VERSION 5.8 ;
BUSBITCHARS "[]" ;
DIVIDERCHAR "/" ;
UNITS
    DATABASE MICRONS 1000 ;
END UNITS

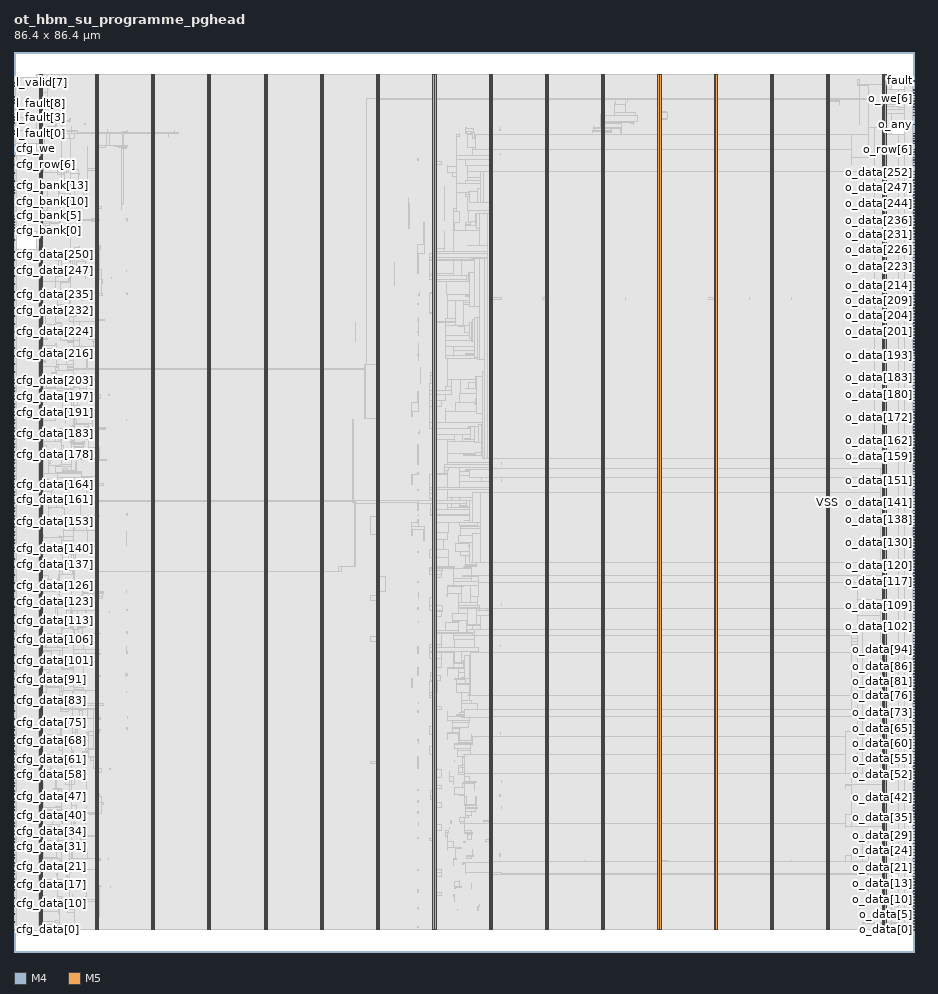
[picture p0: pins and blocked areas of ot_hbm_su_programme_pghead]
MACRO ot_hbm_su_programme_pghead
  FOREIGN ot_hbm_su_programme_pghead 0 0 ;
  CLASS BLOCK ;
  SIZE 86.4 BY 86.4 ;
  PIN cfg_bank[0]
    DIRECTION INPUT ;
    USE SIGNAL ;
    PORT
      LAYER M4 ;
        RECT  0 69.216 0.084 69.24 ;
    END
  END cfg_bank[0]
  PIN cfg_bank[10]
    DIRECTION INPUT ;
    USE SIGNAL ;
    PORT
      LAYER M4 ;
        RECT  0 72.048 0.084 72.072 ;
    END
  END cfg_bank[10]
  PIN cfg_bank[11]
    DIRECTION INPUT ;
    USE SIGNAL ;
    PORT
      LAYER M4 ;
        RECT  0 72.336 0.084 72.36 ;
    END
  END cfg_bank[11]
  PIN cfg_bank[12]
    DIRECTION INPUT ;
    USE SIGNAL ;
    PORT
      LAYER M4 ;
        RECT  0 72.624 0.084 72.648 ;
    END
  END cfg_bank[12]
  PIN cfg_bank[13]
    DIRECTION INPUT ;
    USE SIGNAL ;
    PORT
      LAYER M4 ;
        RECT  0 72.864 0.084 72.888 ;
    END
  END cfg_bank[13]
  PIN cfg_bank[14]
    DIRECTION INPUT ;
    USE SIGNAL ;
    PORT
      LAYER M4 ;
        RECT  0 73.152 0.084 73.176 ;
    END
  END cfg_bank[14]
  PIN cfg_bank[15]
    DIRECTION INPUT ;
    USE SIGNAL ;
    PORT
      LAYER M4 ;
        RECT  0 73.44 0.084 73.464 ;
    END
  END cfg_bank[15]
  PIN cfg_bank[1]
    DIRECTION INPUT ;
    USE SIGNAL ;
    PORT
      LAYER M4 ;
        RECT  0 69.504 0.084 69.528 ;
    END
  END cfg_bank[1]
  PIN cfg_bank[2]
    DIRECTION INPUT ;
    USE SIGNAL ;
    PORT
      LAYER M4 ;
        RECT  0 69.792 0.084 69.816 ;
    END
  END cfg_bank[2]
  PIN cfg_bank[3]
    DIRECTION INPUT ;
    USE SIGNAL ;
    PORT
      LAYER M4 ;
        RECT  0 70.08 0.084 70.104 ;
    END
  END cfg_bank[3]
  PIN cfg_bank[4]
    DIRECTION INPUT ;
    USE SIGNAL ;
    PORT
      LAYER M4 ;
        RECT  0 70.368 0.084 70.392 ;
    END
  END cfg_bank[4]
  PIN cfg_bank[5]
    DIRECTION INPUT ;
    USE SIGNAL ;
    PORT
      LAYER M4 ;
        RECT  0 70.656 0.084 70.68 ;
    END
  END cfg_bank[5]
  PIN cfg_bank[6]
    DIRECTION INPUT ;
    USE SIGNAL ;
    PORT
      LAYER M4 ;
        RECT  0 70.896 0.084 70.92 ;
    END
  END cfg_bank[6]
  PIN cfg_bank[7]
    DIRECTION INPUT ;
    USE SIGNAL ;
    PORT
      LAYER M4 ;
        RECT  0 71.184 0.084 71.208 ;
    END
  END cfg_bank[7]
  PIN cfg_bank[8]
    DIRECTION INPUT ;
    USE SIGNAL ;
    PORT
      LAYER M4 ;
        RECT  0 71.472 0.084 71.496 ;
    END
  END cfg_bank[8]
  PIN cfg_bank[9]
    DIRECTION INPUT ;
    USE SIGNAL ;
    PORT
      LAYER M4 ;
        RECT  0 71.76 0.084 71.784 ;
    END
  END cfg_bank[9]
  PIN cfg_data[0]
    DIRECTION INPUT ;
    USE SIGNAL ;
    PORT
      LAYER M4 ;
        RECT  0 2.112 0.084 2.136 ;
    END
  END cfg_data[0]
  PIN cfg_data[100]
    DIRECTION INPUT ;
    USE SIGNAL ;
    PORT
      LAYER M4 ;
        RECT  0 27.744 0.084 27.768 ;
    END
  END cfg_data[100]
  PIN cfg_data[101]
    DIRECTION INPUT ;
    USE SIGNAL ;
    PORT
      LAYER M4 ;
        RECT  0 27.984 0.084 28.008 ;
    END
  END cfg_data[101]
  PIN cfg_data[102]
    DIRECTION INPUT ;
    USE SIGNAL ;
    PORT
      LAYER M4 ;
        RECT  0 28.272 0.084 28.296 ;
    END
  END cfg_data[102]
  PIN cfg_data[103]
    DIRECTION INPUT ;
    USE SIGNAL ;
    PORT
      LAYER M4 ;
        RECT  0 28.512 0.084 28.536 ;
    END
  END cfg_data[103]
  PIN cfg_data[104]
    DIRECTION INPUT ;
    USE SIGNAL ;
    PORT
      LAYER M4 ;
        RECT  0 28.752 0.084 28.776 ;
    END
  END cfg_data[104]
  PIN cfg_data[105]
    DIRECTION INPUT ;
    USE SIGNAL ;
    PORT
      LAYER M4 ;
        RECT  0 29.04 0.084 29.064 ;
    END
  END cfg_data[105]
  PIN cfg_data[106]
    DIRECTION INPUT ;
    USE SIGNAL ;
    PORT
      LAYER M4 ;
        RECT  0 29.28 0.084 29.304 ;
    END
  END cfg_data[106]
  PIN cfg_data[107]
    DIRECTION INPUT ;
    USE SIGNAL ;
    PORT
      LAYER M4 ;
        RECT  0 29.52 0.084 29.544 ;
    END
  END cfg_data[107]
  PIN cfg_data[108]
    DIRECTION INPUT ;
    USE SIGNAL ;
    PORT
      LAYER M4 ;
        RECT  0 29.808 0.084 29.832 ;
    END
  END cfg_data[108]
  PIN cfg_data[109]
    DIRECTION INPUT ;
    USE SIGNAL ;
    PORT
      LAYER M4 ;
        RECT  0 30.048 0.084 30.072 ;
    END
  END cfg_data[109]
  PIN cfg_data[10]
    DIRECTION INPUT ;
    USE SIGNAL ;
    PORT
      LAYER M4 ;
        RECT  0 4.656 0.084 4.68 ;
    END
  END cfg_data[10]
  PIN cfg_data[110]
    DIRECTION INPUT ;
    USE SIGNAL ;
    PORT
      LAYER M4 ;
        RECT  0 30.288 0.084 30.312 ;
    END
  END cfg_data[110]
  PIN cfg_data[111]
    DIRECTION INPUT ;
    USE SIGNAL ;
    PORT
      LAYER M4 ;
        RECT  0 30.576 0.084 30.6 ;
    END
  END cfg_data[111]
  PIN cfg_data[112]
    DIRECTION INPUT ;
    USE SIGNAL ;
    PORT
      LAYER M4 ;
        RECT  0 30.816 0.084 30.84 ;
    END
  END cfg_data[112]
  PIN cfg_data[113]
    DIRECTION INPUT ;
    USE SIGNAL ;
    PORT
      LAYER M4 ;
        RECT  0 31.056 0.084 31.08 ;
    END
  END cfg_data[113]
  PIN cfg_data[114]
    DIRECTION INPUT ;
    USE SIGNAL ;
    PORT
      LAYER M4 ;
        RECT  0 31.344 0.084 31.368 ;
    END
  END cfg_data[114]
  PIN cfg_data[115]
    DIRECTION INPUT ;
    USE SIGNAL ;
    PORT
      LAYER M4 ;
        RECT  0 31.584 0.084 31.608 ;
    END
  END cfg_data[115]
  PIN cfg_data[116]
    DIRECTION INPUT ;
    USE SIGNAL ;
    PORT
      LAYER M4 ;
        RECT  0 31.824 0.084 31.848 ;
    END
  END cfg_data[116]
  PIN cfg_data[117]
    DIRECTION INPUT ;
    USE SIGNAL ;
    PORT
      LAYER M4 ;
        RECT  0 32.112 0.084 32.136 ;
    END
  END cfg_data[117]
  PIN cfg_data[118]
    DIRECTION INPUT ;
    USE SIGNAL ;
    PORT
      LAYER M4 ;
        RECT  0 32.352 0.084 32.376 ;
    END
  END cfg_data[118]
  PIN cfg_data[119]
    DIRECTION INPUT ;
    USE SIGNAL ;
    PORT
      LAYER M4 ;
        RECT  0 32.592 0.084 32.616 ;
    END
  END cfg_data[119]
  PIN cfg_data[11]
    DIRECTION INPUT ;
    USE SIGNAL ;
    PORT
      LAYER M4 ;
        RECT  0 4.944 0.084 4.968 ;
    END
  END cfg_data[11]
  PIN cfg_data[120]
    DIRECTION INPUT ;
    USE SIGNAL ;
    PORT
      LAYER M4 ;
        RECT  0 32.88 0.084 32.904 ;
    END
  END cfg_data[120]
  PIN cfg_data[121]
    DIRECTION INPUT ;
    USE SIGNAL ;
    PORT
      LAYER M4 ;
        RECT  0 33.12 0.084 33.144 ;
    END
  END cfg_data[121]
  PIN cfg_data[122]
    DIRECTION INPUT ;
    USE SIGNAL ;
    PORT
      LAYER M4 ;
        RECT  0 33.36 0.084 33.384 ;
    END
  END cfg_data[122]
  PIN cfg_data[123]
    DIRECTION INPUT ;
    USE SIGNAL ;
    PORT
      LAYER M4 ;
        RECT  0 33.648 0.084 33.672 ;
    END
  END cfg_data[123]
  PIN cfg_data[124]
    DIRECTION INPUT ;
    USE SIGNAL ;
    PORT
      LAYER M4 ;
        RECT  0 33.888 0.084 33.912 ;
    END
  END cfg_data[124]
  PIN cfg_data[125]
    DIRECTION INPUT ;
    USE SIGNAL ;
    PORT
      LAYER M4 ;
        RECT  0 34.128 0.084 34.152 ;
    END
  END cfg_data[125]
  PIN cfg_data[126]
    DIRECTION INPUT ;
    USE SIGNAL ;
    PORT
      LAYER M4 ;
        RECT  0 34.416 0.084 34.44 ;
    END
  END cfg_data[126]
  PIN cfg_data[127]
    DIRECTION INPUT ;
    USE SIGNAL ;
    PORT
      LAYER M4 ;
        RECT  0 34.656 0.084 34.68 ;
    END
  END cfg_data[127]
  PIN cfg_data[128]
    DIRECTION INPUT ;
    USE SIGNAL ;
    PORT
      LAYER M4 ;
        RECT  0 34.896 0.084 34.92 ;
    END
  END cfg_data[128]
  PIN cfg_data[129]
    DIRECTION INPUT ;
    USE SIGNAL ;
    PORT
      LAYER M4 ;
        RECT  0 35.184 0.084 35.208 ;
    END
  END cfg_data[129]
  PIN cfg_data[12]
    DIRECTION INPUT ;
    USE SIGNAL ;
    PORT
      LAYER M4 ;
        RECT  0 5.184 0.084 5.208 ;
    END
  END cfg_data[12]
  PIN cfg_data[130]
    DIRECTION INPUT ;
    USE SIGNAL ;
    PORT
      LAYER M4 ;
        RECT  0 35.424 0.084 35.448 ;
    END
  END cfg_data[130]
  PIN cfg_data[131]
    DIRECTION INPUT ;
    USE SIGNAL ;
    PORT
      LAYER M4 ;
        RECT  0 35.664 0.084 35.688 ;
    END
  END cfg_data[131]
  PIN cfg_data[132]
    DIRECTION INPUT ;
    USE SIGNAL ;
    PORT
      LAYER M4 ;
        RECT  0 35.952 0.084 35.976 ;
    END
  END cfg_data[132]
  PIN cfg_data[133]
    DIRECTION INPUT ;
    USE SIGNAL ;
    PORT
      LAYER M4 ;
        RECT  0 36.192 0.084 36.216 ;
    END
  END cfg_data[133]
  PIN cfg_data[134]
    DIRECTION INPUT ;
    USE SIGNAL ;
    PORT
      LAYER M4 ;
        RECT  0 36.432 0.084 36.456 ;
    END
  END cfg_data[134]
  PIN cfg_data[135]
    DIRECTION INPUT ;
    USE SIGNAL ;
    PORT
      LAYER M4 ;
        RECT  0 36.72 0.084 36.744 ;
    END
  END cfg_data[135]
  PIN cfg_data[136]
    DIRECTION INPUT ;
    USE SIGNAL ;
    PORT
      LAYER M4 ;
        RECT  0 36.96 0.084 36.984 ;
    END
  END cfg_data[136]
  PIN cfg_data[137]
    DIRECTION INPUT ;
    USE SIGNAL ;
    PORT
      LAYER M4 ;
        RECT  0 37.2 0.084 37.224 ;
    END
  END cfg_data[137]
  PIN cfg_data[138]
    DIRECTION INPUT ;
    USE SIGNAL ;
    PORT
      LAYER M4 ;
        RECT  0 37.488 0.084 37.512 ;
    END
  END cfg_data[138]
  PIN cfg_data[139]
    DIRECTION INPUT ;
    USE SIGNAL ;
    PORT
      LAYER M4 ;
        RECT  0 37.728 0.084 37.752 ;
    END
  END cfg_data[139]
  PIN cfg_data[13]
    DIRECTION INPUT ;
    USE SIGNAL ;
    PORT
      LAYER M4 ;
        RECT  0 5.424 0.084 5.448 ;
    END
  END cfg_data[13]
  PIN cfg_data[140]
    DIRECTION INPUT ;
    USE SIGNAL ;
    PORT
      LAYER M4 ;
        RECT  0 37.968 0.084 37.992 ;
    END
  END cfg_data[140]
  PIN cfg_data[141]
    DIRECTION INPUT ;
    USE SIGNAL ;
    PORT
      LAYER M4 ;
        RECT  0 38.256 0.084 38.28 ;
    END
  END cfg_data[141]
  PIN cfg_data[142]
    DIRECTION INPUT ;
    USE SIGNAL ;
    PORT
      LAYER M4 ;
        RECT  0 38.496 0.084 38.52 ;
    END
  END cfg_data[142]
  PIN cfg_data[143]
    DIRECTION INPUT ;
    USE SIGNAL ;
    PORT
      LAYER M4 ;
        RECT  0 38.784 0.084 38.808 ;
    END
  END cfg_data[143]
  PIN cfg_data[144]
    DIRECTION INPUT ;
    USE SIGNAL ;
    PORT
      LAYER M4 ;
        RECT  0 39.024 0.084 39.048 ;
    END
  END cfg_data[144]
  PIN cfg_data[145]
    DIRECTION INPUT ;
    USE SIGNAL ;
    PORT
      LAYER M4 ;
        RECT  0 39.264 0.084 39.288 ;
    END
  END cfg_data[145]
  PIN cfg_data[146]
    DIRECTION INPUT ;
    USE SIGNAL ;
    PORT
      LAYER M4 ;
        RECT  0 39.552 0.084 39.576 ;
    END
  END cfg_data[146]
  PIN cfg_data[147]
    DIRECTION INPUT ;
    USE SIGNAL ;
    PORT
      LAYER M4 ;
        RECT  0 39.792 0.084 39.816 ;
    END
  END cfg_data[147]
  PIN cfg_data[148]
    DIRECTION INPUT ;
    USE SIGNAL ;
    PORT
      LAYER M4 ;
        RECT  0 40.032 0.084 40.056 ;
    END
  END cfg_data[148]
  PIN cfg_data[149]
    DIRECTION INPUT ;
    USE SIGNAL ;
    PORT
      LAYER M4 ;
        RECT  0 40.32 0.084 40.344 ;
    END
  END cfg_data[149]
  PIN cfg_data[14]
    DIRECTION INPUT ;
    USE SIGNAL ;
    PORT
      LAYER M4 ;
        RECT  0 5.712 0.084 5.736 ;
    END
  END cfg_data[14]
  PIN cfg_data[150]
    DIRECTION INPUT ;
    USE SIGNAL ;
    PORT
      LAYER M4 ;
        RECT  0 40.56 0.084 40.584 ;
    END
  END cfg_data[150]
  PIN cfg_data[151]
    DIRECTION INPUT ;
    USE SIGNAL ;
    PORT
      LAYER M4 ;
        RECT  0 40.8 0.084 40.824 ;
    END
  END cfg_data[151]
  PIN cfg_data[152]
    DIRECTION INPUT ;
    USE SIGNAL ;
    PORT
      LAYER M4 ;
        RECT  0 41.088 0.084 41.112 ;
    END
  END cfg_data[152]
  PIN cfg_data[153]
    DIRECTION INPUT ;
    USE SIGNAL ;
    PORT
      LAYER M4 ;
        RECT  0 41.328 0.084 41.352 ;
    END
  END cfg_data[153]
  PIN cfg_data[154]
    DIRECTION INPUT ;
    USE SIGNAL ;
    PORT
      LAYER M4 ;
        RECT  0 41.568 0.084 41.592 ;
    END
  END cfg_data[154]
  PIN cfg_data[155]
    DIRECTION INPUT ;
    USE SIGNAL ;
    PORT
      LAYER M4 ;
        RECT  0 41.856 0.084 41.88 ;
    END
  END cfg_data[155]
  PIN cfg_data[156]
    DIRECTION INPUT ;
    USE SIGNAL ;
    PORT
      LAYER M4 ;
        RECT  0 42.096 0.084 42.12 ;
    END
  END cfg_data[156]
  PIN cfg_data[157]
    DIRECTION INPUT ;
    USE SIGNAL ;
    PORT
      LAYER M4 ;
        RECT  0 42.336 0.084 42.36 ;
    END
  END cfg_data[157]
  PIN cfg_data[158]
    DIRECTION INPUT ;
    USE SIGNAL ;
    PORT
      LAYER M4 ;
        RECT  0 42.624 0.084 42.648 ;
    END
  END cfg_data[158]
  PIN cfg_data[159]
    DIRECTION INPUT ;
    USE SIGNAL ;
    PORT
      LAYER M4 ;
        RECT  0 42.864 0.084 42.888 ;
    END
  END cfg_data[159]
  PIN cfg_data[15]
    DIRECTION INPUT ;
    USE SIGNAL ;
    PORT
      LAYER M4 ;
        RECT  0 5.952 0.084 5.976 ;
    END
  END cfg_data[15]
  PIN cfg_data[160]
    DIRECTION INPUT ;
    USE SIGNAL ;
    PORT
      LAYER M4 ;
        RECT  0 43.104 0.084 43.128 ;
    END
  END cfg_data[160]
  PIN cfg_data[161]
    DIRECTION INPUT ;
    USE SIGNAL ;
    PORT
      LAYER M4 ;
        RECT  0 43.392 0.084 43.416 ;
    END
  END cfg_data[161]
  PIN cfg_data[162]
    DIRECTION INPUT ;
    USE SIGNAL ;
    PORT
      LAYER M4 ;
        RECT  0 43.632 0.084 43.656 ;
    END
  END cfg_data[162]
  PIN cfg_data[163]
    DIRECTION INPUT ;
    USE SIGNAL ;
    PORT
      LAYER M4 ;
        RECT  0 43.872 0.084 43.896 ;
    END
  END cfg_data[163]
  PIN cfg_data[164]
    DIRECTION INPUT ;
    USE SIGNAL ;
    PORT
      LAYER M4 ;
        RECT  0 44.16 0.084 44.184 ;
    END
  END cfg_data[164]
  PIN cfg_data[165]
    DIRECTION INPUT ;
    USE SIGNAL ;
    PORT
      LAYER M4 ;
        RECT  0 44.4 0.084 44.424 ;
    END
  END cfg_data[165]
  PIN cfg_data[166]
    DIRECTION INPUT ;
    USE SIGNAL ;
    PORT
      LAYER M4 ;
        RECT  0 44.64 0.084 44.664 ;
    END
  END cfg_data[166]
  PIN cfg_data[167]
    DIRECTION INPUT ;
    USE SIGNAL ;
    PORT
      LAYER M4 ;
        RECT  0 44.928 0.084 44.952 ;
    END
  END cfg_data[167]
  PIN cfg_data[168]
    DIRECTION INPUT ;
    USE SIGNAL ;
    PORT
      LAYER M4 ;
        RECT  0 45.168 0.084 45.192 ;
    END
  END cfg_data[168]
  PIN cfg_data[169]
    DIRECTION INPUT ;
    USE SIGNAL ;
    PORT
      LAYER M4 ;
        RECT  0 45.408 0.084 45.432 ;
    END
  END cfg_data[169]
  PIN cfg_data[16]
    DIRECTION INPUT ;
    USE SIGNAL ;
    PORT
      LAYER M4 ;
        RECT  0 6.24 0.084 6.264 ;
    END
  END cfg_data[16]
  PIN cfg_data[170]
    DIRECTION INPUT ;
    USE SIGNAL ;
    PORT
      LAYER M4 ;
        RECT  0 45.696 0.084 45.72 ;
    END
  END cfg_data[170]
  PIN cfg_data[171]
    DIRECTION INPUT ;
    USE SIGNAL ;
    PORT
      LAYER M4 ;
        RECT  0 45.936 0.084 45.96 ;
    END
  END cfg_data[171]
  PIN cfg_data[172]
    DIRECTION INPUT ;
    USE SIGNAL ;
    PORT
      LAYER M4 ;
        RECT  0 46.176 0.084 46.2 ;
    END
  END cfg_data[172]
  PIN cfg_data[173]
    DIRECTION INPUT ;
    USE SIGNAL ;
    PORT
      LAYER M4 ;
        RECT  0 46.464 0.084 46.488 ;
    END
  END cfg_data[173]
  PIN cfg_data[174]
    DIRECTION INPUT ;
    USE SIGNAL ;
    PORT
      LAYER M4 ;
        RECT  0 46.704 0.084 46.728 ;
    END
  END cfg_data[174]
  PIN cfg_data[175]
    DIRECTION INPUT ;
    USE SIGNAL ;
    PORT
      LAYER M4 ;
        RECT  0 46.944 0.084 46.968 ;
    END
  END cfg_data[175]
  PIN cfg_data[176]
    DIRECTION INPUT ;
    USE SIGNAL ;
    PORT
      LAYER M4 ;
        RECT  0 47.232 0.084 47.256 ;
    END
  END cfg_data[176]
  PIN cfg_data[177]
    DIRECTION INPUT ;
    USE SIGNAL ;
    PORT
      LAYER M4 ;
        RECT  0 47.472 0.084 47.496 ;
    END
  END cfg_data[177]
  PIN cfg_data[178]
    DIRECTION INPUT ;
    USE SIGNAL ;
    PORT
      LAYER M4 ;
        RECT  0 47.712 0.084 47.736 ;
    END
  END cfg_data[178]
  PIN cfg_data[179]
    DIRECTION INPUT ;
    USE SIGNAL ;
    PORT
      LAYER M4 ;
        RECT  0 48 0.084 48.024 ;
    END
  END cfg_data[179]
  PIN cfg_data[17]
    DIRECTION INPUT ;
    USE SIGNAL ;
    PORT
      LAYER M4 ;
        RECT  0 6.48 0.084 6.504 ;
    END
  END cfg_data[17]
  PIN cfg_data[180]
    DIRECTION INPUT ;
    USE SIGNAL ;
    PORT
      LAYER M4 ;
        RECT  0 48.24 0.084 48.264 ;
    END
  END cfg_data[180]
  PIN cfg_data[181]
    DIRECTION INPUT ;
    USE SIGNAL ;
    PORT
      LAYER M4 ;
        RECT  0 48.48 0.084 48.504 ;
    END
  END cfg_data[181]
  PIN cfg_data[182]
    DIRECTION INPUT ;
    USE SIGNAL ;
    PORT
      LAYER M4 ;
        RECT  0 48.768 0.084 48.792 ;
    END
  END cfg_data[182]
  PIN cfg_data[183]
    DIRECTION INPUT ;
    USE SIGNAL ;
    PORT
      LAYER M4 ;
        RECT  0 49.008 0.084 49.032 ;
    END
  END cfg_data[183]
  PIN cfg_data[184]
    DIRECTION INPUT ;
    USE SIGNAL ;
    PORT
      LAYER M4 ;
        RECT  0 49.248 0.084 49.272 ;
    END
  END cfg_data[184]
  PIN cfg_data[185]
    DIRECTION INPUT ;
    USE SIGNAL ;
    PORT
      LAYER M4 ;
        RECT  0 49.536 0.084 49.56 ;
    END
  END cfg_data[185]
  PIN cfg_data[186]
    DIRECTION INPUT ;
    USE SIGNAL ;
    PORT
      LAYER M4 ;
        RECT  0 49.776 0.084 49.8 ;
    END
  END cfg_data[186]
  PIN cfg_data[187]
    DIRECTION INPUT ;
    USE SIGNAL ;
    PORT
      LAYER M4 ;
        RECT  0 50.016 0.084 50.04 ;
    END
  END cfg_data[187]
  PIN cfg_data[188]
    DIRECTION INPUT ;
    USE SIGNAL ;
    PORT
      LAYER M4 ;
        RECT  0 50.304 0.084 50.328 ;
    END
  END cfg_data[188]
  PIN cfg_data[189]
    DIRECTION INPUT ;
    USE SIGNAL ;
    PORT
      LAYER M4 ;
        RECT  0 50.544 0.084 50.568 ;
    END
  END cfg_data[189]
  PIN cfg_data[18]
    DIRECTION INPUT ;
    USE SIGNAL ;
    PORT
      LAYER M4 ;
        RECT  0 6.72 0.084 6.744 ;
    END
  END cfg_data[18]
  PIN cfg_data[190]
    DIRECTION INPUT ;
    USE SIGNAL ;
    PORT
      LAYER M4 ;
        RECT  0 50.784 0.084 50.808 ;
    END
  END cfg_data[190]
  PIN cfg_data[191]
    DIRECTION INPUT ;
    USE SIGNAL ;
    PORT
      LAYER M4 ;
        RECT  0 51.072 0.084 51.096 ;
    END
  END cfg_data[191]
  PIN cfg_data[192]
    DIRECTION INPUT ;
    USE SIGNAL ;
    PORT
      LAYER M4 ;
        RECT  0 51.312 0.084 51.336 ;
    END
  END cfg_data[192]
  PIN cfg_data[193]
    DIRECTION INPUT ;
    USE SIGNAL ;
    PORT
      LAYER M4 ;
        RECT  0 51.552 0.084 51.576 ;
    END
  END cfg_data[193]
  PIN cfg_data[194]
    DIRECTION INPUT ;
    USE SIGNAL ;
    PORT
      LAYER M4 ;
        RECT  0 51.84 0.084 51.864 ;
    END
  END cfg_data[194]
  PIN cfg_data[195]
    DIRECTION INPUT ;
    USE SIGNAL ;
    PORT
      LAYER M4 ;
        RECT  0 52.08 0.084 52.104 ;
    END
  END cfg_data[195]
  PIN cfg_data[196]
    DIRECTION INPUT ;
    USE SIGNAL ;
    PORT
      LAYER M4 ;
        RECT  0 52.32 0.084 52.344 ;
    END
  END cfg_data[196]
  PIN cfg_data[197]
    DIRECTION INPUT ;
    USE SIGNAL ;
    PORT
      LAYER M4 ;
        RECT  0 52.608 0.084 52.632 ;
    END
  END cfg_data[197]
  PIN cfg_data[198]
    DIRECTION INPUT ;
    USE SIGNAL ;
    PORT
      LAYER M4 ;
        RECT  0 52.848 0.084 52.872 ;
    END
  END cfg_data[198]
  PIN cfg_data[199]
    DIRECTION INPUT ;
    USE SIGNAL ;
    PORT
      LAYER M4 ;
        RECT  0 53.088 0.084 53.112 ;
    END
  END cfg_data[199]
  PIN cfg_data[19]
    DIRECTION INPUT ;
    USE SIGNAL ;
    PORT
      LAYER M4 ;
        RECT  0 7.008 0.084 7.032 ;
    END
  END cfg_data[19]
  PIN cfg_data[1]
    DIRECTION INPUT ;
    USE SIGNAL ;
    PORT
      LAYER M4 ;
        RECT  0 2.352 0.084 2.376 ;
    END
  END cfg_data[1]
  PIN cfg_data[200]
    DIRECTION INPUT ;
    USE SIGNAL ;
    PORT
      LAYER M4 ;
        RECT  0 53.376 0.084 53.4 ;
    END
  END cfg_data[200]
  PIN cfg_data[201]
    DIRECTION INPUT ;
    USE SIGNAL ;
    PORT
      LAYER M4 ;
        RECT  0 53.616 0.084 53.64 ;
    END
  END cfg_data[201]
  PIN cfg_data[202]
    DIRECTION INPUT ;
    USE SIGNAL ;
    PORT
      LAYER M4 ;
        RECT  0 53.856 0.084 53.88 ;
    END
  END cfg_data[202]
  PIN cfg_data[203]
    DIRECTION INPUT ;
    USE SIGNAL ;
    PORT
      LAYER M4 ;
        RECT  0 54.144 0.084 54.168 ;
    END
  END cfg_data[203]
  PIN cfg_data[204]
    DIRECTION INPUT ;
    USE SIGNAL ;
    PORT
      LAYER M4 ;
        RECT  0 54.384 0.084 54.408 ;
    END
  END cfg_data[204]
  PIN cfg_data[205]
    DIRECTION INPUT ;
    USE SIGNAL ;
    PORT
      LAYER M4 ;
        RECT  0 54.624 0.084 54.648 ;
    END
  END cfg_data[205]
  PIN cfg_data[206]
    DIRECTION INPUT ;
    USE SIGNAL ;
    PORT
      LAYER M4 ;
        RECT  0 54.912 0.084 54.936 ;
    END
  END cfg_data[206]
  PIN cfg_data[207]
    DIRECTION INPUT ;
    USE SIGNAL ;
    PORT
      LAYER M4 ;
        RECT  0 55.152 0.084 55.176 ;
    END
  END cfg_data[207]
  PIN cfg_data[208]
    DIRECTION INPUT ;
    USE SIGNAL ;
    PORT
      LAYER M4 ;
        RECT  0 55.44 0.084 55.464 ;
    END
  END cfg_data[208]
  PIN cfg_data[209]
    DIRECTION INPUT ;
    USE SIGNAL ;
    PORT
      LAYER M4 ;
        RECT  0 55.68 0.084 55.704 ;
    END
  END cfg_data[209]
  PIN cfg_data[20]
    DIRECTION INPUT ;
    USE SIGNAL ;
    PORT
      LAYER M4 ;
        RECT  0 7.248 0.084 7.272 ;
    END
  END cfg_data[20]
  PIN cfg_data[210]
    DIRECTION INPUT ;
    USE SIGNAL ;
    PORT
      LAYER M4 ;
        RECT  0 55.92 0.084 55.944 ;
    END
  END cfg_data[210]
  PIN cfg_data[211]
    DIRECTION INPUT ;
    USE SIGNAL ;
    PORT
      LAYER M4 ;
        RECT  0 56.208 0.084 56.232 ;
    END
  END cfg_data[211]
  PIN cfg_data[212]
    DIRECTION INPUT ;
    USE SIGNAL ;
    PORT
      LAYER M4 ;
        RECT  0 56.448 0.084 56.472 ;
    END
  END cfg_data[212]
  PIN cfg_data[213]
    DIRECTION INPUT ;
    USE SIGNAL ;
    PORT
      LAYER M4 ;
        RECT  0 56.688 0.084 56.712 ;
    END
  END cfg_data[213]
  PIN cfg_data[214]
    DIRECTION INPUT ;
    USE SIGNAL ;
    PORT
      LAYER M4 ;
        RECT  0 56.976 0.084 57 ;
    END
  END cfg_data[214]
  PIN cfg_data[215]
    DIRECTION INPUT ;
    USE SIGNAL ;
    PORT
      LAYER M4 ;
        RECT  0 57.216 0.084 57.24 ;
    END
  END cfg_data[215]
  PIN cfg_data[216]
    DIRECTION INPUT ;
    USE SIGNAL ;
    PORT
      LAYER M4 ;
        RECT  0 57.456 0.084 57.48 ;
    END
  END cfg_data[216]
  PIN cfg_data[217]
    DIRECTION INPUT ;
    USE SIGNAL ;
    PORT
      LAYER M4 ;
        RECT  0 57.744 0.084 57.768 ;
    END
  END cfg_data[217]
  PIN cfg_data[218]
    DIRECTION INPUT ;
    USE SIGNAL ;
    PORT
      LAYER M4 ;
        RECT  0 57.984 0.084 58.008 ;
    END
  END cfg_data[218]
  PIN cfg_data[219]
    DIRECTION INPUT ;
    USE SIGNAL ;
    PORT
      LAYER M4 ;
        RECT  0 58.224 0.084 58.248 ;
    END
  END cfg_data[219]
  PIN cfg_data[21]
    DIRECTION INPUT ;
    USE SIGNAL ;
    PORT
      LAYER M4 ;
        RECT  0 7.488 0.084 7.512 ;
    END
  END cfg_data[21]
  PIN cfg_data[220]
    DIRECTION INPUT ;
    USE SIGNAL ;
    PORT
      LAYER M4 ;
        RECT  0 58.512 0.084 58.536 ;
    END
  END cfg_data[220]
  PIN cfg_data[221]
    DIRECTION INPUT ;
    USE SIGNAL ;
    PORT
      LAYER M4 ;
        RECT  0 58.752 0.084 58.776 ;
    END
  END cfg_data[221]
  PIN cfg_data[222]
    DIRECTION INPUT ;
    USE SIGNAL ;
    PORT
      LAYER M4 ;
        RECT  0 58.992 0.084 59.016 ;
    END
  END cfg_data[222]
  PIN cfg_data[223]
    DIRECTION INPUT ;
    USE SIGNAL ;
    PORT
      LAYER M4 ;
        RECT  0 59.28 0.084 59.304 ;
    END
  END cfg_data[223]
  PIN cfg_data[224]
    DIRECTION INPUT ;
    USE SIGNAL ;
    PORT
      LAYER M4 ;
        RECT  0 59.52 0.084 59.544 ;
    END
  END cfg_data[224]
  PIN cfg_data[225]
    DIRECTION INPUT ;
    USE SIGNAL ;
    PORT
      LAYER M4 ;
        RECT  0 59.76 0.084 59.784 ;
    END
  END cfg_data[225]
  PIN cfg_data[226]
    DIRECTION INPUT ;
    USE SIGNAL ;
    PORT
      LAYER M4 ;
        RECT  0 60.048 0.084 60.072 ;
    END
  END cfg_data[226]
  PIN cfg_data[227]
    DIRECTION INPUT ;
    USE SIGNAL ;
    PORT
      LAYER M4 ;
        RECT  0 60.288 0.084 60.312 ;
    END
  END cfg_data[227]
  PIN cfg_data[228]
    DIRECTION INPUT ;
    USE SIGNAL ;
    PORT
      LAYER M4 ;
        RECT  0 60.528 0.084 60.552 ;
    END
  END cfg_data[228]
  PIN cfg_data[229]
    DIRECTION INPUT ;
    USE SIGNAL ;
    PORT
      LAYER M4 ;
        RECT  0 60.816 0.084 60.84 ;
    END
  END cfg_data[229]
  PIN cfg_data[22]
    DIRECTION INPUT ;
    USE SIGNAL ;
    PORT
      LAYER M4 ;
        RECT  0 7.776 0.084 7.8 ;
    END
  END cfg_data[22]
  PIN cfg_data[230]
    DIRECTION INPUT ;
    USE SIGNAL ;
    PORT
      LAYER M4 ;
        RECT  0 61.056 0.084 61.08 ;
    END
  END cfg_data[230]
  PIN cfg_data[231]
    DIRECTION INPUT ;
    USE SIGNAL ;
    PORT
      LAYER M4 ;
        RECT  0 61.296 0.084 61.32 ;
    END
  END cfg_data[231]
  PIN cfg_data[232]
    DIRECTION INPUT ;
    USE SIGNAL ;
    PORT
      LAYER M4 ;
        RECT  0 61.584 0.084 61.608 ;
    END
  END cfg_data[232]
  PIN cfg_data[233]
    DIRECTION INPUT ;
    USE SIGNAL ;
    PORT
      LAYER M4 ;
        RECT  0 61.824 0.084 61.848 ;
    END
  END cfg_data[233]
  PIN cfg_data[234]
    DIRECTION INPUT ;
    USE SIGNAL ;
    PORT
      LAYER M4 ;
        RECT  0 62.064 0.084 62.088 ;
    END
  END cfg_data[234]
  PIN cfg_data[235]
    DIRECTION INPUT ;
    USE SIGNAL ;
    PORT
      LAYER M4 ;
        RECT  0 62.352 0.084 62.376 ;
    END
  END cfg_data[235]
  PIN cfg_data[236]
    DIRECTION INPUT ;
    USE SIGNAL ;
    PORT
      LAYER M4 ;
        RECT  0 62.592 0.084 62.616 ;
    END
  END cfg_data[236]
  PIN cfg_data[237]
    DIRECTION INPUT ;
    USE SIGNAL ;
    PORT
      LAYER M4 ;
        RECT  0 62.832 0.084 62.856 ;
    END
  END cfg_data[237]
  PIN cfg_data[238]
    DIRECTION INPUT ;
    USE SIGNAL ;
    PORT
      LAYER M4 ;
        RECT  0 63.12 0.084 63.144 ;
    END
  END cfg_data[238]
  PIN cfg_data[239]
    DIRECTION INPUT ;
    USE SIGNAL ;
    PORT
      LAYER M4 ;
        RECT  0 63.36 0.084 63.384 ;
    END
  END cfg_data[239]
  PIN cfg_data[23]
    DIRECTION INPUT ;
    USE SIGNAL ;
    PORT
      LAYER M4 ;
        RECT  0 8.016 0.084 8.04 ;
    END
  END cfg_data[23]
  PIN cfg_data[240]
    DIRECTION INPUT ;
    USE SIGNAL ;
    PORT
      LAYER M4 ;
        RECT  0 63.6 0.084 63.624 ;
    END
  END cfg_data[240]
  PIN cfg_data[241]
    DIRECTION INPUT ;
    USE SIGNAL ;
    PORT
      LAYER M4 ;
        RECT  0 63.888 0.084 63.912 ;
    END
  END cfg_data[241]
  PIN cfg_data[242]
    DIRECTION INPUT ;
    USE SIGNAL ;
    PORT
      LAYER M4 ;
        RECT  0 64.128 0.084 64.152 ;
    END
  END cfg_data[242]
  PIN cfg_data[243]
    DIRECTION INPUT ;
    USE SIGNAL ;
    PORT
      LAYER M4 ;
        RECT  0 64.368 0.084 64.392 ;
    END
  END cfg_data[243]
  PIN cfg_data[244]
    DIRECTION INPUT ;
    USE SIGNAL ;
    PORT
      LAYER M4 ;
        RECT  0 64.656 0.084 64.68 ;
    END
  END cfg_data[244]
  PIN cfg_data[245]
    DIRECTION INPUT ;
    USE SIGNAL ;
    PORT
      LAYER M4 ;
        RECT  0 64.896 0.084 64.92 ;
    END
  END cfg_data[245]
  PIN cfg_data[246]
    DIRECTION INPUT ;
    USE SIGNAL ;
    PORT
      LAYER M4 ;
        RECT  0 65.136 0.084 65.16 ;
    END
  END cfg_data[246]
  PIN cfg_data[247]
    DIRECTION INPUT ;
    USE SIGNAL ;
    PORT
      LAYER M4 ;
        RECT  0 65.424 0.084 65.448 ;
    END
  END cfg_data[247]
  PIN cfg_data[248]
    DIRECTION INPUT ;
    USE SIGNAL ;
    PORT
      LAYER M4 ;
        RECT  0 65.664 0.084 65.688 ;
    END
  END cfg_data[248]
  PIN cfg_data[249]
    DIRECTION INPUT ;
    USE SIGNAL ;
    PORT
      LAYER M4 ;
        RECT  0 65.904 0.084 65.928 ;
    END
  END cfg_data[249]
  PIN cfg_data[24]
    DIRECTION INPUT ;
    USE SIGNAL ;
    PORT
      LAYER M4 ;
        RECT  0 8.256 0.084 8.28 ;
    END
  END cfg_data[24]
  PIN cfg_data[250]
    DIRECTION INPUT ;
    USE SIGNAL ;
    PORT
      LAYER M4 ;
        RECT  0 66.192 0.084 66.216 ;
    END
  END cfg_data[250]
  PIN cfg_data[251]
    DIRECTION INPUT ;
    USE SIGNAL ;
    PORT
      LAYER M4 ;
        RECT  0 66.432 0.084 66.456 ;
    END
  END cfg_data[251]
  PIN cfg_data[252]
    DIRECTION INPUT ;
    USE SIGNAL ;
    PORT
      LAYER M4 ;
        RECT  0 66.672 0.084 66.696 ;
    END
  END cfg_data[252]
  PIN cfg_data[253]
    DIRECTION INPUT ;
    USE SIGNAL ;
    PORT
      LAYER M4 ;
        RECT  0 66.96 0.084 66.984 ;
    END
  END cfg_data[253]
  PIN cfg_data[254]
    DIRECTION INPUT ;
    USE SIGNAL ;
    PORT
      LAYER M4 ;
        RECT  0 67.2 0.084 67.224 ;
    END
  END cfg_data[254]
  PIN cfg_data[255]
    DIRECTION INPUT ;
    USE SIGNAL ;
    PORT
      LAYER M4 ;
        RECT  0 67.44 0.084 67.464 ;
    END
  END cfg_data[255]
  PIN cfg_data[25]
    DIRECTION INPUT ;
    USE SIGNAL ;
    PORT
      LAYER M4 ;
        RECT  0 8.544 0.084 8.568 ;
    END
  END cfg_data[25]
  PIN cfg_data[26]
    DIRECTION INPUT ;
    USE SIGNAL ;
    PORT
      LAYER M4 ;
        RECT  0 8.784 0.084 8.808 ;
    END
  END cfg_data[26]
  PIN cfg_data[27]
    DIRECTION INPUT ;
    USE SIGNAL ;
    PORT
      LAYER M4 ;
        RECT  0 9.024 0.084 9.048 ;
    END
  END cfg_data[27]
  PIN cfg_data[28]
    DIRECTION INPUT ;
    USE SIGNAL ;
    PORT
      LAYER M4 ;
        RECT  0 9.312 0.084 9.336 ;
    END
  END cfg_data[28]
  PIN cfg_data[29]
    DIRECTION INPUT ;
    USE SIGNAL ;
    PORT
      LAYER M4 ;
        RECT  0 9.552 0.084 9.576 ;
    END
  END cfg_data[29]
  PIN cfg_data[2]
    DIRECTION INPUT ;
    USE SIGNAL ;
    PORT
      LAYER M4 ;
        RECT  0 2.64 0.084 2.664 ;
    END
  END cfg_data[2]
  PIN cfg_data[30]
    DIRECTION INPUT ;
    USE SIGNAL ;
    PORT
      LAYER M4 ;
        RECT  0 9.792 0.084 9.816 ;
    END
  END cfg_data[30]
  PIN cfg_data[31]
    DIRECTION INPUT ;
    USE SIGNAL ;
    PORT
      LAYER M4 ;
        RECT  0 10.08 0.084 10.104 ;
    END
  END cfg_data[31]
  PIN cfg_data[32]
    DIRECTION INPUT ;
    USE SIGNAL ;
    PORT
      LAYER M4 ;
        RECT  0 10.32 0.084 10.344 ;
    END
  END cfg_data[32]
  PIN cfg_data[33]
    DIRECTION INPUT ;
    USE SIGNAL ;
    PORT
      LAYER M4 ;
        RECT  0 10.56 0.084 10.584 ;
    END
  END cfg_data[33]
  PIN cfg_data[34]
    DIRECTION INPUT ;
    USE SIGNAL ;
    PORT
      LAYER M4 ;
        RECT  0 10.848 0.084 10.872 ;
    END
  END cfg_data[34]
  PIN cfg_data[35]
    DIRECTION INPUT ;
    USE SIGNAL ;
    PORT
      LAYER M4 ;
        RECT  0 11.088 0.084 11.112 ;
    END
  END cfg_data[35]
  PIN cfg_data[36]
    DIRECTION INPUT ;
    USE SIGNAL ;
    PORT
      LAYER M4 ;
        RECT  0 11.328 0.084 11.352 ;
    END
  END cfg_data[36]
  PIN cfg_data[37]
    DIRECTION INPUT ;
    USE SIGNAL ;
    PORT
      LAYER M4 ;
        RECT  0 11.616 0.084 11.64 ;
    END
  END cfg_data[37]
  PIN cfg_data[38]
    DIRECTION INPUT ;
    USE SIGNAL ;
    PORT
      LAYER M4 ;
        RECT  0 11.856 0.084 11.88 ;
    END
  END cfg_data[38]
  PIN cfg_data[39]
    DIRECTION INPUT ;
    USE SIGNAL ;
    PORT
      LAYER M4 ;
        RECT  0 12.096 0.084 12.12 ;
    END
  END cfg_data[39]
  PIN cfg_data[3]
    DIRECTION INPUT ;
    USE SIGNAL ;
    PORT
      LAYER M4 ;
        RECT  0 2.88 0.084 2.904 ;
    END
  END cfg_data[3]
  PIN cfg_data[40]
    DIRECTION INPUT ;
    USE SIGNAL ;
    PORT
      LAYER M4 ;
        RECT  0 12.384 0.084 12.408 ;
    END
  END cfg_data[40]
  PIN cfg_data[41]
    DIRECTION INPUT ;
    USE SIGNAL ;
    PORT
      LAYER M4 ;
        RECT  0 12.624 0.084 12.648 ;
    END
  END cfg_data[41]
  PIN cfg_data[42]
    DIRECTION INPUT ;
    USE SIGNAL ;
    PORT
      LAYER M4 ;
        RECT  0 12.864 0.084 12.888 ;
    END
  END cfg_data[42]
  PIN cfg_data[43]
    DIRECTION INPUT ;
    USE SIGNAL ;
    PORT
      LAYER M4 ;
        RECT  0 13.152 0.084 13.176 ;
    END
  END cfg_data[43]
  PIN cfg_data[44]
    DIRECTION INPUT ;
    USE SIGNAL ;
    PORT
      LAYER M4 ;
        RECT  0 13.392 0.084 13.416 ;
    END
  END cfg_data[44]
  PIN cfg_data[45]
    DIRECTION INPUT ;
    USE SIGNAL ;
    PORT
      LAYER M4 ;
        RECT  0 13.632 0.084 13.656 ;
    END
  END cfg_data[45]
  PIN cfg_data[46]
    DIRECTION INPUT ;
    USE SIGNAL ;
    PORT
      LAYER M4 ;
        RECT  0 13.92 0.084 13.944 ;
    END
  END cfg_data[46]
  PIN cfg_data[47]
    DIRECTION INPUT ;
    USE SIGNAL ;
    PORT
      LAYER M4 ;
        RECT  0 14.16 0.084 14.184 ;
    END
  END cfg_data[47]
  PIN cfg_data[48]
    DIRECTION INPUT ;
    USE SIGNAL ;
    PORT
      LAYER M4 ;
        RECT  0 14.4 0.084 14.424 ;
    END
  END cfg_data[48]
  PIN cfg_data[49]
    DIRECTION INPUT ;
    USE SIGNAL ;
    PORT
      LAYER M4 ;
        RECT  0 14.688 0.084 14.712 ;
    END
  END cfg_data[49]
  PIN cfg_data[4]
    DIRECTION INPUT ;
    USE SIGNAL ;
    PORT
      LAYER M4 ;
        RECT  0 3.12 0.084 3.144 ;
    END
  END cfg_data[4]
  PIN cfg_data[50]
    DIRECTION INPUT ;
    USE SIGNAL ;
    PORT
      LAYER M4 ;
        RECT  0 14.928 0.084 14.952 ;
    END
  END cfg_data[50]
  PIN cfg_data[51]
    DIRECTION INPUT ;
    USE SIGNAL ;
    PORT
      LAYER M4 ;
        RECT  0 15.168 0.084 15.192 ;
    END
  END cfg_data[51]
  PIN cfg_data[52]
    DIRECTION INPUT ;
    USE SIGNAL ;
    PORT
      LAYER M4 ;
        RECT  0 15.456 0.084 15.48 ;
    END
  END cfg_data[52]
  PIN cfg_data[53]
    DIRECTION INPUT ;
    USE SIGNAL ;
    PORT
      LAYER M4 ;
        RECT  0 15.696 0.084 15.72 ;
    END
  END cfg_data[53]
  PIN cfg_data[54]
    DIRECTION INPUT ;
    USE SIGNAL ;
    PORT
      LAYER M4 ;
        RECT  0 15.936 0.084 15.96 ;
    END
  END cfg_data[54]
  PIN cfg_data[55]
    DIRECTION INPUT ;
    USE SIGNAL ;
    PORT
      LAYER M4 ;
        RECT  0 16.224 0.084 16.248 ;
    END
  END cfg_data[55]
  PIN cfg_data[56]
    DIRECTION INPUT ;
    USE SIGNAL ;
    PORT
      LAYER M4 ;
        RECT  0 16.464 0.084 16.488 ;
    END
  END cfg_data[56]
  PIN cfg_data[57]
    DIRECTION INPUT ;
    USE SIGNAL ;
    PORT
      LAYER M4 ;
        RECT  0 16.704 0.084 16.728 ;
    END
  END cfg_data[57]
  PIN cfg_data[58]
    DIRECTION INPUT ;
    USE SIGNAL ;
    PORT
      LAYER M4 ;
        RECT  0 16.992 0.084 17.016 ;
    END
  END cfg_data[58]
  PIN cfg_data[59]
    DIRECTION INPUT ;
    USE SIGNAL ;
    PORT
      LAYER M4 ;
        RECT  0 17.232 0.084 17.256 ;
    END
  END cfg_data[59]
  PIN cfg_data[5]
    DIRECTION INPUT ;
    USE SIGNAL ;
    PORT
      LAYER M4 ;
        RECT  0 3.408 0.084 3.432 ;
    END
  END cfg_data[5]
  PIN cfg_data[60]
    DIRECTION INPUT ;
    USE SIGNAL ;
    PORT
      LAYER M4 ;
        RECT  0 17.472 0.084 17.496 ;
    END
  END cfg_data[60]
  PIN cfg_data[61]
    DIRECTION INPUT ;
    USE SIGNAL ;
    PORT
      LAYER M4 ;
        RECT  0 17.76 0.084 17.784 ;
    END
  END cfg_data[61]
  PIN cfg_data[62]
    DIRECTION INPUT ;
    USE SIGNAL ;
    PORT
      LAYER M4 ;
        RECT  0 18 0.084 18.024 ;
    END
  END cfg_data[62]
  PIN cfg_data[63]
    DIRECTION INPUT ;
    USE SIGNAL ;
    PORT
      LAYER M4 ;
        RECT  0 18.24 0.084 18.264 ;
    END
  END cfg_data[63]
  PIN cfg_data[64]
    DIRECTION INPUT ;
    USE SIGNAL ;
    PORT
      LAYER M4 ;
        RECT  0 18.528 0.084 18.552 ;
    END
  END cfg_data[64]
  PIN cfg_data[65]
    DIRECTION INPUT ;
    USE SIGNAL ;
    PORT
      LAYER M4 ;
        RECT  0 18.768 0.084 18.792 ;
    END
  END cfg_data[65]
  PIN cfg_data[66]
    DIRECTION INPUT ;
    USE SIGNAL ;
    PORT
      LAYER M4 ;
        RECT  0 19.008 0.084 19.032 ;
    END
  END cfg_data[66]
  PIN cfg_data[67]
    DIRECTION INPUT ;
    USE SIGNAL ;
    PORT
      LAYER M4 ;
        RECT  0 19.296 0.084 19.32 ;
    END
  END cfg_data[67]
  PIN cfg_data[68]
    DIRECTION INPUT ;
    USE SIGNAL ;
    PORT
      LAYER M4 ;
        RECT  0 19.536 0.084 19.56 ;
    END
  END cfg_data[68]
  PIN cfg_data[69]
    DIRECTION INPUT ;
    USE SIGNAL ;
    PORT
      LAYER M4 ;
        RECT  0 19.776 0.084 19.8 ;
    END
  END cfg_data[69]
  PIN cfg_data[6]
    DIRECTION INPUT ;
    USE SIGNAL ;
    PORT
      LAYER M4 ;
        RECT  0 3.648 0.084 3.672 ;
    END
  END cfg_data[6]
  PIN cfg_data[70]
    DIRECTION INPUT ;
    USE SIGNAL ;
    PORT
      LAYER M4 ;
        RECT  0 20.064 0.084 20.088 ;
    END
  END cfg_data[70]
  PIN cfg_data[71]
    DIRECTION INPUT ;
    USE SIGNAL ;
    PORT
      LAYER M4 ;
        RECT  0 20.304 0.084 20.328 ;
    END
  END cfg_data[71]
  PIN cfg_data[72]
    DIRECTION INPUT ;
    USE SIGNAL ;
    PORT
      LAYER M4 ;
        RECT  0 20.544 0.084 20.568 ;
    END
  END cfg_data[72]
  PIN cfg_data[73]
    DIRECTION INPUT ;
    USE SIGNAL ;
    PORT
      LAYER M4 ;
        RECT  0 20.832 0.084 20.856 ;
    END
  END cfg_data[73]
  PIN cfg_data[74]
    DIRECTION INPUT ;
    USE SIGNAL ;
    PORT
      LAYER M4 ;
        RECT  0 21.072 0.084 21.096 ;
    END
  END cfg_data[74]
  PIN cfg_data[75]
    DIRECTION INPUT ;
    USE SIGNAL ;
    PORT
      LAYER M4 ;
        RECT  0 21.312 0.084 21.336 ;
    END
  END cfg_data[75]
  PIN cfg_data[76]
    DIRECTION INPUT ;
    USE SIGNAL ;
    PORT
      LAYER M4 ;
        RECT  0 21.6 0.084 21.624 ;
    END
  END cfg_data[76]
  PIN cfg_data[77]
    DIRECTION INPUT ;
    USE SIGNAL ;
    PORT
      LAYER M4 ;
        RECT  0 21.84 0.084 21.864 ;
    END
  END cfg_data[77]
  PIN cfg_data[78]
    DIRECTION INPUT ;
    USE SIGNAL ;
    PORT
      LAYER M4 ;
        RECT  0 22.128 0.084 22.152 ;
    END
  END cfg_data[78]
  PIN cfg_data[79]
    DIRECTION INPUT ;
    USE SIGNAL ;
    PORT
      LAYER M4 ;
        RECT  0 22.368 0.084 22.392 ;
    END
  END cfg_data[79]
  PIN cfg_data[7]
    DIRECTION INPUT ;
    USE SIGNAL ;
    PORT
      LAYER M4 ;
        RECT  0 3.888 0.084 3.912 ;
    END
  END cfg_data[7]
  PIN cfg_data[80]
    DIRECTION INPUT ;
    USE SIGNAL ;
    PORT
      LAYER M4 ;
        RECT  0 22.608 0.084 22.632 ;
    END
  END cfg_data[80]
  PIN cfg_data[81]
    DIRECTION INPUT ;
    USE SIGNAL ;
    PORT
      LAYER M4 ;
        RECT  0 22.896 0.084 22.92 ;
    END
  END cfg_data[81]
  PIN cfg_data[82]
    DIRECTION INPUT ;
    USE SIGNAL ;
    PORT
      LAYER M4 ;
        RECT  0 23.136 0.084 23.16 ;
    END
  END cfg_data[82]
  PIN cfg_data[83]
    DIRECTION INPUT ;
    USE SIGNAL ;
    PORT
      LAYER M4 ;
        RECT  0 23.376 0.084 23.4 ;
    END
  END cfg_data[83]
  PIN cfg_data[84]
    DIRECTION INPUT ;
    USE SIGNAL ;
    PORT
      LAYER M4 ;
        RECT  0 23.664 0.084 23.688 ;
    END
  END cfg_data[84]
  PIN cfg_data[85]
    DIRECTION INPUT ;
    USE SIGNAL ;
    PORT
      LAYER M4 ;
        RECT  0 23.904 0.084 23.928 ;
    END
  END cfg_data[85]
  PIN cfg_data[86]
    DIRECTION INPUT ;
    USE SIGNAL ;
    PORT
      LAYER M4 ;
        RECT  0 24.144 0.084 24.168 ;
    END
  END cfg_data[86]
  PIN cfg_data[87]
    DIRECTION INPUT ;
    USE SIGNAL ;
    PORT
      LAYER M4 ;
        RECT  0 24.432 0.084 24.456 ;
    END
  END cfg_data[87]
  PIN cfg_data[88]
    DIRECTION INPUT ;
    USE SIGNAL ;
    PORT
      LAYER M4 ;
        RECT  0 24.672 0.084 24.696 ;
    END
  END cfg_data[88]
  PIN cfg_data[89]
    DIRECTION INPUT ;
    USE SIGNAL ;
    PORT
      LAYER M4 ;
        RECT  0 24.912 0.084 24.936 ;
    END
  END cfg_data[89]
  PIN cfg_data[8]
    DIRECTION INPUT ;
    USE SIGNAL ;
    PORT
      LAYER M4 ;
        RECT  0 4.176 0.084 4.2 ;
    END
  END cfg_data[8]
  PIN cfg_data[90]
    DIRECTION INPUT ;
    USE SIGNAL ;
    PORT
      LAYER M4 ;
        RECT  0 25.2 0.084 25.224 ;
    END
  END cfg_data[90]
  PIN cfg_data[91]
    DIRECTION INPUT ;
    USE SIGNAL ;
    PORT
      LAYER M4 ;
        RECT  0 25.44 0.084 25.464 ;
    END
  END cfg_data[91]
  PIN cfg_data[92]
    DIRECTION INPUT ;
    USE SIGNAL ;
    PORT
      LAYER M4 ;
        RECT  0 25.68 0.084 25.704 ;
    END
  END cfg_data[92]
  PIN cfg_data[93]
    DIRECTION INPUT ;
    USE SIGNAL ;
    PORT
      LAYER M4 ;
        RECT  0 25.968 0.084 25.992 ;
    END
  END cfg_data[93]
  PIN cfg_data[94]
    DIRECTION INPUT ;
    USE SIGNAL ;
    PORT
      LAYER M4 ;
        RECT  0 26.208 0.084 26.232 ;
    END
  END cfg_data[94]
  PIN cfg_data[95]
    DIRECTION INPUT ;
    USE SIGNAL ;
    PORT
      LAYER M4 ;
        RECT  0 26.448 0.084 26.472 ;
    END
  END cfg_data[95]
  PIN cfg_data[96]
    DIRECTION INPUT ;
    USE SIGNAL ;
    PORT
      LAYER M4 ;
        RECT  0 26.736 0.084 26.76 ;
    END
  END cfg_data[96]
  PIN cfg_data[97]
    DIRECTION INPUT ;
    USE SIGNAL ;
    PORT
      LAYER M4 ;
        RECT  0 26.976 0.084 27 ;
    END
  END cfg_data[97]
  PIN cfg_data[98]
    DIRECTION INPUT ;
    USE SIGNAL ;
    PORT
      LAYER M4 ;
        RECT  0 27.216 0.084 27.24 ;
    END
  END cfg_data[98]
  PIN cfg_data[99]
    DIRECTION INPUT ;
    USE SIGNAL ;
    PORT
      LAYER M4 ;
        RECT  0 27.504 0.084 27.528 ;
    END
  END cfg_data[99]
  PIN cfg_data[9]
    DIRECTION INPUT ;
    USE SIGNAL ;
    PORT
      LAYER M4 ;
        RECT  0 4.416 0.084 4.44 ;
    END
  END cfg_data[9]
  PIN cfg_row[0]
    DIRECTION INPUT ;
    USE SIGNAL ;
    PORT
      LAYER M4 ;
        RECT  0 74.016 0.084 74.04 ;
    END
  END cfg_row[0]
  PIN cfg_row[1]
    DIRECTION INPUT ;
    USE SIGNAL ;
    PORT
      LAYER M4 ;
        RECT  0 74.256 0.084 74.28 ;
    END
  END cfg_row[1]
  PIN cfg_row[2]
    DIRECTION INPUT ;
    USE SIGNAL ;
    PORT
      LAYER M4 ;
        RECT  0 74.544 0.084 74.568 ;
    END
  END cfg_row[2]
  PIN cfg_row[3]
    DIRECTION INPUT ;
    USE SIGNAL ;
    PORT
      LAYER M4 ;
        RECT  0 74.784 0.084 74.808 ;
    END
  END cfg_row[3]
  PIN cfg_row[4]
    DIRECTION INPUT ;
    USE SIGNAL ;
    PORT
      LAYER M4 ;
        RECT  0 75.024 0.084 75.048 ;
    END
  END cfg_row[4]
  PIN cfg_row[5]
    DIRECTION INPUT ;
    USE SIGNAL ;
    PORT
      LAYER M4 ;
        RECT  0 75.312 0.084 75.336 ;
    END
  END cfg_row[5]
  PIN cfg_row[6]
    DIRECTION INPUT ;
    USE SIGNAL ;
    PORT
      LAYER M4 ;
        RECT  0 75.552 0.084 75.576 ;
    END
  END cfg_row[6]
  PIN cfg_we
    DIRECTION INPUT ;
    USE SIGNAL ;
    PORT
      LAYER M4 ;
        RECT  0 76.416 0.084 76.44 ;
    END
  END cfg_we
  PIN clk
    DIRECTION INPUT ;
    USE SIGNAL ;
    PORT
      LAYER M4 ;
        RECT  0 68.352 0.084 68.376 ;
    END
  END clk
  PIN fault
    DIRECTION OUTPUT ;
    USE SIGNAL ;
    PORT
      LAYER M4 ;
        RECT  86.316 83.616 86.4 83.64 ;
    END
  END fault
  PIN l_fault[0]
    DIRECTION INPUT ;
    USE SIGNAL ;
    PORT
      LAYER M4 ;
        RECT  0 78.528 0.084 78.552 ;
    END
  END l_fault[0]
  PIN l_fault[1]
    DIRECTION INPUT ;
    USE SIGNAL ;
    PORT
      LAYER M4 ;
        RECT  0 78.816 0.084 78.84 ;
    END
  END l_fault[1]
  PIN l_fault[2]
    DIRECTION INPUT ;
    USE SIGNAL ;
    PORT
      LAYER M4 ;
        RECT  0 79.056 0.084 79.08 ;
    END
  END l_fault[2]
  PIN l_fault[3]
    DIRECTION INPUT ;
    USE SIGNAL ;
    PORT
      LAYER M4 ;
        RECT  0 79.344 0.084 79.368 ;
    END
  END l_fault[3]
  PIN l_fault[4]
    DIRECTION INPUT ;
    USE SIGNAL ;
    PORT
      LAYER M4 ;
        RECT  0 79.584 0.084 79.608 ;
    END
  END l_fault[4]
  PIN l_fault[5]
    DIRECTION INPUT ;
    USE SIGNAL ;
    PORT
      LAYER M4 ;
        RECT  0 79.872 0.084 79.896 ;
    END
  END l_fault[5]
  PIN l_fault[6]
    DIRECTION INPUT ;
    USE SIGNAL ;
    PORT
      LAYER M4 ;
        RECT  0 80.16 0.084 80.184 ;
    END
  END l_fault[6]
  PIN l_fault[7]
    DIRECTION INPUT ;
    USE SIGNAL ;
    PORT
      LAYER M4 ;
        RECT  0 80.4 0.084 80.424 ;
    END
  END l_fault[7]
  PIN l_fault[8]
    DIRECTION INPUT ;
    USE SIGNAL ;
    PORT
      LAYER M4 ;
        RECT  0 80.688 0.084 80.712 ;
    END
  END l_fault[8]
  PIN l_fault[9]
    DIRECTION INPUT ;
    USE SIGNAL ;
    PORT
      LAYER M4 ;
        RECT  0 80.976 0.084 81 ;
    END
  END l_fault[9]
  PIN l_valid[0]
    DIRECTION INPUT ;
    USE SIGNAL ;
    PORT
      LAYER M4 ;
        RECT  0 81.504 0.084 81.528 ;
    END
  END l_valid[0]
  PIN l_valid[1]
    DIRECTION INPUT ;
    USE SIGNAL ;
    PORT
      LAYER M4 ;
        RECT  0 81.792 0.084 81.816 ;
    END
  END l_valid[1]
  PIN l_valid[2]
    DIRECTION INPUT ;
    USE SIGNAL ;
    PORT
      LAYER M4 ;
        RECT  0 82.08 0.084 82.104 ;
    END
  END l_valid[2]
  PIN l_valid[3]
    DIRECTION INPUT ;
    USE SIGNAL ;
    PORT
      LAYER M4 ;
        RECT  0 82.32 0.084 82.344 ;
    END
  END l_valid[3]
  PIN l_valid[4]
    DIRECTION INPUT ;
    USE SIGNAL ;
    PORT
      LAYER M4 ;
        RECT  0 82.608 0.084 82.632 ;
    END
  END l_valid[4]
  PIN l_valid[5]
    DIRECTION INPUT ;
    USE SIGNAL ;
    PORT
      LAYER M4 ;
        RECT  0 82.896 0.084 82.92 ;
    END
  END l_valid[5]
  PIN l_valid[6]
    DIRECTION INPUT ;
    USE SIGNAL ;
    PORT
      LAYER M4 ;
        RECT  0 83.136 0.084 83.16 ;
    END
  END l_valid[6]
  PIN l_valid[7]
    DIRECTION INPUT ;
    USE SIGNAL ;
    PORT
      LAYER M4 ;
        RECT  0 83.424 0.084 83.448 ;
    END
  END l_valid[7]
  PIN l_valid[8]
    DIRECTION INPUT ;
    USE SIGNAL ;
    PORT
      LAYER M4 ;
        RECT  0 83.664 0.084 83.688 ;
    END
  END l_valid[8]
  PIN l_valid[9]
    DIRECTION INPUT ;
    USE SIGNAL ;
    PORT
      LAYER M4 ;
        RECT  0 83.952 0.084 83.976 ;
    END
  END l_valid[9]
  PIN o_any
    DIRECTION OUTPUT ;
    USE SIGNAL ;
    PORT
      LAYER M4 ;
        RECT  86.316 79.44 86.4 79.464 ;
    END
  END o_any
  PIN o_bank[0]
    DIRECTION OUTPUT ;
    USE SIGNAL ;
    PORT
      LAYER M4 ;
        RECT  86.316 77.616 86.4 77.64 ;
    END
  END o_bank[0]
  PIN o_bank[1]
    DIRECTION OUTPUT ;
    USE SIGNAL ;
    PORT
      LAYER M4 ;
        RECT  86.316 77.856 86.4 77.88 ;
    END
  END o_bank[1]
  PIN o_bank[2]
    DIRECTION OUTPUT ;
    USE SIGNAL ;
    PORT
      LAYER M4 ;
        RECT  86.316 78.096 86.4 78.12 ;
    END
  END o_bank[2]
  PIN o_bank[3]
    DIRECTION OUTPUT ;
    USE SIGNAL ;
    PORT
      LAYER M4 ;
        RECT  86.316 78.336 86.4 78.36 ;
    END
  END o_bank[3]
  PIN o_bank[4]
    DIRECTION OUTPUT ;
    USE SIGNAL ;
    PORT
      LAYER M4 ;
        RECT  86.316 78.576 86.4 78.6 ;
    END
  END o_bank[4]
  PIN o_data[0]
    DIRECTION OUTPUT ;
    USE SIGNAL ;
    PORT
      LAYER M4 ;
        RECT  86.316 2.112 86.4 2.136 ;
    END
  END o_data[0]
  PIN o_data[100]
    DIRECTION OUTPUT ;
    USE SIGNAL ;
    PORT
      LAYER M4 ;
        RECT  86.316 30.672 86.4 30.696 ;
    END
  END o_data[100]
  PIN o_data[101]
    DIRECTION OUTPUT ;
    USE SIGNAL ;
    PORT
      LAYER M4 ;
        RECT  86.316 30.96 86.4 30.984 ;
    END
  END o_data[101]
  PIN o_data[102]
    DIRECTION OUTPUT ;
    USE SIGNAL ;
    PORT
      LAYER M4 ;
        RECT  86.316 31.248 86.4 31.272 ;
    END
  END o_data[102]
  PIN o_data[103]
    DIRECTION OUTPUT ;
    USE SIGNAL ;
    PORT
      LAYER M4 ;
        RECT  86.316 31.536 86.4 31.56 ;
    END
  END o_data[103]
  PIN o_data[104]
    DIRECTION OUTPUT ;
    USE SIGNAL ;
    PORT
      LAYER M4 ;
        RECT  86.316 31.824 86.4 31.848 ;
    END
  END o_data[104]
  PIN o_data[105]
    DIRECTION OUTPUT ;
    USE SIGNAL ;
    PORT
      LAYER M4 ;
        RECT  86.316 32.112 86.4 32.136 ;
    END
  END o_data[105]
  PIN o_data[106]
    DIRECTION OUTPUT ;
    USE SIGNAL ;
    PORT
      LAYER M4 ;
        RECT  86.316 32.4 86.4 32.424 ;
    END
  END o_data[106]
  PIN o_data[107]
    DIRECTION OUTPUT ;
    USE SIGNAL ;
    PORT
      LAYER M4 ;
        RECT  86.316 32.688 86.4 32.712 ;
    END
  END o_data[107]
  PIN o_data[108]
    DIRECTION OUTPUT ;
    USE SIGNAL ;
    PORT
      LAYER M4 ;
        RECT  86.316 32.976 86.4 33 ;
    END
  END o_data[108]
  PIN o_data[109]
    DIRECTION OUTPUT ;
    USE SIGNAL ;
    PORT
      LAYER M4 ;
        RECT  86.316 33.264 86.4 33.288 ;
    END
  END o_data[109]
  PIN o_data[10]
    DIRECTION OUTPUT ;
    USE SIGNAL ;
    PORT
      LAYER M4 ;
        RECT  86.316 4.992 86.4 5.016 ;
    END
  END o_data[10]
  PIN o_data[110]
    DIRECTION OUTPUT ;
    USE SIGNAL ;
    PORT
      LAYER M4 ;
        RECT  86.316 33.552 86.4 33.576 ;
    END
  END o_data[110]
  PIN o_data[111]
    DIRECTION OUTPUT ;
    USE SIGNAL ;
    PORT
      LAYER M4 ;
        RECT  86.316 33.84 86.4 33.864 ;
    END
  END o_data[111]
  PIN o_data[112]
    DIRECTION OUTPUT ;
    USE SIGNAL ;
    PORT
      LAYER M4 ;
        RECT  86.316 34.128 86.4 34.152 ;
    END
  END o_data[112]
  PIN o_data[113]
    DIRECTION OUTPUT ;
    USE SIGNAL ;
    PORT
      LAYER M4 ;
        RECT  86.316 34.416 86.4 34.44 ;
    END
  END o_data[113]
  PIN o_data[114]
    DIRECTION OUTPUT ;
    USE SIGNAL ;
    PORT
      LAYER M4 ;
        RECT  86.316 34.704 86.4 34.728 ;
    END
  END o_data[114]
  PIN o_data[115]
    DIRECTION OUTPUT ;
    USE SIGNAL ;
    PORT
      LAYER M4 ;
        RECT  86.316 34.992 86.4 35.016 ;
    END
  END o_data[115]
  PIN o_data[116]
    DIRECTION OUTPUT ;
    USE SIGNAL ;
    PORT
      LAYER M4 ;
        RECT  86.316 35.232 86.4 35.256 ;
    END
  END o_data[116]
  PIN o_data[117]
    DIRECTION OUTPUT ;
    USE SIGNAL ;
    PORT
      LAYER M4 ;
        RECT  86.316 35.52 86.4 35.544 ;
    END
  END o_data[117]
  PIN o_data[118]
    DIRECTION OUTPUT ;
    USE SIGNAL ;
    PORT
      LAYER M4 ;
        RECT  86.316 35.808 86.4 35.832 ;
    END
  END o_data[118]
  PIN o_data[119]
    DIRECTION OUTPUT ;
    USE SIGNAL ;
    PORT
      LAYER M4 ;
        RECT  86.316 36.096 86.4 36.12 ;
    END
  END o_data[119]
  PIN o_data[11]
    DIRECTION OUTPUT ;
    USE SIGNAL ;
    PORT
      LAYER M4 ;
        RECT  86.316 5.28 86.4 5.304 ;
    END
  END o_data[11]
  PIN o_data[120]
    DIRECTION OUTPUT ;
    USE SIGNAL ;
    PORT
      LAYER M4 ;
        RECT  86.316 36.384 86.4 36.408 ;
    END
  END o_data[120]
  PIN o_data[121]
    DIRECTION OUTPUT ;
    USE SIGNAL ;
    PORT
      LAYER M4 ;
        RECT  86.316 36.672 86.4 36.696 ;
    END
  END o_data[121]
  PIN o_data[122]
    DIRECTION OUTPUT ;
    USE SIGNAL ;
    PORT
      LAYER M4 ;
        RECT  86.316 36.96 86.4 36.984 ;
    END
  END o_data[122]
  PIN o_data[123]
    DIRECTION OUTPUT ;
    USE SIGNAL ;
    PORT
      LAYER M4 ;
        RECT  86.316 37.248 86.4 37.272 ;
    END
  END o_data[123]
  PIN o_data[124]
    DIRECTION OUTPUT ;
    USE SIGNAL ;
    PORT
      LAYER M4 ;
        RECT  86.316 37.536 86.4 37.56 ;
    END
  END o_data[124]
  PIN o_data[125]
    DIRECTION OUTPUT ;
    USE SIGNAL ;
    PORT
      LAYER M4 ;
        RECT  86.316 37.824 86.4 37.848 ;
    END
  END o_data[125]
  PIN o_data[126]
    DIRECTION OUTPUT ;
    USE SIGNAL ;
    PORT
      LAYER M4 ;
        RECT  86.316 38.112 86.4 38.136 ;
    END
  END o_data[126]
  PIN o_data[127]
    DIRECTION OUTPUT ;
    USE SIGNAL ;
    PORT
      LAYER M4 ;
        RECT  86.316 38.4 86.4 38.424 ;
    END
  END o_data[127]
  PIN o_data[128]
    DIRECTION OUTPUT ;
    USE SIGNAL ;
    PORT
      LAYER M4 ;
        RECT  86.316 38.688 86.4 38.712 ;
    END
  END o_data[128]
  PIN o_data[129]
    DIRECTION OUTPUT ;
    USE SIGNAL ;
    PORT
      LAYER M4 ;
        RECT  86.316 38.976 86.4 39 ;
    END
  END o_data[129]
  PIN o_data[12]
    DIRECTION OUTPUT ;
    USE SIGNAL ;
    PORT
      LAYER M4 ;
        RECT  86.316 5.568 86.4 5.592 ;
    END
  END o_data[12]
  PIN o_data[130]
    DIRECTION OUTPUT ;
    USE SIGNAL ;
    PORT
      LAYER M4 ;
        RECT  86.316 39.264 86.4 39.288 ;
    END
  END o_data[130]
  PIN o_data[131]
    DIRECTION OUTPUT ;
    USE SIGNAL ;
    PORT
      LAYER M4 ;
        RECT  86.316 39.552 86.4 39.576 ;
    END
  END o_data[131]
  PIN o_data[132]
    DIRECTION OUTPUT ;
    USE SIGNAL ;
    PORT
      LAYER M4 ;
        RECT  86.316 39.84 86.4 39.864 ;
    END
  END o_data[132]
  PIN o_data[133]
    DIRECTION OUTPUT ;
    USE SIGNAL ;
    PORT
      LAYER M4 ;
        RECT  86.316 40.128 86.4 40.152 ;
    END
  END o_data[133]
  PIN o_data[134]
    DIRECTION OUTPUT ;
    USE SIGNAL ;
    PORT
      LAYER M4 ;
        RECT  86.316 40.416 86.4 40.44 ;
    END
  END o_data[134]
  PIN o_data[135]
    DIRECTION OUTPUT ;
    USE SIGNAL ;
    PORT
      LAYER M4 ;
        RECT  86.316 40.704 86.4 40.728 ;
    END
  END o_data[135]
  PIN o_data[136]
    DIRECTION OUTPUT ;
    USE SIGNAL ;
    PORT
      LAYER M4 ;
        RECT  86.316 40.944 86.4 40.968 ;
    END
  END o_data[136]
  PIN o_data[137]
    DIRECTION OUTPUT ;
    USE SIGNAL ;
    PORT
      LAYER M4 ;
        RECT  86.316 41.232 86.4 41.256 ;
    END
  END o_data[137]
  PIN o_data[138]
    DIRECTION OUTPUT ;
    USE SIGNAL ;
    PORT
      LAYER M4 ;
        RECT  86.316 41.52 86.4 41.544 ;
    END
  END o_data[138]
  PIN o_data[139]
    DIRECTION OUTPUT ;
    USE SIGNAL ;
    PORT
      LAYER M4 ;
        RECT  86.316 41.808 86.4 41.832 ;
    END
  END o_data[139]
  PIN o_data[13]
    DIRECTION OUTPUT ;
    USE SIGNAL ;
    PORT
      LAYER M4 ;
        RECT  86.316 5.856 86.4 5.88 ;
    END
  END o_data[13]
  PIN o_data[140]
    DIRECTION OUTPUT ;
    USE SIGNAL ;
    PORT
      LAYER M4 ;
        RECT  86.316 42.096 86.4 42.12 ;
    END
  END o_data[140]
  PIN o_data[141]
    DIRECTION OUTPUT ;
    USE SIGNAL ;
    PORT
      LAYER M4 ;
        RECT  86.316 42.384 86.4 42.408 ;
    END
  END o_data[141]
  PIN o_data[142]
    DIRECTION OUTPUT ;
    USE SIGNAL ;
    PORT
      LAYER M4 ;
        RECT  86.316 42.672 86.4 42.696 ;
    END
  END o_data[142]
  PIN o_data[143]
    DIRECTION OUTPUT ;
    USE SIGNAL ;
    PORT
      LAYER M4 ;
        RECT  86.316 42.96 86.4 42.984 ;
    END
  END o_data[143]
  PIN o_data[144]
    DIRECTION OUTPUT ;
    USE SIGNAL ;
    PORT
      LAYER M4 ;
        RECT  86.316 43.248 86.4 43.272 ;
    END
  END o_data[144]
  PIN o_data[145]
    DIRECTION OUTPUT ;
    USE SIGNAL ;
    PORT
      LAYER M4 ;
        RECT  86.316 43.536 86.4 43.56 ;
    END
  END o_data[145]
  PIN o_data[146]
    DIRECTION OUTPUT ;
    USE SIGNAL ;
    PORT
      LAYER M4 ;
        RECT  86.316 43.824 86.4 43.848 ;
    END
  END o_data[146]
  PIN o_data[147]
    DIRECTION OUTPUT ;
    USE SIGNAL ;
    PORT
      LAYER M4 ;
        RECT  86.316 44.112 86.4 44.136 ;
    END
  END o_data[147]
  PIN o_data[148]
    DIRECTION OUTPUT ;
    USE SIGNAL ;
    PORT
      LAYER M4 ;
        RECT  86.316 44.4 86.4 44.424 ;
    END
  END o_data[148]
  PIN o_data[149]
    DIRECTION OUTPUT ;
    USE SIGNAL ;
    PORT
      LAYER M4 ;
        RECT  86.316 44.688 86.4 44.712 ;
    END
  END o_data[149]
  PIN o_data[14]
    DIRECTION OUTPUT ;
    USE SIGNAL ;
    PORT
      LAYER M4 ;
        RECT  86.316 6.144 86.4 6.168 ;
    END
  END o_data[14]
  PIN o_data[150]
    DIRECTION OUTPUT ;
    USE SIGNAL ;
    PORT
      LAYER M4 ;
        RECT  86.316 44.976 86.4 45 ;
    END
  END o_data[150]
  PIN o_data[151]
    DIRECTION OUTPUT ;
    USE SIGNAL ;
    PORT
      LAYER M4 ;
        RECT  86.316 45.264 86.4 45.288 ;
    END
  END o_data[151]
  PIN o_data[152]
    DIRECTION OUTPUT ;
    USE SIGNAL ;
    PORT
      LAYER M4 ;
        RECT  86.316 45.552 86.4 45.576 ;
    END
  END o_data[152]
  PIN o_data[153]
    DIRECTION OUTPUT ;
    USE SIGNAL ;
    PORT
      LAYER M4 ;
        RECT  86.316 45.84 86.4 45.864 ;
    END
  END o_data[153]
  PIN o_data[154]
    DIRECTION OUTPUT ;
    USE SIGNAL ;
    PORT
      LAYER M4 ;
        RECT  86.316 46.128 86.4 46.152 ;
    END
  END o_data[154]
  PIN o_data[155]
    DIRECTION OUTPUT ;
    USE SIGNAL ;
    PORT
      LAYER M4 ;
        RECT  86.316 46.368 86.4 46.392 ;
    END
  END o_data[155]
  PIN o_data[156]
    DIRECTION OUTPUT ;
    USE SIGNAL ;
    PORT
      LAYER M4 ;
        RECT  86.316 46.656 86.4 46.68 ;
    END
  END o_data[156]
  PIN o_data[157]
    DIRECTION OUTPUT ;
    USE SIGNAL ;
    PORT
      LAYER M4 ;
        RECT  86.316 46.944 86.4 46.968 ;
    END
  END o_data[157]
  PIN o_data[158]
    DIRECTION OUTPUT ;
    USE SIGNAL ;
    PORT
      LAYER M4 ;
        RECT  86.316 47.232 86.4 47.256 ;
    END
  END o_data[158]
  PIN o_data[159]
    DIRECTION OUTPUT ;
    USE SIGNAL ;
    PORT
      LAYER M4 ;
        RECT  86.316 47.52 86.4 47.544 ;
    END
  END o_data[159]
  PIN o_data[15]
    DIRECTION OUTPUT ;
    USE SIGNAL ;
    PORT
      LAYER M4 ;
        RECT  86.316 6.432 86.4 6.456 ;
    END
  END o_data[15]
  PIN o_data[160]
    DIRECTION OUTPUT ;
    USE SIGNAL ;
    PORT
      LAYER M4 ;
        RECT  86.316 47.808 86.4 47.832 ;
    END
  END o_data[160]
  PIN o_data[161]
    DIRECTION OUTPUT ;
    USE SIGNAL ;
    PORT
      LAYER M4 ;
        RECT  86.316 48.096 86.4 48.12 ;
    END
  END o_data[161]
  PIN o_data[162]
    DIRECTION OUTPUT ;
    USE SIGNAL ;
    PORT
      LAYER M4 ;
        RECT  86.316 48.384 86.4 48.408 ;
    END
  END o_data[162]
  PIN o_data[163]
    DIRECTION OUTPUT ;
    USE SIGNAL ;
    PORT
      LAYER M4 ;
        RECT  86.316 48.672 86.4 48.696 ;
    END
  END o_data[163]
  PIN o_data[164]
    DIRECTION OUTPUT ;
    USE SIGNAL ;
    PORT
      LAYER M4 ;
        RECT  86.316 48.96 86.4 48.984 ;
    END
  END o_data[164]
  PIN o_data[165]
    DIRECTION OUTPUT ;
    USE SIGNAL ;
    PORT
      LAYER M4 ;
        RECT  86.316 49.248 86.4 49.272 ;
    END
  END o_data[165]
  PIN o_data[166]
    DIRECTION OUTPUT ;
    USE SIGNAL ;
    PORT
      LAYER M4 ;
        RECT  86.316 49.536 86.4 49.56 ;
    END
  END o_data[166]
  PIN o_data[167]
    DIRECTION OUTPUT ;
    USE SIGNAL ;
    PORT
      LAYER M4 ;
        RECT  86.316 49.824 86.4 49.848 ;
    END
  END o_data[167]
  PIN o_data[168]
    DIRECTION OUTPUT ;
    USE SIGNAL ;
    PORT
      LAYER M4 ;
        RECT  86.316 50.112 86.4 50.136 ;
    END
  END o_data[168]
  PIN o_data[169]
    DIRECTION OUTPUT ;
    USE SIGNAL ;
    PORT
      LAYER M4 ;
        RECT  86.316 50.4 86.4 50.424 ;
    END
  END o_data[169]
  PIN o_data[16]
    DIRECTION OUTPUT ;
    USE SIGNAL ;
    PORT
      LAYER M4 ;
        RECT  86.316 6.72 86.4 6.744 ;
    END
  END o_data[16]
  PIN o_data[170]
    DIRECTION OUTPUT ;
    USE SIGNAL ;
    PORT
      LAYER M4 ;
        RECT  86.316 50.688 86.4 50.712 ;
    END
  END o_data[170]
  PIN o_data[171]
    DIRECTION OUTPUT ;
    USE SIGNAL ;
    PORT
      LAYER M4 ;
        RECT  86.316 50.976 86.4 51 ;
    END
  END o_data[171]
  PIN o_data[172]
    DIRECTION OUTPUT ;
    USE SIGNAL ;
    PORT
      LAYER M4 ;
        RECT  86.316 51.264 86.4 51.288 ;
    END
  END o_data[172]
  PIN o_data[173]
    DIRECTION OUTPUT ;
    USE SIGNAL ;
    PORT
      LAYER M4 ;
        RECT  86.316 51.552 86.4 51.576 ;
    END
  END o_data[173]
  PIN o_data[174]
    DIRECTION OUTPUT ;
    USE SIGNAL ;
    PORT
      LAYER M4 ;
        RECT  86.316 51.84 86.4 51.864 ;
    END
  END o_data[174]
  PIN o_data[175]
    DIRECTION OUTPUT ;
    USE SIGNAL ;
    PORT
      LAYER M4 ;
        RECT  86.316 52.08 86.4 52.104 ;
    END
  END o_data[175]
  PIN o_data[176]
    DIRECTION OUTPUT ;
    USE SIGNAL ;
    PORT
      LAYER M4 ;
        RECT  86.316 52.368 86.4 52.392 ;
    END
  END o_data[176]
  PIN o_data[177]
    DIRECTION OUTPUT ;
    USE SIGNAL ;
    PORT
      LAYER M4 ;
        RECT  86.316 52.656 86.4 52.68 ;
    END
  END o_data[177]
  PIN o_data[178]
    DIRECTION OUTPUT ;
    USE SIGNAL ;
    PORT
      LAYER M4 ;
        RECT  86.316 52.944 86.4 52.968 ;
    END
  END o_data[178]
  PIN o_data[179]
    DIRECTION OUTPUT ;
    USE SIGNAL ;
    PORT
      LAYER M4 ;
        RECT  86.316 53.232 86.4 53.256 ;
    END
  END o_data[179]
  PIN o_data[17]
    DIRECTION OUTPUT ;
    USE SIGNAL ;
    PORT
      LAYER M4 ;
        RECT  86.316 7.008 86.4 7.032 ;
    END
  END o_data[17]
  PIN o_data[180]
    DIRECTION OUTPUT ;
    USE SIGNAL ;
    PORT
      LAYER M4 ;
        RECT  86.316 53.52 86.4 53.544 ;
    END
  END o_data[180]
  PIN o_data[181]
    DIRECTION OUTPUT ;
    USE SIGNAL ;
    PORT
      LAYER M4 ;
        RECT  86.316 53.808 86.4 53.832 ;
    END
  END o_data[181]
  PIN o_data[182]
    DIRECTION OUTPUT ;
    USE SIGNAL ;
    PORT
      LAYER M4 ;
        RECT  86.316 54.096 86.4 54.12 ;
    END
  END o_data[182]
  PIN o_data[183]
    DIRECTION OUTPUT ;
    USE SIGNAL ;
    PORT
      LAYER M4 ;
        RECT  86.316 54.384 86.4 54.408 ;
    END
  END o_data[183]
  PIN o_data[184]
    DIRECTION OUTPUT ;
    USE SIGNAL ;
    PORT
      LAYER M4 ;
        RECT  86.316 54.672 86.4 54.696 ;
    END
  END o_data[184]
  PIN o_data[185]
    DIRECTION OUTPUT ;
    USE SIGNAL ;
    PORT
      LAYER M4 ;
        RECT  86.316 54.96 86.4 54.984 ;
    END
  END o_data[185]
  PIN o_data[186]
    DIRECTION OUTPUT ;
    USE SIGNAL ;
    PORT
      LAYER M4 ;
        RECT  86.316 55.248 86.4 55.272 ;
    END
  END o_data[186]
  PIN o_data[187]
    DIRECTION OUTPUT ;
    USE SIGNAL ;
    PORT
      LAYER M4 ;
        RECT  86.316 55.536 86.4 55.56 ;
    END
  END o_data[187]
  PIN o_data[188]
    DIRECTION OUTPUT ;
    USE SIGNAL ;
    PORT
      LAYER M4 ;
        RECT  86.316 55.824 86.4 55.848 ;
    END
  END o_data[188]
  PIN o_data[189]
    DIRECTION OUTPUT ;
    USE SIGNAL ;
    PORT
      LAYER M4 ;
        RECT  86.316 56.112 86.4 56.136 ;
    END
  END o_data[189]
  PIN o_data[18]
    DIRECTION OUTPUT ;
    USE SIGNAL ;
    PORT
      LAYER M4 ;
        RECT  86.316 7.248 86.4 7.272 ;
    END
  END o_data[18]
  PIN o_data[190]
    DIRECTION OUTPUT ;
    USE SIGNAL ;
    PORT
      LAYER M4 ;
        RECT  86.316 56.4 86.4 56.424 ;
    END
  END o_data[190]
  PIN o_data[191]
    DIRECTION OUTPUT ;
    USE SIGNAL ;
    PORT
      LAYER M4 ;
        RECT  86.316 56.688 86.4 56.712 ;
    END
  END o_data[191]
  PIN o_data[192]
    DIRECTION OUTPUT ;
    USE SIGNAL ;
    PORT
      LAYER M4 ;
        RECT  86.316 56.976 86.4 57 ;
    END
  END o_data[192]
  PIN o_data[193]
    DIRECTION OUTPUT ;
    USE SIGNAL ;
    PORT
      LAYER M4 ;
        RECT  86.316 57.264 86.4 57.288 ;
    END
  END o_data[193]
  PIN o_data[194]
    DIRECTION OUTPUT ;
    USE SIGNAL ;
    PORT
      LAYER M4 ;
        RECT  86.316 57.504 86.4 57.528 ;
    END
  END o_data[194]
  PIN o_data[195]
    DIRECTION OUTPUT ;
    USE SIGNAL ;
    PORT
      LAYER M4 ;
        RECT  86.316 57.792 86.4 57.816 ;
    END
  END o_data[195]
  PIN o_data[196]
    DIRECTION OUTPUT ;
    USE SIGNAL ;
    PORT
      LAYER M4 ;
        RECT  86.316 58.08 86.4 58.104 ;
    END
  END o_data[196]
  PIN o_data[197]
    DIRECTION OUTPUT ;
    USE SIGNAL ;
    PORT
      LAYER M4 ;
        RECT  86.316 58.368 86.4 58.392 ;
    END
  END o_data[197]
  PIN o_data[198]
    DIRECTION OUTPUT ;
    USE SIGNAL ;
    PORT
      LAYER M4 ;
        RECT  86.316 58.656 86.4 58.68 ;
    END
  END o_data[198]
  PIN o_data[199]
    DIRECTION OUTPUT ;
    USE SIGNAL ;
    PORT
      LAYER M4 ;
        RECT  86.316 58.944 86.4 58.968 ;
    END
  END o_data[199]
  PIN o_data[19]
    DIRECTION OUTPUT ;
    USE SIGNAL ;
    PORT
      LAYER M4 ;
        RECT  86.316 7.536 86.4 7.56 ;
    END
  END o_data[19]
  PIN o_data[1]
    DIRECTION OUTPUT ;
    USE SIGNAL ;
    PORT
      LAYER M4 ;
        RECT  86.316 2.4 86.4 2.424 ;
    END
  END o_data[1]
  PIN o_data[200]
    DIRECTION OUTPUT ;
    USE SIGNAL ;
    PORT
      LAYER M4 ;
        RECT  86.316 59.232 86.4 59.256 ;
    END
  END o_data[200]
  PIN o_data[201]
    DIRECTION OUTPUT ;
    USE SIGNAL ;
    PORT
      LAYER M4 ;
        RECT  86.316 59.52 86.4 59.544 ;
    END
  END o_data[201]
  PIN o_data[202]
    DIRECTION OUTPUT ;
    USE SIGNAL ;
    PORT
      LAYER M4 ;
        RECT  86.316 59.808 86.4 59.832 ;
    END
  END o_data[202]
  PIN o_data[203]
    DIRECTION OUTPUT ;
    USE SIGNAL ;
    PORT
      LAYER M4 ;
        RECT  86.316 60.096 86.4 60.12 ;
    END
  END o_data[203]
  PIN o_data[204]
    DIRECTION OUTPUT ;
    USE SIGNAL ;
    PORT
      LAYER M4 ;
        RECT  86.316 60.384 86.4 60.408 ;
    END
  END o_data[204]
  PIN o_data[205]
    DIRECTION OUTPUT ;
    USE SIGNAL ;
    PORT
      LAYER M4 ;
        RECT  86.316 60.672 86.4 60.696 ;
    END
  END o_data[205]
  PIN o_data[206]
    DIRECTION OUTPUT ;
    USE SIGNAL ;
    PORT
      LAYER M4 ;
        RECT  86.316 60.96 86.4 60.984 ;
    END
  END o_data[206]
  PIN o_data[207]
    DIRECTION OUTPUT ;
    USE SIGNAL ;
    PORT
      LAYER M4 ;
        RECT  86.316 61.248 86.4 61.272 ;
    END
  END o_data[207]
  PIN o_data[208]
    DIRECTION OUTPUT ;
    USE SIGNAL ;
    PORT
      LAYER M4 ;
        RECT  86.316 61.536 86.4 61.56 ;
    END
  END o_data[208]
  PIN o_data[209]
    DIRECTION OUTPUT ;
    USE SIGNAL ;
    PORT
      LAYER M4 ;
        RECT  86.316 61.824 86.4 61.848 ;
    END
  END o_data[209]
  PIN o_data[20]
    DIRECTION OUTPUT ;
    USE SIGNAL ;
    PORT
      LAYER M4 ;
        RECT  86.316 7.824 86.4 7.848 ;
    END
  END o_data[20]
  PIN o_data[210]
    DIRECTION OUTPUT ;
    USE SIGNAL ;
    PORT
      LAYER M4 ;
        RECT  86.316 62.112 86.4 62.136 ;
    END
  END o_data[210]
  PIN o_data[211]
    DIRECTION OUTPUT ;
    USE SIGNAL ;
    PORT
      LAYER M4 ;
        RECT  86.316 62.4 86.4 62.424 ;
    END
  END o_data[211]
  PIN o_data[212]
    DIRECTION OUTPUT ;
    USE SIGNAL ;
    PORT
      LAYER M4 ;
        RECT  86.316 62.688 86.4 62.712 ;
    END
  END o_data[212]
  PIN o_data[213]
    DIRECTION OUTPUT ;
    USE SIGNAL ;
    PORT
      LAYER M4 ;
        RECT  86.316 62.976 86.4 63 ;
    END
  END o_data[213]
  PIN o_data[214]
    DIRECTION OUTPUT ;
    USE SIGNAL ;
    PORT
      LAYER M4 ;
        RECT  86.316 63.216 86.4 63.24 ;
    END
  END o_data[214]
  PIN o_data[215]
    DIRECTION OUTPUT ;
    USE SIGNAL ;
    PORT
      LAYER M4 ;
        RECT  86.316 63.504 86.4 63.528 ;
    END
  END o_data[215]
  PIN o_data[216]
    DIRECTION OUTPUT ;
    USE SIGNAL ;
    PORT
      LAYER M4 ;
        RECT  86.316 63.792 86.4 63.816 ;
    END
  END o_data[216]
  PIN o_data[217]
    DIRECTION OUTPUT ;
    USE SIGNAL ;
    PORT
      LAYER M4 ;
        RECT  86.316 64.08 86.4 64.104 ;
    END
  END o_data[217]
  PIN o_data[218]
    DIRECTION OUTPUT ;
    USE SIGNAL ;
    PORT
      LAYER M4 ;
        RECT  86.316 64.368 86.4 64.392 ;
    END
  END o_data[218]
  PIN o_data[219]
    DIRECTION OUTPUT ;
    USE SIGNAL ;
    PORT
      LAYER M4 ;
        RECT  86.316 64.656 86.4 64.68 ;
    END
  END o_data[219]
  PIN o_data[21]
    DIRECTION OUTPUT ;
    USE SIGNAL ;
    PORT
      LAYER M4 ;
        RECT  86.316 8.112 86.4 8.136 ;
    END
  END o_data[21]
  PIN o_data[220]
    DIRECTION OUTPUT ;
    USE SIGNAL ;
    PORT
      LAYER M4 ;
        RECT  86.316 64.944 86.4 64.968 ;
    END
  END o_data[220]
  PIN o_data[221]
    DIRECTION OUTPUT ;
    USE SIGNAL ;
    PORT
      LAYER M4 ;
        RECT  86.316 65.232 86.4 65.256 ;
    END
  END o_data[221]
  PIN o_data[222]
    DIRECTION OUTPUT ;
    USE SIGNAL ;
    PORT
      LAYER M4 ;
        RECT  86.316 65.52 86.4 65.544 ;
    END
  END o_data[222]
  PIN o_data[223]
    DIRECTION OUTPUT ;
    USE SIGNAL ;
    PORT
      LAYER M4 ;
        RECT  86.316 65.808 86.4 65.832 ;
    END
  END o_data[223]
  PIN o_data[224]
    DIRECTION OUTPUT ;
    USE SIGNAL ;
    PORT
      LAYER M4 ;
        RECT  86.316 66.096 86.4 66.12 ;
    END
  END o_data[224]
  PIN o_data[225]
    DIRECTION OUTPUT ;
    USE SIGNAL ;
    PORT
      LAYER M4 ;
        RECT  86.316 66.384 86.4 66.408 ;
    END
  END o_data[225]
  PIN o_data[226]
    DIRECTION OUTPUT ;
    USE SIGNAL ;
    PORT
      LAYER M4 ;
        RECT  86.316 66.672 86.4 66.696 ;
    END
  END o_data[226]
  PIN o_data[227]
    DIRECTION OUTPUT ;
    USE SIGNAL ;
    PORT
      LAYER M4 ;
        RECT  86.316 66.96 86.4 66.984 ;
    END
  END o_data[227]
  PIN o_data[228]
    DIRECTION OUTPUT ;
    USE SIGNAL ;
    PORT
      LAYER M4 ;
        RECT  86.316 67.248 86.4 67.272 ;
    END
  END o_data[228]
  PIN o_data[229]
    DIRECTION OUTPUT ;
    USE SIGNAL ;
    PORT
      LAYER M4 ;
        RECT  86.316 67.536 86.4 67.56 ;
    END
  END o_data[229]
  PIN o_data[22]
    DIRECTION OUTPUT ;
    USE SIGNAL ;
    PORT
      LAYER M4 ;
        RECT  86.316 8.4 86.4 8.424 ;
    END
  END o_data[22]
  PIN o_data[230]
    DIRECTION OUTPUT ;
    USE SIGNAL ;
    PORT
      LAYER M4 ;
        RECT  86.316 67.824 86.4 67.848 ;
    END
  END o_data[230]
  PIN o_data[231]
    DIRECTION OUTPUT ;
    USE SIGNAL ;
    PORT
      LAYER M4 ;
        RECT  86.316 68.112 86.4 68.136 ;
    END
  END o_data[231]
  PIN o_data[232]
    DIRECTION OUTPUT ;
    USE SIGNAL ;
    PORT
      LAYER M4 ;
        RECT  86.316 68.4 86.4 68.424 ;
    END
  END o_data[232]
  PIN o_data[233]
    DIRECTION OUTPUT ;
    USE SIGNAL ;
    PORT
      LAYER M4 ;
        RECT  86.316 68.64 86.4 68.664 ;
    END
  END o_data[233]
  PIN o_data[234]
    DIRECTION OUTPUT ;
    USE SIGNAL ;
    PORT
      LAYER M4 ;
        RECT  86.316 68.928 86.4 68.952 ;
    END
  END o_data[234]
  PIN o_data[235]
    DIRECTION OUTPUT ;
    USE SIGNAL ;
    PORT
      LAYER M4 ;
        RECT  86.316 69.216 86.4 69.24 ;
    END
  END o_data[235]
  PIN o_data[236]
    DIRECTION OUTPUT ;
    USE SIGNAL ;
    PORT
      LAYER M4 ;
        RECT  86.316 69.504 86.4 69.528 ;
    END
  END o_data[236]
  PIN o_data[237]
    DIRECTION OUTPUT ;
    USE SIGNAL ;
    PORT
      LAYER M4 ;
        RECT  86.316 69.792 86.4 69.816 ;
    END
  END o_data[237]
  PIN o_data[238]
    DIRECTION OUTPUT ;
    USE SIGNAL ;
    PORT
      LAYER M4 ;
        RECT  86.316 70.08 86.4 70.104 ;
    END
  END o_data[238]
  PIN o_data[239]
    DIRECTION OUTPUT ;
    USE SIGNAL ;
    PORT
      LAYER M4 ;
        RECT  86.316 70.368 86.4 70.392 ;
    END
  END o_data[239]
  PIN o_data[23]
    DIRECTION OUTPUT ;
    USE SIGNAL ;
    PORT
      LAYER M4 ;
        RECT  86.316 8.688 86.4 8.712 ;
    END
  END o_data[23]
  PIN o_data[240]
    DIRECTION OUTPUT ;
    USE SIGNAL ;
    PORT
      LAYER M4 ;
        RECT  86.316 70.656 86.4 70.68 ;
    END
  END o_data[240]
  PIN o_data[241]
    DIRECTION OUTPUT ;
    USE SIGNAL ;
    PORT
      LAYER M4 ;
        RECT  86.316 70.944 86.4 70.968 ;
    END
  END o_data[241]
  PIN o_data[242]
    DIRECTION OUTPUT ;
    USE SIGNAL ;
    PORT
      LAYER M4 ;
        RECT  86.316 71.232 86.4 71.256 ;
    END
  END o_data[242]
  PIN o_data[243]
    DIRECTION OUTPUT ;
    USE SIGNAL ;
    PORT
      LAYER M4 ;
        RECT  86.316 71.52 86.4 71.544 ;
    END
  END o_data[243]
  PIN o_data[244]
    DIRECTION OUTPUT ;
    USE SIGNAL ;
    PORT
      LAYER M4 ;
        RECT  86.316 71.808 86.4 71.832 ;
    END
  END o_data[244]
  PIN o_data[245]
    DIRECTION OUTPUT ;
    USE SIGNAL ;
    PORT
      LAYER M4 ;
        RECT  86.316 72.096 86.4 72.12 ;
    END
  END o_data[245]
  PIN o_data[246]
    DIRECTION OUTPUT ;
    USE SIGNAL ;
    PORT
      LAYER M4 ;
        RECT  86.316 72.384 86.4 72.408 ;
    END
  END o_data[246]
  PIN o_data[247]
    DIRECTION OUTPUT ;
    USE SIGNAL ;
    PORT
      LAYER M4 ;
        RECT  86.316 72.672 86.4 72.696 ;
    END
  END o_data[247]
  PIN o_data[248]
    DIRECTION OUTPUT ;
    USE SIGNAL ;
    PORT
      LAYER M4 ;
        RECT  86.316 72.96 86.4 72.984 ;
    END
  END o_data[248]
  PIN o_data[249]
    DIRECTION OUTPUT ;
    USE SIGNAL ;
    PORT
      LAYER M4 ;
        RECT  86.316 73.248 86.4 73.272 ;
    END
  END o_data[249]
  PIN o_data[24]
    DIRECTION OUTPUT ;
    USE SIGNAL ;
    PORT
      LAYER M4 ;
        RECT  86.316 8.976 86.4 9 ;
    END
  END o_data[24]
  PIN o_data[250]
    DIRECTION OUTPUT ;
    USE SIGNAL ;
    PORT
      LAYER M4 ;
        RECT  86.316 73.536 86.4 73.56 ;
    END
  END o_data[250]
  PIN o_data[251]
    DIRECTION OUTPUT ;
    USE SIGNAL ;
    PORT
      LAYER M4 ;
        RECT  86.316 73.824 86.4 73.848 ;
    END
  END o_data[251]
  PIN o_data[252]
    DIRECTION OUTPUT ;
    USE SIGNAL ;
    PORT
      LAYER M4 ;
        RECT  86.316 74.112 86.4 74.136 ;
    END
  END o_data[252]
  PIN o_data[253]
    DIRECTION OUTPUT ;
    USE SIGNAL ;
    PORT
      LAYER M4 ;
        RECT  86.316 74.352 86.4 74.376 ;
    END
  END o_data[253]
  PIN o_data[254]
    DIRECTION OUTPUT ;
    USE SIGNAL ;
    PORT
      LAYER M4 ;
        RECT  86.316 74.64 86.4 74.664 ;
    END
  END o_data[254]
  PIN o_data[255]
    DIRECTION OUTPUT ;
    USE SIGNAL ;
    PORT
      LAYER M4 ;
        RECT  86.316 74.928 86.4 74.952 ;
    END
  END o_data[255]
  PIN o_data[25]
    DIRECTION OUTPUT ;
    USE SIGNAL ;
    PORT
      LAYER M4 ;
        RECT  86.316 9.264 86.4 9.288 ;
    END
  END o_data[25]
  PIN o_data[26]
    DIRECTION OUTPUT ;
    USE SIGNAL ;
    PORT
      LAYER M4 ;
        RECT  86.316 9.552 86.4 9.576 ;
    END
  END o_data[26]
  PIN o_data[27]
    DIRECTION OUTPUT ;
    USE SIGNAL ;
    PORT
      LAYER M4 ;
        RECT  86.316 9.84 86.4 9.864 ;
    END
  END o_data[27]
  PIN o_data[28]
    DIRECTION OUTPUT ;
    USE SIGNAL ;
    PORT
      LAYER M4 ;
        RECT  86.316 10.128 86.4 10.152 ;
    END
  END o_data[28]
  PIN o_data[29]
    DIRECTION OUTPUT ;
    USE SIGNAL ;
    PORT
      LAYER M4 ;
        RECT  86.316 10.416 86.4 10.44 ;
    END
  END o_data[29]
  PIN o_data[2]
    DIRECTION OUTPUT ;
    USE SIGNAL ;
    PORT
      LAYER M4 ;
        RECT  86.316 2.688 86.4 2.712 ;
    END
  END o_data[2]
  PIN o_data[30]
    DIRECTION OUTPUT ;
    USE SIGNAL ;
    PORT
      LAYER M4 ;
        RECT  86.316 10.704 86.4 10.728 ;
    END
  END o_data[30]
  PIN o_data[31]
    DIRECTION OUTPUT ;
    USE SIGNAL ;
    PORT
      LAYER M4 ;
        RECT  86.316 10.992 86.4 11.016 ;
    END
  END o_data[31]
  PIN o_data[32]
    DIRECTION OUTPUT ;
    USE SIGNAL ;
    PORT
      LAYER M4 ;
        RECT  86.316 11.28 86.4 11.304 ;
    END
  END o_data[32]
  PIN o_data[33]
    DIRECTION OUTPUT ;
    USE SIGNAL ;
    PORT
      LAYER M4 ;
        RECT  86.316 11.568 86.4 11.592 ;
    END
  END o_data[33]
  PIN o_data[34]
    DIRECTION OUTPUT ;
    USE SIGNAL ;
    PORT
      LAYER M4 ;
        RECT  86.316 11.856 86.4 11.88 ;
    END
  END o_data[34]
  PIN o_data[35]
    DIRECTION OUTPUT ;
    USE SIGNAL ;
    PORT
      LAYER M4 ;
        RECT  86.316 12.144 86.4 12.168 ;
    END
  END o_data[35]
  PIN o_data[36]
    DIRECTION OUTPUT ;
    USE SIGNAL ;
    PORT
      LAYER M4 ;
        RECT  86.316 12.432 86.4 12.456 ;
    END
  END o_data[36]
  PIN o_data[37]
    DIRECTION OUTPUT ;
    USE SIGNAL ;
    PORT
      LAYER M4 ;
        RECT  86.316 12.72 86.4 12.744 ;
    END
  END o_data[37]
  PIN o_data[38]
    DIRECTION OUTPUT ;
    USE SIGNAL ;
    PORT
      LAYER M4 ;
        RECT  86.316 12.96 86.4 12.984 ;
    END
  END o_data[38]
  PIN o_data[39]
    DIRECTION OUTPUT ;
    USE SIGNAL ;
    PORT
      LAYER M4 ;
        RECT  86.316 13.248 86.4 13.272 ;
    END
  END o_data[39]
  PIN o_data[3]
    DIRECTION OUTPUT ;
    USE SIGNAL ;
    PORT
      LAYER M4 ;
        RECT  86.316 2.976 86.4 3 ;
    END
  END o_data[3]
  PIN o_data[40]
    DIRECTION OUTPUT ;
    USE SIGNAL ;
    PORT
      LAYER M4 ;
        RECT  86.316 13.536 86.4 13.56 ;
    END
  END o_data[40]
  PIN o_data[41]
    DIRECTION OUTPUT ;
    USE SIGNAL ;
    PORT
      LAYER M4 ;
        RECT  86.316 13.824 86.4 13.848 ;
    END
  END o_data[41]
  PIN o_data[42]
    DIRECTION OUTPUT ;
    USE SIGNAL ;
    PORT
      LAYER M4 ;
        RECT  86.316 14.112 86.4 14.136 ;
    END
  END o_data[42]
  PIN o_data[43]
    DIRECTION OUTPUT ;
    USE SIGNAL ;
    PORT
      LAYER M4 ;
        RECT  86.316 14.4 86.4 14.424 ;
    END
  END o_data[43]
  PIN o_data[44]
    DIRECTION OUTPUT ;
    USE SIGNAL ;
    PORT
      LAYER M4 ;
        RECT  86.316 14.688 86.4 14.712 ;
    END
  END o_data[44]
  PIN o_data[45]
    DIRECTION OUTPUT ;
    USE SIGNAL ;
    PORT
      LAYER M4 ;
        RECT  86.316 14.976 86.4 15 ;
    END
  END o_data[45]
  PIN o_data[46]
    DIRECTION OUTPUT ;
    USE SIGNAL ;
    PORT
      LAYER M4 ;
        RECT  86.316 15.264 86.4 15.288 ;
    END
  END o_data[46]
  PIN o_data[47]
    DIRECTION OUTPUT ;
    USE SIGNAL ;
    PORT
      LAYER M4 ;
        RECT  86.316 15.552 86.4 15.576 ;
    END
  END o_data[47]
  PIN o_data[48]
    DIRECTION OUTPUT ;
    USE SIGNAL ;
    PORT
      LAYER M4 ;
        RECT  86.316 15.84 86.4 15.864 ;
    END
  END o_data[48]
  PIN o_data[49]
    DIRECTION OUTPUT ;
    USE SIGNAL ;
    PORT
      LAYER M4 ;
        RECT  86.316 16.128 86.4 16.152 ;
    END
  END o_data[49]
  PIN o_data[4]
    DIRECTION OUTPUT ;
    USE SIGNAL ;
    PORT
      LAYER M4 ;
        RECT  86.316 3.264 86.4 3.288 ;
    END
  END o_data[4]
  PIN o_data[50]
    DIRECTION OUTPUT ;
    USE SIGNAL ;
    PORT
      LAYER M4 ;
        RECT  86.316 16.416 86.4 16.44 ;
    END
  END o_data[50]
  PIN o_data[51]
    DIRECTION OUTPUT ;
    USE SIGNAL ;
    PORT
      LAYER M4 ;
        RECT  86.316 16.704 86.4 16.728 ;
    END
  END o_data[51]
  PIN o_data[52]
    DIRECTION OUTPUT ;
    USE SIGNAL ;
    PORT
      LAYER M4 ;
        RECT  86.316 16.992 86.4 17.016 ;
    END
  END o_data[52]
  PIN o_data[53]
    DIRECTION OUTPUT ;
    USE SIGNAL ;
    PORT
      LAYER M4 ;
        RECT  86.316 17.28 86.4 17.304 ;
    END
  END o_data[53]
  PIN o_data[54]
    DIRECTION OUTPUT ;
    USE SIGNAL ;
    PORT
      LAYER M4 ;
        RECT  86.316 17.568 86.4 17.592 ;
    END
  END o_data[54]
  PIN o_data[55]
    DIRECTION OUTPUT ;
    USE SIGNAL ;
    PORT
      LAYER M4 ;
        RECT  86.316 17.856 86.4 17.88 ;
    END
  END o_data[55]
  PIN o_data[56]
    DIRECTION OUTPUT ;
    USE SIGNAL ;
    PORT
      LAYER M4 ;
        RECT  86.316 18.144 86.4 18.168 ;
    END
  END o_data[56]
  PIN o_data[57]
    DIRECTION OUTPUT ;
    USE SIGNAL ;
    PORT
      LAYER M4 ;
        RECT  86.316 18.384 86.4 18.408 ;
    END
  END o_data[57]
  PIN o_data[58]
    DIRECTION OUTPUT ;
    USE SIGNAL ;
    PORT
      LAYER M4 ;
        RECT  86.316 18.672 86.4 18.696 ;
    END
  END o_data[58]
  PIN o_data[59]
    DIRECTION OUTPUT ;
    USE SIGNAL ;
    PORT
      LAYER M4 ;
        RECT  86.316 18.96 86.4 18.984 ;
    END
  END o_data[59]
  PIN o_data[5]
    DIRECTION OUTPUT ;
    USE SIGNAL ;
    PORT
      LAYER M4 ;
        RECT  86.316 3.552 86.4 3.576 ;
    END
  END o_data[5]
  PIN o_data[60]
    DIRECTION OUTPUT ;
    USE SIGNAL ;
    PORT
      LAYER M4 ;
        RECT  86.316 19.248 86.4 19.272 ;
    END
  END o_data[60]
  PIN o_data[61]
    DIRECTION OUTPUT ;
    USE SIGNAL ;
    PORT
      LAYER M4 ;
        RECT  86.316 19.536 86.4 19.56 ;
    END
  END o_data[61]
  PIN o_data[62]
    DIRECTION OUTPUT ;
    USE SIGNAL ;
    PORT
      LAYER M4 ;
        RECT  86.316 19.824 86.4 19.848 ;
    END
  END o_data[62]
  PIN o_data[63]
    DIRECTION OUTPUT ;
    USE SIGNAL ;
    PORT
      LAYER M4 ;
        RECT  86.316 20.112 86.4 20.136 ;
    END
  END o_data[63]
  PIN o_data[64]
    DIRECTION OUTPUT ;
    USE SIGNAL ;
    PORT
      LAYER M4 ;
        RECT  86.316 20.4 86.4 20.424 ;
    END
  END o_data[64]
  PIN o_data[65]
    DIRECTION OUTPUT ;
    USE SIGNAL ;
    PORT
      LAYER M4 ;
        RECT  86.316 20.688 86.4 20.712 ;
    END
  END o_data[65]
  PIN o_data[66]
    DIRECTION OUTPUT ;
    USE SIGNAL ;
    PORT
      LAYER M4 ;
        RECT  86.316 20.976 86.4 21 ;
    END
  END o_data[66]
  PIN o_data[67]
    DIRECTION OUTPUT ;
    USE SIGNAL ;
    PORT
      LAYER M4 ;
        RECT  86.316 21.264 86.4 21.288 ;
    END
  END o_data[67]
  PIN o_data[68]
    DIRECTION OUTPUT ;
    USE SIGNAL ;
    PORT
      LAYER M4 ;
        RECT  86.316 21.552 86.4 21.576 ;
    END
  END o_data[68]
  PIN o_data[69]
    DIRECTION OUTPUT ;
    USE SIGNAL ;
    PORT
      LAYER M4 ;
        RECT  86.316 21.84 86.4 21.864 ;
    END
  END o_data[69]
  PIN o_data[6]
    DIRECTION OUTPUT ;
    USE SIGNAL ;
    PORT
      LAYER M4 ;
        RECT  86.316 3.84 86.4 3.864 ;
    END
  END o_data[6]
  PIN o_data[70]
    DIRECTION OUTPUT ;
    USE SIGNAL ;
    PORT
      LAYER M4 ;
        RECT  86.316 22.128 86.4 22.152 ;
    END
  END o_data[70]
  PIN o_data[71]
    DIRECTION OUTPUT ;
    USE SIGNAL ;
    PORT
      LAYER M4 ;
        RECT  86.316 22.416 86.4 22.44 ;
    END
  END o_data[71]
  PIN o_data[72]
    DIRECTION OUTPUT ;
    USE SIGNAL ;
    PORT
      LAYER M4 ;
        RECT  86.316 22.704 86.4 22.728 ;
    END
  END o_data[72]
  PIN o_data[73]
    DIRECTION OUTPUT ;
    USE SIGNAL ;
    PORT
      LAYER M4 ;
        RECT  86.316 22.992 86.4 23.016 ;
    END
  END o_data[73]
  PIN o_data[74]
    DIRECTION OUTPUT ;
    USE SIGNAL ;
    PORT
      LAYER M4 ;
        RECT  86.316 23.28 86.4 23.304 ;
    END
  END o_data[74]
  PIN o_data[75]
    DIRECTION OUTPUT ;
    USE SIGNAL ;
    PORT
      LAYER M4 ;
        RECT  86.316 23.568 86.4 23.592 ;
    END
  END o_data[75]
  PIN o_data[76]
    DIRECTION OUTPUT ;
    USE SIGNAL ;
    PORT
      LAYER M4 ;
        RECT  86.316 23.856 86.4 23.88 ;
    END
  END o_data[76]
  PIN o_data[77]
    DIRECTION OUTPUT ;
    USE SIGNAL ;
    PORT
      LAYER M4 ;
        RECT  86.316 24.096 86.4 24.12 ;
    END
  END o_data[77]
  PIN o_data[78]
    DIRECTION OUTPUT ;
    USE SIGNAL ;
    PORT
      LAYER M4 ;
        RECT  86.316 24.384 86.4 24.408 ;
    END
  END o_data[78]
  PIN o_data[79]
    DIRECTION OUTPUT ;
    USE SIGNAL ;
    PORT
      LAYER M4 ;
        RECT  86.316 24.672 86.4 24.696 ;
    END
  END o_data[79]
  PIN o_data[7]
    DIRECTION OUTPUT ;
    USE SIGNAL ;
    PORT
      LAYER M4 ;
        RECT  86.316 4.128 86.4 4.152 ;
    END
  END o_data[7]
  PIN o_data[80]
    DIRECTION OUTPUT ;
    USE SIGNAL ;
    PORT
      LAYER M4 ;
        RECT  86.316 24.96 86.4 24.984 ;
    END
  END o_data[80]
  PIN o_data[81]
    DIRECTION OUTPUT ;
    USE SIGNAL ;
    PORT
      LAYER M4 ;
        RECT  86.316 25.248 86.4 25.272 ;
    END
  END o_data[81]
  PIN o_data[82]
    DIRECTION OUTPUT ;
    USE SIGNAL ;
    PORT
      LAYER M4 ;
        RECT  86.316 25.536 86.4 25.56 ;
    END
  END o_data[82]
  PIN o_data[83]
    DIRECTION OUTPUT ;
    USE SIGNAL ;
    PORT
      LAYER M4 ;
        RECT  86.316 25.824 86.4 25.848 ;
    END
  END o_data[83]
  PIN o_data[84]
    DIRECTION OUTPUT ;
    USE SIGNAL ;
    PORT
      LAYER M4 ;
        RECT  86.316 26.112 86.4 26.136 ;
    END
  END o_data[84]
  PIN o_data[85]
    DIRECTION OUTPUT ;
    USE SIGNAL ;
    PORT
      LAYER M4 ;
        RECT  86.316 26.4 86.4 26.424 ;
    END
  END o_data[85]
  PIN o_data[86]
    DIRECTION OUTPUT ;
    USE SIGNAL ;
    PORT
      LAYER M4 ;
        RECT  86.316 26.688 86.4 26.712 ;
    END
  END o_data[86]
  PIN o_data[87]
    DIRECTION OUTPUT ;
    USE SIGNAL ;
    PORT
      LAYER M4 ;
        RECT  86.316 26.976 86.4 27 ;
    END
  END o_data[87]
  PIN o_data[88]
    DIRECTION OUTPUT ;
    USE SIGNAL ;
    PORT
      LAYER M4 ;
        RECT  86.316 27.264 86.4 27.288 ;
    END
  END o_data[88]
  PIN o_data[89]
    DIRECTION OUTPUT ;
    USE SIGNAL ;
    PORT
      LAYER M4 ;
        RECT  86.316 27.552 86.4 27.576 ;
    END
  END o_data[89]
  PIN o_data[8]
    DIRECTION OUTPUT ;
    USE SIGNAL ;
    PORT
      LAYER M4 ;
        RECT  86.316 4.416 86.4 4.44 ;
    END
  END o_data[8]
  PIN o_data[90]
    DIRECTION OUTPUT ;
    USE SIGNAL ;
    PORT
      LAYER M4 ;
        RECT  86.316 27.84 86.4 27.864 ;
    END
  END o_data[90]
  PIN o_data[91]
    DIRECTION OUTPUT ;
    USE SIGNAL ;
    PORT
      LAYER M4 ;
        RECT  86.316 28.128 86.4 28.152 ;
    END
  END o_data[91]
  PIN o_data[92]
    DIRECTION OUTPUT ;
    USE SIGNAL ;
    PORT
      LAYER M4 ;
        RECT  86.316 28.416 86.4 28.44 ;
    END
  END o_data[92]
  PIN o_data[93]
    DIRECTION OUTPUT ;
    USE SIGNAL ;
    PORT
      LAYER M4 ;
        RECT  86.316 28.704 86.4 28.728 ;
    END
  END o_data[93]
  PIN o_data[94]
    DIRECTION OUTPUT ;
    USE SIGNAL ;
    PORT
      LAYER M4 ;
        RECT  86.316 28.992 86.4 29.016 ;
    END
  END o_data[94]
  PIN o_data[95]
    DIRECTION OUTPUT ;
    USE SIGNAL ;
    PORT
      LAYER M4 ;
        RECT  86.316 29.28 86.4 29.304 ;
    END
  END o_data[95]
  PIN o_data[96]
    DIRECTION OUTPUT ;
    USE SIGNAL ;
    PORT
      LAYER M4 ;
        RECT  86.316 29.52 86.4 29.544 ;
    END
  END o_data[96]
  PIN o_data[97]
    DIRECTION OUTPUT ;
    USE SIGNAL ;
    PORT
      LAYER M4 ;
        RECT  86.316 29.808 86.4 29.832 ;
    END
  END o_data[97]
  PIN o_data[98]
    DIRECTION OUTPUT ;
    USE SIGNAL ;
    PORT
      LAYER M4 ;
        RECT  86.316 30.096 86.4 30.12 ;
    END
  END o_data[98]
  PIN o_data[99]
    DIRECTION OUTPUT ;
    USE SIGNAL ;
    PORT
      LAYER M4 ;
        RECT  86.316 30.384 86.4 30.408 ;
    END
  END o_data[99]
  PIN o_data[9]
    DIRECTION OUTPUT ;
    USE SIGNAL ;
    PORT
      LAYER M4 ;
        RECT  86.316 4.704 86.4 4.728 ;
    END
  END o_data[9]
  PIN o_row[0]
    DIRECTION OUTPUT ;
    USE SIGNAL ;
    PORT
      LAYER M4 ;
        RECT  86.316 75.504 86.4 75.528 ;
    END
  END o_row[0]
  PIN o_row[1]
    DIRECTION OUTPUT ;
    USE SIGNAL ;
    PORT
      LAYER M4 ;
        RECT  86.316 75.792 86.4 75.816 ;
    END
  END o_row[1]
  PIN o_row[2]
    DIRECTION OUTPUT ;
    USE SIGNAL ;
    PORT
      LAYER M4 ;
        RECT  86.316 76.032 86.4 76.056 ;
    END
  END o_row[2]
  PIN o_row[3]
    DIRECTION OUTPUT ;
    USE SIGNAL ;
    PORT
      LAYER M4 ;
        RECT  86.316 76.272 86.4 76.296 ;
    END
  END o_row[3]
  PIN o_row[4]
    DIRECTION OUTPUT ;
    USE SIGNAL ;
    PORT
      LAYER M4 ;
        RECT  86.316 76.56 86.4 76.584 ;
    END
  END o_row[4]
  PIN o_row[5]
    DIRECTION OUTPUT ;
    USE SIGNAL ;
    PORT
      LAYER M4 ;
        RECT  86.316 76.8 86.4 76.824 ;
    END
  END o_row[5]
  PIN o_row[6]
    DIRECTION OUTPUT ;
    USE SIGNAL ;
    PORT
      LAYER M4 ;
        RECT  86.316 77.04 86.4 77.064 ;
    END
  END o_row[6]
  PIN o_we[0]
    DIRECTION OUTPUT ;
    USE SIGNAL ;
    PORT
      LAYER M4 ;
        RECT  86.316 80.304 86.4 80.328 ;
    END
  END o_we[0]
  PIN o_we[1]
    DIRECTION OUTPUT ;
    USE SIGNAL ;
    PORT
      LAYER M4 ;
        RECT  86.316 80.592 86.4 80.616 ;
    END
  END o_we[1]
  PIN o_we[2]
    DIRECTION OUTPUT ;
    USE SIGNAL ;
    PORT
      LAYER M4 ;
        RECT  86.316 80.88 86.4 80.904 ;
    END
  END o_we[2]
  PIN o_we[3]
    DIRECTION OUTPUT ;
    USE SIGNAL ;
    PORT
      LAYER M4 ;
        RECT  86.316 81.12 86.4 81.144 ;
    END
  END o_we[3]
  PIN o_we[4]
    DIRECTION OUTPUT ;
    USE SIGNAL ;
    PORT
      LAYER M4 ;
        RECT  86.316 81.408 86.4 81.432 ;
    END
  END o_we[4]
  PIN o_we[5]
    DIRECTION OUTPUT ;
    USE SIGNAL ;
    PORT
      LAYER M4 ;
        RECT  86.316 81.696 86.4 81.72 ;
    END
  END o_we[5]
  PIN o_we[6]
    DIRECTION OUTPUT ;
    USE SIGNAL ;
    PORT
      LAYER M4 ;
        RECT  86.316 81.936 86.4 81.96 ;
    END
  END o_we[6]
  PIN o_we[7]
    DIRECTION OUTPUT ;
    USE SIGNAL ;
    PORT
      LAYER M4 ;
        RECT  86.316 82.224 86.4 82.248 ;
    END
  END o_we[7]
  PIN o_we[8]
    DIRECTION OUTPUT ;
    USE SIGNAL ;
    PORT
      LAYER M4 ;
        RECT  86.316 82.464 86.4 82.488 ;
    END
  END o_we[8]
  PIN o_we[9]
    DIRECTION OUTPUT ;
    USE SIGNAL ;
    PORT
      LAYER M4 ;
        RECT  86.316 82.752 86.4 82.776 ;
    END
  END o_we[9]
  PIN rst_n
    DIRECTION INPUT ;
    USE SIGNAL ;
    PORT
      LAYER M4 ;
        RECT  0 77.616 0.084 77.64 ;
    END
  END rst_n
  PIN VDD
    DIRECTION INOUT ;
    USE POWER ;
    PORT
      LAYER M5 ;
        RECT  83.592 2.151 83.712 84.249 ;
        RECT  78.192 2.151 78.312 84.249 ;
        RECT  72.792 2.151 72.912 84.249 ;
        RECT  67.392 2.151 67.512 84.249 ;
        RECT  61.992 2.151 62.112 84.249 ;
        RECT  56.592 2.151 56.712 84.249 ;
        RECT  51.192 2.151 51.312 84.249 ;
        RECT  45.792 2.151 45.912 84.249 ;
        RECT  40.392 2.151 40.512 84.249 ;
        RECT  34.992 2.151 35.112 84.249 ;
        RECT  29.592 2.151 29.712 84.249 ;
        RECT  24.192 2.151 24.312 84.249 ;
        RECT  18.792 2.151 18.912 84.249 ;
        RECT  13.392 2.151 13.512 84.249 ;
        RECT  7.992 2.151 8.112 84.249 ;
        RECT  2.592 2.151 2.712 84.249 ;
    END
  END VDD
  PIN VSS
    DIRECTION INOUT ;
    USE GROUND ;
    PORT
      LAYER M5 ;
        RECT  83.4 2.137 83.52 84.263 ;
        RECT  78 2.137 78.12 84.263 ;
        RECT  72.6 2.137 72.72 84.263 ;
        RECT  67.2 2.137 67.32 84.263 ;
        RECT  61.8 2.137 61.92 84.263 ;
        RECT  56.4 2.137 56.52 84.263 ;
        RECT  51 2.137 51.12 84.263 ;
        RECT  45.6 2.137 45.72 84.263 ;
        RECT  40.2 2.137 40.32 84.263 ;
        RECT  34.8 2.137 34.92 84.263 ;
        RECT  29.4 2.137 29.52 84.263 ;
        RECT  24 2.137 24.12 84.263 ;
        RECT  18.6 2.137 18.72 84.263 ;
        RECT  13.2 2.137 13.32 84.263 ;
        RECT  7.8 2.137 7.92 84.263 ;
        RECT  2.4 2.137 2.52 84.263 ;
    END
  END VSS
  # OT_OBS_CLOSED layer=M5 d_um=1.536 added=21
  OBS
    LAYER RVTN ;
     RECT  2.16 2.16 84.24 2.295 ;
     RECT  2.16 2.565 84.24 2.835 ;
     RECT  2.16 3.105 84.24 3.375 ;
     RECT  2.16 3.645 84.24 3.915 ;
     RECT  2.16 4.185 84.24 4.455 ;
     RECT  2.16 4.725 84.24 4.995 ;
     RECT  2.16 5.265 84.24 5.535 ;
     RECT  2.16 5.805 84.24 6.075 ;
     RECT  2.16 6.345 84.24 6.615 ;
     RECT  2.16 6.885 84.24 7.155 ;
     RECT  2.16 7.425 84.24 7.695 ;
     RECT  2.16 7.965 84.24 8.235 ;
     RECT  2.16 8.505 84.24 8.775 ;
     RECT  2.16 9.045 84.24 9.315 ;
     RECT  2.16 9.585 84.24 9.855 ;
     RECT  2.16 10.125 84.24 10.395 ;
     RECT  2.16 10.665 84.24 10.935 ;
     RECT  2.16 11.205 84.24 11.475 ;
     RECT  2.16 11.745 84.24 12.015 ;
     RECT  2.16 12.285 84.24 12.555 ;
     RECT  2.16 12.825 84.24 13.095 ;
     RECT  2.16 13.365 84.24 13.635 ;
     RECT  2.16 13.905 84.24 14.175 ;
     RECT  2.16 14.445 84.24 14.715 ;
     RECT  2.16 14.985 84.24 15.255 ;
     RECT  2.16 15.525 84.24 15.795 ;
     RECT  2.16 16.065 84.24 16.335 ;
     RECT  2.16 16.605 84.24 16.875 ;
     RECT  2.16 17.145 84.24 17.415 ;
     RECT  2.16 17.685 84.24 17.955 ;
     RECT  2.16 18.225 84.24 18.495 ;
     RECT  2.16 18.765 84.24 19.035 ;
     RECT  2.16 19.305 84.24 19.575 ;
     RECT  2.16 19.845 84.24 20.115 ;
     RECT  2.16 20.385 84.24 20.655 ;
     RECT  2.16 20.925 84.24 21.195 ;
     RECT  2.16 21.465 84.24 21.735 ;
     RECT  2.16 22.005 84.24 22.275 ;
     RECT  2.16 22.545 84.24 22.815 ;
     RECT  2.16 23.085 84.24 23.355 ;
     RECT  2.16 23.625 84.24 23.895 ;
     RECT  2.16 24.165 84.24 24.435 ;
     RECT  2.16 24.705 84.24 24.975 ;
     RECT  2.16 25.245 84.24 25.515 ;
     RECT  2.16 25.785 84.24 26.055 ;
     RECT  2.16 26.325 84.24 26.595 ;
     RECT  2.16 26.865 84.24 27.135 ;
     RECT  2.16 27.405 84.24 27.675 ;
     RECT  2.16 27.945 84.24 28.215 ;
     RECT  2.16 28.485 84.24 28.755 ;
     RECT  2.16 29.025 84.24 29.295 ;
     RECT  2.16 29.565 84.24 29.835 ;
     RECT  2.16 30.105 84.24 30.375 ;
     RECT  2.16 30.645 84.24 30.915 ;
     RECT  2.16 31.185 84.24 31.455 ;
     RECT  2.16 31.725 84.24 31.995 ;
     RECT  2.16 32.265 84.24 32.535 ;
     RECT  2.16 32.805 84.24 33.075 ;
     RECT  2.16 33.345 84.24 33.615 ;
     RECT  2.16 33.885 84.24 34.155 ;
     RECT  2.16 34.425 84.24 34.695 ;
     RECT  2.16 34.965 84.24 35.235 ;
     RECT  2.16 35.505 84.24 35.775 ;
     RECT  2.16 36.045 84.24 36.315 ;
     RECT  2.16 36.585 84.24 36.855 ;
     RECT  2.16 37.125 84.24 37.395 ;
     RECT  2.16 37.665 84.24 37.935 ;
     RECT  2.16 38.205 84.24 38.475 ;
     RECT  2.16 38.745 84.24 39.015 ;
     RECT  2.16 39.285 84.24 39.555 ;
     RECT  2.16 39.825 84.24 40.095 ;
     RECT  2.16 40.365 84.24 40.635 ;
     RECT  2.16 40.905 84.24 41.175 ;
     RECT  2.16 41.445 84.24 41.715 ;
     RECT  2.16 41.985 84.24 42.255 ;
     RECT  2.16 42.525 84.24 42.795 ;
     RECT  2.16 43.065 84.24 43.335 ;
     RECT  2.16 43.605 84.24 43.875 ;
     RECT  2.16 44.145 84.24 44.415 ;
     RECT  2.16 44.685 84.24 44.955 ;
     RECT  2.16 45.225 84.24 45.495 ;
     RECT  2.16 45.765 84.24 46.035 ;
     RECT  2.16 46.305 84.24 46.575 ;
     RECT  2.16 46.845 84.24 47.115 ;
     RECT  2.16 47.385 84.24 47.655 ;
     RECT  2.16 47.925 84.24 48.195 ;
     RECT  2.16 48.465 84.24 48.735 ;
     RECT  2.16 49.005 84.24 49.275 ;
     RECT  2.16 49.545 84.24 49.815 ;
     RECT  2.16 50.085 84.24 50.355 ;
     RECT  2.16 50.625 84.24 50.895 ;
     RECT  2.16 51.165 84.24 51.435 ;
     RECT  2.16 51.705 84.24 51.975 ;
     RECT  2.16 52.245 84.24 52.515 ;
     RECT  2.16 52.785 84.24 53.055 ;
     RECT  2.16 53.325 84.24 53.595 ;
     RECT  2.16 53.865 84.24 54.135 ;
     RECT  2.16 54.405 84.24 54.675 ;
     RECT  2.16 54.945 84.24 55.215 ;
     RECT  2.16 55.485 84.24 55.755 ;
     RECT  2.16 56.025 84.24 56.295 ;
     RECT  2.16 56.565 84.24 56.835 ;
     RECT  2.16 57.105 84.24 57.375 ;
     RECT  2.16 57.645 84.24 57.915 ;
     RECT  2.16 58.185 84.24 58.455 ;
     RECT  2.16 58.725 84.24 58.995 ;
     RECT  2.16 59.265 84.24 59.535 ;
     RECT  2.16 59.805 84.24 60.075 ;
     RECT  2.16 60.345 84.24 60.615 ;
     RECT  2.16 60.885 84.24 61.155 ;
     RECT  2.16 61.425 84.24 61.695 ;
     RECT  2.16 61.965 84.24 62.235 ;
     RECT  2.16 62.505 84.24 62.775 ;
     RECT  2.16 63.045 84.24 63.315 ;
     RECT  2.16 63.585 84.24 63.855 ;
     RECT  2.16 64.125 84.24 64.395 ;
     RECT  2.16 64.665 84.24 64.935 ;
     RECT  2.16 65.205 84.24 65.475 ;
     RECT  2.16 65.745 84.24 66.015 ;
     RECT  2.16 66.285 84.24 66.555 ;
     RECT  2.16 66.825 84.24 67.095 ;
     RECT  2.16 67.365 84.24 67.635 ;
     RECT  2.16 67.905 84.24 68.175 ;
     RECT  2.16 68.445 84.24 68.715 ;
     RECT  2.16 68.985 84.24 69.255 ;
     RECT  2.16 69.525 84.24 69.795 ;
     RECT  2.16 70.065 84.24 70.335 ;
     RECT  2.16 70.605 84.24 70.875 ;
     RECT  2.16 71.145 84.24 71.415 ;
     RECT  2.16 71.685 84.24 71.955 ;
     RECT  2.16 72.225 84.24 72.495 ;
     RECT  2.16 72.765 84.24 73.035 ;
     RECT  2.16 73.305 84.24 73.575 ;
     RECT  2.16 73.845 84.24 74.115 ;
     RECT  2.16 74.385 84.24 74.655 ;
     RECT  2.16 74.925 84.24 75.195 ;
     RECT  2.16 75.465 84.24 75.735 ;
     RECT  2.16 76.005 84.24 76.275 ;
     RECT  2.16 76.545 84.24 76.815 ;
     RECT  2.16 77.085 84.24 77.355 ;
     RECT  2.16 77.625 84.24 77.895 ;
     RECT  2.16 78.165 84.24 78.435 ;
     RECT  2.16 78.705 84.24 78.975 ;
     RECT  2.16 79.245 84.24 79.515 ;
     RECT  2.16 79.785 84.24 80.055 ;
     RECT  2.16 80.325 84.24 80.595 ;
     RECT  2.16 80.865 84.24 81.135 ;
     RECT  2.16 81.405 84.24 81.675 ;
     RECT  2.16 81.945 84.24 82.215 ;
     RECT  2.16 82.485 84.24 82.755 ;
     RECT  2.16 83.025 84.24 83.295 ;
     RECT  2.16 83.565 84.24 83.835 ;
     RECT  2.16 84.105 84.24 84.24 ;
    LAYER RVTP ;
     RECT  2.16 2.295 84.24 2.565 ;
     RECT  2.16 2.835 84.24 3.105 ;
     RECT  2.16 3.375 84.24 3.645 ;
     RECT  2.16 3.915 84.24 4.185 ;
     RECT  2.16 4.455 84.24 4.725 ;
     RECT  2.16 4.995 84.24 5.265 ;
     RECT  2.16 5.535 84.24 5.805 ;
     RECT  2.16 6.075 84.24 6.345 ;
     RECT  2.16 6.615 84.24 6.885 ;
     RECT  2.16 7.155 84.24 7.425 ;
     RECT  2.16 7.695 84.24 7.965 ;
     RECT  2.16 8.235 84.24 8.505 ;
     RECT  2.16 8.775 84.24 9.045 ;
     RECT  2.16 9.315 84.24 9.585 ;
     RECT  2.16 9.855 84.24 10.125 ;
     RECT  2.16 10.395 84.24 10.665 ;
     RECT  2.16 10.935 84.24 11.205 ;
     RECT  2.16 11.475 84.24 11.745 ;
     RECT  2.16 12.015 84.24 12.285 ;
     RECT  2.16 12.555 84.24 12.825 ;
     RECT  2.16 13.095 84.24 13.365 ;
     RECT  2.16 13.635 84.24 13.905 ;
     RECT  2.16 14.175 84.24 14.445 ;
     RECT  2.16 14.715 84.24 14.985 ;
     RECT  2.16 15.255 84.24 15.525 ;
     RECT  2.16 15.795 84.24 16.065 ;
     RECT  2.16 16.335 84.24 16.605 ;
     RECT  2.16 16.875 84.24 17.145 ;
     RECT  2.16 17.415 84.24 17.685 ;
     RECT  2.16 17.955 84.24 18.225 ;
     RECT  2.16 18.495 84.24 18.765 ;
     RECT  2.16 19.035 84.24 19.305 ;
     RECT  2.16 19.575 84.24 19.845 ;
     RECT  2.16 20.115 84.24 20.385 ;
     RECT  2.16 20.655 84.24 20.925 ;
     RECT  2.16 21.195 84.24 21.465 ;
     RECT  2.16 21.735 84.24 22.005 ;
     RECT  2.16 22.275 84.24 22.545 ;
     RECT  2.16 22.815 84.24 23.085 ;
     RECT  2.16 23.355 84.24 23.625 ;
     RECT  2.16 23.895 84.24 24.165 ;
     RECT  2.16 24.435 84.24 24.705 ;
     RECT  2.16 24.975 84.24 25.245 ;
     RECT  2.16 25.515 84.24 25.785 ;
     RECT  2.16 26.055 84.24 26.325 ;
     RECT  2.16 26.595 84.24 26.865 ;
     RECT  2.16 27.135 84.24 27.405 ;
     RECT  2.16 27.675 84.24 27.945 ;
     RECT  2.16 28.215 84.24 28.485 ;
     RECT  2.16 28.755 84.24 29.025 ;
     RECT  2.16 29.295 84.24 29.565 ;
     RECT  2.16 29.835 84.24 30.105 ;
     RECT  2.16 30.375 84.24 30.645 ;
     RECT  2.16 30.915 84.24 31.185 ;
     RECT  2.16 31.455 84.24 31.725 ;
     RECT  2.16 31.995 84.24 32.265 ;
     RECT  2.16 32.535 84.24 32.805 ;
     RECT  2.16 33.075 84.24 33.345 ;
     RECT  2.16 33.615 84.24 33.885 ;
     RECT  2.16 34.155 84.24 34.425 ;
     RECT  2.16 34.695 84.24 34.965 ;
     RECT  2.16 35.235 84.24 35.505 ;
     RECT  2.16 35.775 84.24 36.045 ;
     RECT  2.16 36.315 84.24 36.585 ;
     RECT  2.16 36.855 84.24 37.125 ;
     RECT  2.16 37.395 84.24 37.665 ;
     RECT  2.16 37.935 84.24 38.205 ;
     RECT  2.16 38.475 84.24 38.745 ;
     RECT  2.16 39.015 84.24 39.285 ;
     RECT  2.16 39.555 84.24 39.825 ;
     RECT  2.16 40.095 84.24 40.365 ;
     RECT  2.16 40.635 84.24 40.905 ;
     RECT  2.16 41.175 84.24 41.445 ;
     RECT  2.16 41.715 84.24 41.985 ;
     RECT  2.16 42.255 84.24 42.525 ;
     RECT  2.16 42.795 84.24 43.065 ;
     RECT  2.16 43.335 84.24 43.605 ;
     RECT  2.16 43.875 84.24 44.145 ;
     RECT  2.16 44.415 84.24 44.685 ;
     RECT  2.16 44.955 84.24 45.225 ;
     RECT  2.16 45.495 84.24 45.765 ;
     RECT  2.16 46.035 84.24 46.305 ;
     RECT  2.16 46.575 84.24 46.845 ;
     RECT  2.16 47.115 84.24 47.385 ;
     RECT  2.16 47.655 84.24 47.925 ;
     RECT  2.16 48.195 84.24 48.465 ;
     RECT  2.16 48.735 84.24 49.005 ;
     RECT  2.16 49.275 84.24 49.545 ;
     RECT  2.16 49.815 84.24 50.085 ;
     RECT  2.16 50.355 84.24 50.625 ;
     RECT  2.16 50.895 84.24 51.165 ;
     RECT  2.16 51.435 84.24 51.705 ;
     RECT  2.16 51.975 84.24 52.245 ;
     RECT  2.16 52.515 84.24 52.785 ;
     RECT  2.16 53.055 84.24 53.325 ;
     RECT  2.16 53.595 84.24 53.865 ;
     RECT  2.16 54.135 84.24 54.405 ;
     RECT  2.16 54.675 84.24 54.945 ;
     RECT  2.16 55.215 84.24 55.485 ;
     RECT  2.16 55.755 84.24 56.025 ;
     RECT  2.16 56.295 84.24 56.565 ;
     RECT  2.16 56.835 84.24 57.105 ;
     RECT  2.16 57.375 84.24 57.645 ;
     RECT  2.16 57.915 84.24 58.185 ;
     RECT  2.16 58.455 84.24 58.725 ;
     RECT  2.16 58.995 84.24 59.265 ;
     RECT  2.16 59.535 84.24 59.805 ;
     RECT  2.16 60.075 84.24 60.345 ;
     RECT  2.16 60.615 84.24 60.885 ;
     RECT  2.16 61.155 84.24 61.425 ;
     RECT  2.16 61.695 84.24 61.965 ;
     RECT  2.16 62.235 84.24 62.505 ;
     RECT  2.16 62.775 84.24 63.045 ;
     RECT  2.16 63.315 84.24 63.585 ;
     RECT  2.16 63.855 84.24 64.125 ;
     RECT  2.16 64.395 84.24 64.665 ;
     RECT  2.16 64.935 84.24 65.205 ;
     RECT  2.16 65.475 84.24 65.745 ;
     RECT  2.16 66.015 84.24 66.285 ;
     RECT  2.16 66.555 84.24 66.825 ;
     RECT  2.16 67.095 84.24 67.365 ;
     RECT  2.16 67.635 84.24 67.905 ;
     RECT  2.16 68.175 84.24 68.445 ;
     RECT  2.16 68.715 84.24 68.985 ;
     RECT  2.16 69.255 84.24 69.525 ;
     RECT  2.16 69.795 84.24 70.065 ;
     RECT  2.16 70.335 84.24 70.605 ;
     RECT  2.16 70.875 84.24 71.145 ;
     RECT  2.16 71.415 84.24 71.685 ;
     RECT  2.16 71.955 84.24 72.225 ;
     RECT  2.16 72.495 84.24 72.765 ;
     RECT  2.16 73.035 84.24 73.305 ;
     RECT  2.16 73.575 84.24 73.845 ;
     RECT  2.16 74.115 84.24 74.385 ;
     RECT  2.16 74.655 84.24 74.925 ;
     RECT  2.16 75.195 84.24 75.465 ;
     RECT  2.16 75.735 84.24 76.005 ;
     RECT  2.16 76.275 84.24 76.545 ;
     RECT  2.16 76.815 84.24 77.085 ;
     RECT  2.16 77.355 84.24 77.625 ;
     RECT  2.16 77.895 84.24 78.165 ;
     RECT  2.16 78.435 84.24 78.705 ;
     RECT  2.16 78.975 84.24 79.245 ;
     RECT  2.16 79.515 84.24 79.785 ;
     RECT  2.16 80.055 84.24 80.325 ;
     RECT  2.16 80.595 84.24 80.865 ;
     RECT  2.16 81.135 84.24 81.405 ;
     RECT  2.16 81.675 84.24 81.945 ;
     RECT  2.16 82.215 84.24 82.485 ;
     RECT  2.16 82.755 84.24 83.025 ;
     RECT  2.16 83.295 84.24 83.565 ;
     RECT  2.16 83.835 84.24 84.105 ;
    LAYER M1 ;
     RECT  2.16 2.151 84.24 84.249 ;
    LAYER M2 ;
     RECT  0.103 5.976 2.16 5.994 ;
     RECT  0.103 11.142 2.16 11.16 ;
     RECT  0.103 12.096 2.16 12.114 ;
     RECT  0.103 16.344 2.16 16.362 ;
     RECT  0.103 27.576 2.16 27.594 ;
     RECT  0.103 40.806 2.16 40.824 ;
     RECT  0.535 53.532 2.16 53.55 ;
     RECT  2.011 66.6 2.16 66.618 ;
     RECT  0.103 74.592 2.16 74.61 ;
     RECT  0.103 78.48 2.16 80.928 ;
     RECT  0.103 82.962 2.16 82.98 ;
     RECT  2.16 2.151 84.24 84.249 ;
     RECT  84.24 6.246 84.407 6.804 ;
     RECT  84.24 7.596 84.407 7.614 ;
     RECT  84.24 11.646 84.407 11.664 ;
     RECT  84.24 18.666 84.407 18.684 ;
     RECT  84.24 20.556 84.407 20.844 ;
     RECT  84.24 30.582 84.407 30.6 ;
     RECT  84.24 32.706 84.407 32.724 ;
     RECT  84.24 39.726 84.407 39.744 ;
     RECT  84.24 41.616 84.407 41.634 ;
     RECT  84.24 45.126 84.407 45.144 ;
     RECT  84.24 75.366 84.407 75.924 ;
     RECT  84.24 81.648 84.407 81.666 ;
     RECT  84.407 20.826 84.443 20.844 ;
     RECT  84.24 33.786 84.443 33.804 ;
     RECT  84.24 2.196 84.947 4.41 ;
     RECT  84.24 5.166 84.947 5.454 ;
     RECT  84.407 6.516 84.947 6.804 ;
     RECT  84.947 2.196 85.019 4.374 ;
     RECT  85.019 2.196 85.487 4.104 ;
     RECT  84.24 79.452 85.487 80.784 ;
     RECT  84.24 83.736 85.487 83.754 ;
     RECT  85.487 3.816 85.523 4.104 ;
     RECT  84.947 6.516 85.523 6.534 ;
     RECT  84.24 65.376 85.523 65.394 ;
     RECT  85.487 79.956 85.523 80.784 ;
     RECT  85.523 79.992 85.559 80.244 ;
     RECT  85.559 79.992 85.595 80.01 ;
     RECT  85.487 2.196 86.315 3.024 ;
     RECT  84.24 67.374 86.315 67.392 ;
    LAYER M3 ;
     RECT  2.304 2.107 2.322 2.143 ;
     RECT  2.304 2.143 2.505 2.347 ;
     RECT  2.304 2.347 2.754 2.371 ;
     RECT  4.392 2.335 4.41 2.371 ;
     RECT  7.815 2.143 7.905 2.413 ;
     RECT  13.215 2.143 13.305 2.413 ;
     RECT  18.615 2.143 18.705 2.413 ;
     RECT  24.015 2.143 24.105 2.413 ;
     RECT  29.415 2.143 29.505 2.413 ;
     RECT  34.815 2.143 34.905 2.413 ;
     RECT  40.215 2.143 40.305 2.413 ;
     RECT  45.615 2.143 45.705 2.413 ;
     RECT  51.015 2.143 51.105 2.413 ;
     RECT  56.415 2.143 56.505 2.413 ;
     RECT  61.815 2.143 61.905 2.413 ;
     RECT  67.215 2.143 67.305 2.413 ;
     RECT  72.615 2.143 72.705 2.413 ;
     RECT  78.015 2.143 78.105 2.413 ;
     RECT  83.415 2.143 83.505 2.413 ;
     RECT  4.392 2.371 4.698 2.489 ;
     RECT  5.472 2.371 5.49 2.489 ;
     RECT  38.772 2.335 38.79 2.489 ;
     RECT  2.304 2.371 2.862 2.497 ;
     RECT  2.304 2.497 2.934 2.597 ;
     RECT  4.356 2.605 4.374 2.635 ;
     RECT  81.504 2.731 81.522 2.813 ;
     RECT  4.032 2.635 4.374 2.875 ;
     RECT  86.292 2.107 86.31 3.029 ;
     RECT  3.996 2.875 4.374 3.065 ;
     RECT  7.815 2.413 8.097 3.145 ;
     RECT  7.815 3.145 8.154 3.437 ;
     RECT  85.464 3.259 85.482 3.541 ;
     RECT  84.924 3.541 85.482 3.581 ;
     RECT  4.32 3.065 4.374 3.725 ;
     RECT  5.76 2.767 5.778 3.811 ;
     RECT  3.996 3.847 4.014 3.917 ;
     RECT  5.148 3.811 5.778 4.109 ;
     RECT  42.552 3.991 42.57 4.109 ;
     RECT  85.5 3.811 85.518 4.157 ;
     RECT  38.844 4.117 38.862 4.189 ;
     RECT  38.772 4.189 38.862 4.217 ;
     RECT  5.616 4.109 5.778 4.253 ;
     RECT  3.6 4.219 3.618 4.259 ;
     RECT  38.772 4.217 38.79 4.289 ;
     RECT  2.304 2.597 2.697 4.387 ;
     RECT  44.532 3.991 44.55 4.387 ;
     RECT  84.996 4.351 85.014 4.387 ;
     RECT  44.532 4.387 44.73 4.415 ;
     RECT  2.304 4.387 2.754 4.445 ;
     RECT  44.712 4.415 44.73 4.559 ;
     RECT  84.924 4.387 85.014 4.733 ;
     RECT  4.572 4.507 4.59 4.927 ;
     RECT  6.84 4.189 6.858 4.987 ;
     RECT  5.616 4.253 5.634 5.071 ;
     RECT  42.3 4.891 42.318 5.189 ;
     RECT  5.328 5.071 5.634 5.225 ;
     RECT  6.84 4.987 6.93 5.297 ;
     RECT  2.304 4.445 2.697 5.341 ;
     RECT  4.356 4.927 4.59 5.341 ;
     RECT  4.14 5.341 4.59 5.369 ;
     RECT  40.215 2.413 40.497 5.431 ;
     RECT  2.304 5.341 2.898 5.459 ;
     RECT  5.616 5.225 5.634 5.495 ;
     RECT  42.228 5.341 42.246 5.495 ;
     RECT  84.924 4.733 84.942 5.597 ;
     RECT  6.912 5.297 6.93 5.729 ;
     RECT  40.215 5.431 41.058 5.729 ;
     RECT  82.08 4.621 82.098 5.885 ;
     RECT  4.14 5.369 4.158 5.971 ;
     RECT  0.108 5.947 0.126 5.999 ;
     RECT  38.772 5.737 38.79 5.999 ;
     RECT  81.504 5.971 81.522 6.077 ;
     RECT  42.3 6.079 42.426 6.151 ;
     RECT  86.292 6.043 86.31 6.173 ;
     RECT  7.815 3.437 8.097 6.241 ;
     RECT  83.415 2.413 83.697 6.241 ;
     RECT  5.04 6.115 5.058 6.269 ;
     RECT  9.288 6.151 9.306 6.269 ;
     RECT  42.3 6.151 42.966 6.269 ;
     RECT  7.815 6.241 8.298 6.277 ;
     RECT  7.815 6.277 8.37 6.317 ;
     RECT  3.996 5.971 4.158 6.413 ;
     RECT  7.815 6.317 8.298 6.413 ;
     RECT  83.415 6.241 84.402 6.461 ;
     RECT  85.5 6.511 85.518 6.547 ;
     RECT  43.884 6.079 43.902 6.575 ;
     RECT  42.336 6.269 42.786 6.809 ;
     RECT  42.768 6.809 42.786 6.845 ;
     RECT  84.924 6.547 85.518 7.037 ;
     RECT  5.148 6.955 5.166 7.231 ;
     RECT  40.215 5.729 40.497 7.231 ;
     RECT  84.924 7.037 84.942 7.277 ;
     RECT  4.14 6.413 4.158 7.321 ;
     RECT  5.076 7.231 5.166 7.385 ;
     RECT  56.415 2.413 56.697 7.483 ;
     RECT  67.215 2.413 67.497 7.483 ;
     RECT  78.015 2.413 78.297 7.483 ;
     RECT  83.415 6.461 83.697 7.483 ;
     RECT  4.068 7.321 4.158 7.493 ;
     RECT  56.304 7.483 56.697 7.529 ;
     RECT  67.104 7.483 67.497 7.529 ;
     RECT  77.904 7.483 78.297 7.529 ;
     RECT  83.304 7.483 83.697 7.529 ;
     RECT  83.415 7.529 83.697 7.591 ;
     RECT  40.215 7.231 41.058 7.619 ;
     RECT  43.308 7.501 43.326 7.661 ;
     RECT  46.728 7.483 46.746 7.661 ;
     RECT  6.84 7.465 6.858 7.735 ;
     RECT  6.84 7.735 7.002 7.771 ;
     RECT  83.415 7.591 84.402 7.853 ;
     RECT  3.42 7.735 3.438 7.889 ;
     RECT  5.544 7.591 5.562 7.889 ;
     RECT  6.336 7.771 7.002 7.889 ;
     RECT  40.215 7.619 41.022 7.889 ;
     RECT  6.84 7.889 6.858 7.949 ;
     RECT  38.772 7.861 38.79 7.961 ;
     RECT  7.815 6.413 8.097 8.041 ;
     RECT  82.08 7.861 82.098 8.045 ;
     RECT  86.292 8.011 86.31 8.141 ;
     RECT  4.5 8.005 4.662 8.159 ;
     RECT  43.884 7.933 43.902 8.195 ;
     RECT  83.415 7.853 83.79 8.429 ;
     RECT  43.092 8.401 43.11 8.573 ;
     RECT  56.415 7.529 56.697 8.671 ;
     RECT  61.815 2.413 62.097 8.671 ;
     RECT  67.215 7.529 67.497 8.671 ;
     RECT  78.015 7.529 78.297 8.671 ;
     RECT  56.304 8.671 56.697 8.717 ;
     RECT  67.104 8.671 67.497 8.717 ;
     RECT  77.904 8.671 78.297 8.717 ;
     RECT  4.5 8.159 4.59 8.743 ;
     RECT  7.815 8.041 8.154 8.743 ;
     RECT  54.72 8.671 54.738 8.771 ;
     RECT  61.815 8.671 62.73 8.771 ;
     RECT  74.664 8.671 74.682 8.771 ;
     RECT  6.696 8.779 6.714 8.815 ;
     RECT  6.696 8.815 6.786 8.851 ;
     RECT  7.815 8.743 8.298 8.851 ;
     RECT  42.192 8.311 42.21 8.851 ;
     RECT  6.012 8.851 8.298 8.879 ;
     RECT  3.564 8.779 3.582 8.969 ;
     RECT  6.012 8.879 6.03 8.969 ;
     RECT  6.768 8.879 8.298 8.969 ;
     RECT  9.072 8.851 9.09 8.969 ;
     RECT  42.192 8.851 42.498 8.969 ;
     RECT  4.32 8.743 4.59 8.977 ;
     RECT  2.304 5.459 2.697 9.005 ;
     RECT  82.656 8.131 82.674 9.005 ;
     RECT  43.452 8.941 43.578 9.013 ;
     RECT  43.452 9.013 43.902 9.211 ;
     RECT  83.415 8.429 83.697 9.211 ;
     RECT  46.656 9.211 46.674 9.247 ;
     RECT  79.812 8.941 79.83 9.247 ;
     RECT  43.452 9.211 44.082 9.275 ;
     RECT  79.812 9.247 80.406 9.293 ;
     RECT  44.028 9.275 44.082 9.347 ;
     RECT  46.656 9.247 46.746 9.347 ;
     RECT  46.656 9.347 46.674 9.419 ;
     RECT  2.415 9.005 2.697 9.544 ;
     RECT  83.232 9.211 83.697 9.581 ;
     RECT  4.032 8.977 4.59 9.751 ;
     RECT  83.415 9.581 83.697 9.751 ;
     RECT  4.032 9.751 4.77 9.779 ;
     RECT  2.415 9.544 2.79 9.781 ;
     RECT  7.056 8.969 7.074 9.787 ;
     RECT  44.028 9.347 44.046 9.815 ;
     RECT  4.212 9.779 4.77 9.851 ;
     RECT  6.336 9.787 7.074 9.851 ;
     RECT  80.388 9.293 80.406 9.869 ;
     RECT  42.408 8.969 42.426 9.931 ;
     RECT  41.616 9.787 41.634 10.021 ;
     RECT  42.408 9.931 42.93 10.021 ;
     RECT  41.616 10.021 42.93 10.049 ;
     RECT  7.815 8.969 8.154 10.085 ;
     RECT  5.58 9.085 5.598 10.123 ;
     RECT  6.336 9.851 6.354 10.123 ;
     RECT  83.415 9.751 83.826 10.157 ;
     RECT  2.415 9.781 2.826 10.471 ;
     RECT  2.415 10.471 2.862 10.555 ;
     RECT  2.304 10.555 2.862 10.589 ;
     RECT  5.58 10.123 6.354 10.589 ;
     RECT  41.616 10.049 42.21 10.589 ;
     RECT  45.615 2.413 45.897 10.597 ;
     RECT  2.304 10.589 2.754 10.625 ;
     RECT  43.128 10.471 43.326 10.625 ;
     RECT  6.336 10.589 6.354 10.669 ;
     RECT  40.215 7.889 40.497 10.669 ;
     RECT  4.212 9.851 4.23 10.705 ;
     RECT  82.656 10.471 82.674 10.733 ;
     RECT  6.336 10.669 6.858 10.769 ;
     RECT  45.252 10.597 45.897 10.769 ;
     RECT  4.212 10.705 4.518 10.781 ;
     RECT  5.58 10.589 5.598 10.781 ;
     RECT  6.336 10.769 6.642 10.859 ;
     RECT  39.924 10.669 40.497 10.859 ;
     RECT  41.58 10.597 41.598 10.975 ;
     RECT  81.504 10.021 81.522 11.021 ;
     RECT  38.772 10.867 38.79 11.039 ;
     RECT  41.508 10.975 41.598 11.101 ;
     RECT  7.815 10.085 8.097 11.128 ;
     RECT  6.624 10.859 6.642 11.165 ;
     RECT  7.596 11.128 8.097 11.165 ;
     RECT  43.524 10.831 43.902 11.281 ;
     RECT  43.524 11.281 44.046 11.371 ;
     RECT  83.415 10.157 83.697 11.407 ;
     RECT  2.304 10.625 2.697 11.435 ;
     RECT  43.272 11.371 44.046 11.435 ;
     RECT  80.388 11.371 80.406 11.435 ;
     RECT  41.436 11.101 41.598 11.515 ;
     RECT  2.415 11.435 2.697 11.551 ;
     RECT  3.42 11.371 3.438 11.551 ;
     RECT  5.148 11.515 5.166 11.551 ;
     RECT  83.415 11.407 83.79 11.641 ;
     RECT  5.148 11.551 5.454 11.669 ;
     RECT  41.436 11.515 41.742 11.669 ;
     RECT  40.215 10.859 40.497 11.677 ;
     RECT  43.272 11.435 43.902 11.705 ;
     RECT  83.415 11.641 84.402 11.885 ;
     RECT  43.272 11.705 43.29 11.911 ;
     RECT  41.796 11.821 41.814 11.975 ;
     RECT  43.2 11.911 43.29 11.975 ;
     RECT  2.415 11.551 3.438 11.995 ;
     RECT  4.212 11.611 4.23 11.995 ;
     RECT  79.812 11.911 79.83 12.077 ;
     RECT  2.415 11.995 4.23 12.091 ;
     RECT  0.108 11.083 0.126 12.128 ;
     RECT  40.215 11.677 41.058 12.209 ;
     RECT  2.415 12.091 4.41 12.245 ;
     RECT  5.724 11.785 5.742 12.289 ;
     RECT  43.2 11.975 43.218 12.361 ;
     RECT  2.415 12.245 2.697 12.379 ;
     RECT  5.724 12.289 5.886 12.479 ;
     RECT  38.808 12.181 38.826 12.479 ;
     RECT  41.94 12.361 42.03 12.479 ;
     RECT  45.615 10.769 45.897 12.487 ;
     RECT  80.964 12.451 80.982 12.487 ;
     RECT  3.708 12.245 3.726 12.515 ;
     RECT  5.724 12.479 5.742 12.515 ;
     RECT  42.84 12.361 43.218 12.523 ;
     RECT  6.84 12.361 6.858 12.551 ;
     RECT  80.388 12.487 80.982 12.557 ;
     RECT  41.94 12.479 41.958 12.587 ;
     RECT  45.072 12.487 45.897 12.659 ;
     RECT  80.964 12.557 80.982 12.893 ;
     RECT  42.768 12.523 43.218 12.901 ;
     RECT  42.768 12.901 43.614 12.929 ;
     RECT  4.608 12.361 4.662 13.027 ;
     RECT  4.464 13.027 4.662 13.063 ;
     RECT  40.215 12.209 40.554 13.091 ;
     RECT  3.996 13.063 4.662 13.099 ;
     RECT  43.344 12.929 43.614 13.099 ;
     RECT  7.815 11.165 8.097 13.171 ;
     RECT  83.415 11.885 83.697 13.171 ;
     RECT  79.812 12.991 79.83 13.181 ;
     RECT  7.2 13.171 8.097 13.261 ;
     RECT  86.292 12.043 86.31 13.277 ;
     RECT  7.2 13.261 8.154 13.289 ;
     RECT  7.056 13.297 7.074 13.373 ;
     RECT  43.344 13.099 43.938 13.441 ;
     RECT  38.772 13.297 38.79 13.469 ;
     RECT  2.304 12.379 2.697 13.627 ;
     RECT  3.996 13.099 4.914 13.627 ;
     RECT  2.304 13.627 4.914 13.709 ;
     RECT  43.344 13.441 44.334 13.801 ;
     RECT  83.415 13.171 83.754 13.801 ;
     RECT  5.796 13.711 5.814 13.829 ;
     RECT  40.215 13.091 40.497 13.837 ;
     RECT  2.304 13.709 4.554 13.865 ;
     RECT  80.388 13.297 80.406 13.873 ;
     RECT  43.344 13.801 44.514 13.901 ;
     RECT  6.912 13.801 6.93 13.973 ;
     RECT  3.996 13.865 4.554 14.009 ;
     RECT  46.764 13.801 46.782 14.009 ;
     RECT  43.344 13.901 44.37 14.071 ;
     RECT  5.976 13.981 5.994 14.135 ;
     RECT  43.272 14.071 44.37 14.135 ;
     RECT  83.415 13.801 83.826 14.141 ;
     RECT  7.815 13.289 8.154 14.143 ;
     RECT  7.815 14.143 8.586 14.369 ;
     RECT  40.215 13.837 41.058 14.369 ;
     RECT  38.772 14.377 38.79 14.549 ;
     RECT  40.215 14.369 40.497 14.611 ;
     RECT  2.304 13.865 2.826 14.683 ;
     RECT  80.388 13.873 80.442 14.717 ;
     RECT  40.032 14.611 40.497 14.881 ;
     RECT  83.415 14.141 83.697 14.881 ;
     RECT  80.424 14.717 80.442 14.917 ;
     RECT  7.815 14.369 8.406 14.945 ;
     RECT  43.272 14.135 43.398 14.945 ;
     RECT  44.352 14.135 44.37 14.945 ;
     RECT  83.232 14.881 83.697 15.005 ;
     RECT  46.656 14.881 46.674 15.089 ;
     RECT  42.732 15.061 43.254 15.151 ;
     RECT  4.536 14.009 4.554 15.163 ;
     RECT  6.804 15.061 6.822 15.179 ;
     RECT  7.815 14.945 8.19 15.179 ;
     RECT  80.424 14.917 80.982 15.293 ;
     RECT  4.248 15.163 4.554 15.331 ;
     RECT  6.84 15.421 6.858 15.521 ;
     RECT  39.96 14.881 40.497 15.521 ;
     RECT  80.964 15.293 80.982 15.581 ;
     RECT  38.772 15.493 38.79 15.593 ;
     RECT  4.248 15.331 4.59 15.601 ;
     RECT  40.215 15.521 40.497 15.691 ;
     RECT  3.744 15.601 4.59 15.719 ;
     RECT  40.215 15.691 40.554 15.727 ;
     RECT  2.304 14.683 2.862 15.755 ;
     RECT  42.264 15.151 43.254 15.755 ;
     RECT  82.656 15.421 82.674 15.869 ;
     RECT  40.215 15.727 41.058 15.989 ;
     RECT  79.812 15.691 79.83 16.061 ;
     RECT  5.328 15.025 5.346 16.069 ;
     RECT  6.912 15.691 6.93 16.069 ;
     RECT  4.968 16.069 5.346 16.123 ;
     RECT  43.056 15.755 43.254 16.141 ;
     RECT  44.208 15.529 44.226 16.141 ;
     RECT  86.292 16.027 86.31 16.157 ;
     RECT  43.056 16.141 44.226 16.231 ;
     RECT  83.415 15.005 83.697 16.231 ;
     RECT  43.056 16.231 44.406 16.259 ;
     RECT  2.415 15.755 2.862 16.295 ;
     RECT  43.236 16.259 44.406 16.295 ;
     RECT  6.912 16.069 6.966 16.331 ;
     RECT  43.272 16.295 44.406 16.331 ;
     RECT  0.108 15.163 0.126 16.367 ;
     RECT  42.192 16.105 42.21 16.411 ;
     RECT  46.764 16.231 46.782 16.439 ;
     RECT  83.415 16.231 83.826 16.445 ;
     RECT  4.968 16.123 5.814 16.529 ;
     RECT  6.876 16.411 6.894 16.529 ;
     RECT  2.415 16.295 2.697 16.699 ;
     RECT  40.215 15.989 40.554 16.771 ;
     RECT  41.832 16.411 42.21 16.835 ;
     RECT  43.272 16.331 43.686 16.871 ;
     RECT  83.415 16.445 83.79 17.021 ;
     RECT  43.272 16.871 43.29 17.077 ;
     RECT  2.304 16.699 2.697 17.083 ;
     RECT  3.996 15.719 4.05 17.083 ;
     RECT  5.328 16.529 5.814 17.083 ;
     RECT  1.116 16.987 1.134 17.117 ;
     RECT  2.304 17.083 4.05 17.117 ;
     RECT  5.328 17.083 5.994 17.117 ;
     RECT  42.696 17.077 43.29 17.213 ;
     RECT  7.815 15.179 8.097 17.221 ;
     RECT  2.304 17.117 3.87 17.339 ;
     RECT  41.832 16.835 41.85 17.339 ;
     RECT  2.304 17.339 3.798 17.375 ;
     RECT  5.976 17.117 5.994 17.375 ;
     RECT  80.388 16.303 80.406 17.501 ;
     RECT  40.215 16.771 41.058 17.519 ;
     RECT  86.292 17.179 86.31 17.597 ;
     RECT  3.456 17.375 3.798 17.609 ;
     RECT  6.84 17.491 6.858 17.609 ;
     RECT  7.815 17.221 8.406 17.609 ;
     RECT  9.216 17.491 9.234 17.609 ;
     RECT  40.215 17.519 40.626 17.609 ;
     RECT  7.815 17.609 8.262 17.645 ;
     RECT  3.456 17.609 3.474 17.789 ;
     RECT  56.415 8.717 56.697 17.851 ;
     RECT  61.815 8.771 62.097 17.851 ;
     RECT  67.215 8.717 67.497 17.851 ;
     RECT  78.015 8.717 78.297 17.851 ;
     RECT  83.415 17.021 83.754 17.851 ;
     RECT  56.304 17.851 56.697 17.888 ;
     RECT  67.104 17.851 67.497 17.888 ;
     RECT  77.904 17.851 78.297 17.888 ;
     RECT  42.696 17.213 43.074 17.951 ;
     RECT  54.72 17.851 54.738 17.951 ;
     RECT  61.815 17.851 62.73 17.951 ;
     RECT  74.664 17.851 74.682 17.951 ;
     RECT  43.056 17.951 43.074 18.031 ;
     RECT  34.815 2.413 35.097 18.121 ;
     RECT  4.752 18.031 4.77 18.173 ;
     RECT  83.232 17.851 83.754 18.173 ;
     RECT  5.652 18.139 6.21 18.185 ;
     RECT  45.615 12.659 45.897 18.193 ;
     RECT  34.2 18.121 35.097 18.329 ;
     RECT  7.815 17.645 8.097 18.391 ;
     RECT  40.215 17.609 40.554 18.419 ;
     RECT  42.3 18.301 42.318 18.419 ;
     RECT  2.304 17.375 2.697 18.661 ;
     RECT  83.415 18.173 83.754 18.661 ;
     RECT  7.308 18.391 8.097 18.697 ;
     RECT  43.056 18.031 43.362 18.697 ;
     RECT  46.728 18.523 46.746 18.701 ;
     RECT  45.396 18.193 45.897 18.725 ;
     RECT  2.304 18.661 2.862 18.76 ;
     RECT  43.056 18.697 43.794 18.769 ;
     RECT  38.772 17.581 38.79 18.797 ;
     RECT  40.215 18.419 40.497 18.931 ;
     RECT  2.304 18.76 3.402 18.995 ;
     RECT  7.164 18.697 8.097 19.111 ;
     RECT  3.708 19.111 3.726 19.229 ;
     RECT  6.588 19.111 8.097 19.229 ;
     RECT  5.652 18.185 5.67 19.273 ;
     RECT  80.388 18.391 80.406 19.273 ;
     RECT  79.812 19.273 80.406 19.277 ;
     RECT  5.508 19.273 5.67 19.339 ;
     RECT  4.68 18.763 4.698 19.345 ;
     RECT  42.588 18.769 43.794 19.345 ;
     RECT  5.508 19.339 5.742 19.379 ;
     RECT  6.84 19.229 8.097 19.381 ;
     RECT  6.84 19.381 8.118 19.499 ;
     RECT  42.588 19.345 43.83 19.507 ;
     RECT  83.415 18.661 84.402 19.565 ;
     RECT  2.304 18.995 2.697 19.571 ;
     RECT  6.912 19.499 8.118 19.571 ;
     RECT  39.924 18.931 40.497 19.769 ;
     RECT  79.812 19.277 79.83 19.853 ;
     RECT  42.3 19.507 43.83 19.885 ;
     RECT  42.3 19.885 43.902 19.921 ;
     RECT  4.32 19.345 4.698 20.011 ;
     RECT  42.3 19.921 44.046 20.039 ;
     RECT  2.415 19.571 2.697 20.047 ;
     RECT  4.32 20.011 5.13 20.047 ;
     RECT  42.66 20.039 44.046 20.075 ;
     RECT  2.415 20.047 2.826 20.093 ;
     RECT  3.888 20.047 5.13 20.219 ;
     RECT  38.844 20.047 38.862 20.281 ;
     RECT  38.772 20.281 38.862 20.309 ;
     RECT  42.696 20.075 44.046 20.309 ;
     RECT  38.772 20.309 38.79 20.381 ;
     RECT  4.464 20.219 5.13 20.461 ;
     RECT  2.415 20.093 2.697 20.539 ;
     RECT  83.415 19.565 83.862 20.551 ;
     RECT  43.884 20.309 44.046 20.615 ;
     RECT  43.92 20.615 44.046 20.717 ;
     RECT  4.464 20.461 5.166 20.731 ;
     RECT  6.264 20.425 6.282 20.731 ;
     RECT  4.464 20.731 6.282 20.759 ;
     RECT  83.415 20.551 84.402 20.821 ;
     RECT  2.304 20.539 2.697 20.827 ;
     RECT  7.128 19.571 8.097 20.857 ;
     RECT  40.215 19.769 40.497 20.857 ;
     RECT  4.464 20.759 6.102 20.861 ;
     RECT  2.304 20.827 3.402 20.885 ;
     RECT  4.464 20.861 4.482 20.885 ;
     RECT  43.92 20.717 43.938 20.885 ;
     RECT  41.616 20.353 41.634 20.929 ;
     RECT  42.696 20.309 42.786 20.929 ;
     RECT  5.328 20.861 6.102 21.029 ;
     RECT  6.912 20.857 8.097 21.029 ;
     RECT  46.728 20.893 46.746 21.029 ;
     RECT  7.128 21.029 8.097 21.115 ;
     RECT  41.616 20.929 42.786 21.119 ;
     RECT  7.128 21.115 8.154 21.149 ;
     RECT  79.812 20.893 79.83 21.197 ;
     RECT  7.815 21.149 8.154 21.271 ;
     RECT  3.528 21.271 3.546 21.389 ;
     RECT  5.94 21.029 6.102 21.389 ;
     RECT  7.815 21.271 8.298 21.389 ;
     RECT  10.764 21.361 10.782 21.397 ;
     RECT  42.048 21.119 42.786 21.469 ;
     RECT  42.048 21.469 42.822 21.505 ;
     RECT  10.764 21.397 10.854 21.533 ;
     RECT  10.836 21.533 10.854 21.569 ;
     RECT  83.415 20.821 84.438 21.581 ;
     RECT  39.924 20.857 40.497 21.659 ;
     RECT  84.42 21.581 84.438 21.869 ;
     RECT  4.68 21.631 4.698 21.883 ;
     RECT  80.964 21.091 80.982 21.901 ;
     RECT  42.048 21.505 43.65 22.009 ;
     RECT  80.964 21.901 81.018 22.013 ;
     RECT  4.536 21.883 4.698 22.081 ;
     RECT  3.744 22.045 3.762 22.199 ;
     RECT  4.536 22.081 5.058 22.199 ;
     RECT  42.048 22.009 43.722 22.207 ;
     RECT  4.536 22.199 4.554 22.235 ;
     RECT  81 22.013 81.018 22.349 ;
     RECT  6.264 22.045 6.282 22.351 ;
     RECT  7.815 21.389 8.154 22.351 ;
     RECT  86.292 21.163 86.31 22.445 ;
     RECT  6.264 22.351 6.858 22.459 ;
     RECT  7.815 22.351 8.298 22.469 ;
     RECT  6.264 22.459 7.074 22.505 ;
     RECT  7.815 22.469 8.154 22.505 ;
     RECT  41.616 22.207 43.722 22.577 ;
     RECT  56.415 17.888 56.697 22.603 ;
     RECT  67.215 17.888 67.497 22.603 ;
     RECT  78.015 17.888 78.297 22.603 ;
     RECT  83.415 21.581 83.697 22.603 ;
     RECT  10.908 22.441 10.926 22.649 ;
     RECT  56.304 22.603 56.697 22.649 ;
     RECT  67.104 22.603 67.497 22.649 ;
     RECT  77.904 22.603 78.297 22.649 ;
     RECT  83.304 22.603 83.697 22.649 ;
     RECT  83.415 22.649 83.697 22.711 ;
     RECT  42.516 22.577 43.722 22.747 ;
     RECT  42.516 22.747 44.046 22.775 ;
     RECT  45.615 18.725 45.897 22.843 ;
     RECT  42.732 22.775 44.046 23.009 ;
     RECT  45.615 22.843 45.99 23.021 ;
     RECT  41.616 22.577 41.634 23.081 ;
     RECT  42.984 23.009 44.046 23.089 ;
     RECT  6.264 22.505 6.534 23.161 ;
     RECT  7.815 22.505 8.097 23.161 ;
     RECT  38.772 23.017 38.79 23.189 ;
     RECT  6.228 23.161 6.534 23.275 ;
     RECT  7.38 23.161 8.097 23.275 ;
     RECT  6.228 23.275 8.097 23.279 ;
     RECT  40.215 21.659 40.497 23.287 ;
     RECT  4.464 23.125 5.202 23.315 ;
     RECT  5.256 23.317 5.274 23.357 ;
     RECT  6.336 23.279 8.097 23.357 ;
     RECT  80.388 22.981 80.406 23.521 ;
     RECT  40.215 23.287 41.058 23.549 ;
     RECT  6.84 23.357 8.097 23.701 ;
     RECT  80.388 23.521 80.982 23.791 ;
     RECT  4.464 23.315 4.482 23.855 ;
     RECT  42.984 23.089 44.478 23.855 ;
     RECT  6.84 23.701 8.55 23.891 ;
     RECT  2.304 20.885 2.697 23.899 ;
     RECT  38.808 23.827 38.826 23.927 ;
     RECT  2.304 23.899 2.97 24.061 ;
     RECT  2.304 24.061 3.474 24.125 ;
     RECT  42.984 23.855 43.902 24.125 ;
     RECT  80.388 23.791 81.522 24.125 ;
     RECT  3.456 24.125 3.474 24.161 ;
     RECT  3.888 24.205 3.906 24.359 ;
     RECT  4.68 24.241 4.842 24.359 ;
     RECT  5.616 24.241 5.634 24.359 ;
     RECT  40.215 23.549 40.497 24.367 ;
     RECT  40.215 24.367 40.554 24.403 ;
     RECT  81.504 24.125 81.522 24.413 ;
     RECT  2.304 24.125 2.697 24.503 ;
     RECT  4.68 24.359 4.698 24.601 ;
     RECT  39.924 24.403 40.554 24.601 ;
     RECT  83.415 22.711 83.826 24.871 ;
     RECT  2.415 24.503 2.697 24.907 ;
     RECT  39.924 24.601 40.59 24.907 ;
     RECT  42.984 24.125 43.722 24.943 ;
     RECT  80.388 24.125 80.406 24.989 ;
     RECT  10.8 24.907 10.818 25.043 ;
     RECT  5.724 24.871 5.742 25.099 ;
     RECT  6.84 23.891 8.097 25.192 ;
     RECT  4.356 24.601 4.698 25.435 ;
     RECT  5.724 25.099 5.814 25.469 ;
     RECT  4.068 25.435 4.698 25.475 ;
     RECT  6.912 25.192 8.097 25.475 ;
     RECT  5.724 25.469 5.742 25.547 ;
     RECT  2.415 24.907 3.114 25.675 ;
     RECT  42.48 24.943 43.722 25.681 ;
     RECT  42.48 25.681 43.758 25.781 ;
     RECT  83.415 24.871 83.862 25.853 ;
     RECT  2.304 25.675 3.114 25.861 ;
     RECT  2.304 25.861 3.69 25.979 ;
     RECT  4.536 25.475 4.698 25.979 ;
     RECT  39.924 24.907 40.626 25.979 ;
     RECT  39.96 25.979 40.626 26.023 ;
     RECT  3.672 25.979 3.69 26.051 ;
     RECT  42.48 25.781 43.362 26.131 ;
     RECT  80.964 25.141 80.982 26.141 ;
     RECT  6.912 25.475 6.93 26.159 ;
     RECT  38.196 25.411 38.214 26.249 ;
     RECT  79.812 25.753 79.83 26.249 ;
     RECT  42.264 26.131 43.362 26.285 ;
     RECT  56.415 22.649 56.697 26.392 ;
     RECT  67.215 22.649 67.497 26.392 ;
     RECT  78.015 22.649 78.297 26.392 ;
     RECT  7.815 25.475 8.097 26.401 ;
     RECT  46.728 26.299 46.746 26.429 ;
     RECT  56.304 26.392 56.697 26.429 ;
     RECT  67.104 26.392 67.497 26.429 ;
     RECT  77.904 26.392 78.297 26.429 ;
     RECT  6.624 26.221 6.642 26.485 ;
     RECT  7.815 26.401 8.298 26.491 ;
     RECT  4.176 26.401 4.194 26.519 ;
     RECT  7.704 26.491 8.298 26.519 ;
     RECT  39.96 26.023 40.986 26.519 ;
     RECT  6.48 26.485 6.642 26.525 ;
     RECT  10.8 26.491 10.818 26.527 ;
     RECT  7.704 26.519 8.097 26.555 ;
     RECT  10.8 26.527 10.854 26.563 ;
     RECT  10.728 26.563 10.854 26.699 ;
     RECT  83.415 25.853 83.826 26.761 ;
     RECT  39.96 26.519 40.497 26.789 ;
     RECT  2.304 25.979 2.697 26.797 ;
     RECT  42.696 26.285 43.362 26.825 ;
     RECT  2.304 26.797 3.366 27.095 ;
     RECT  4.572 27.103 4.59 27.139 ;
     RECT  41.616 26.563 41.634 27.211 ;
     RECT  42.696 26.825 43.326 27.211 ;
     RECT  4.572 27.139 5.814 27.239 ;
     RECT  5.508 27.239 5.814 27.329 ;
     RECT  6.84 27.211 6.858 27.329 ;
     RECT  38.772 26.527 38.79 27.329 ;
     RECT  41.616 27.211 43.326 27.329 ;
     RECT  40.215 26.789 40.497 27.337 ;
     RECT  4.572 27.239 4.59 27.365 ;
     RECT  5.652 27.329 5.67 27.473 ;
     RECT  86.292 27.163 86.31 27.581 ;
     RECT  0.108 27.499 0.126 27.599 ;
     RECT  42.192 27.329 43.326 27.679 ;
     RECT  42.192 27.679 43.902 27.751 ;
     RECT  42.192 27.751 44.55 27.779 ;
     RECT  83.415 26.761 83.862 27.869 ;
     RECT  6.66 27.445 6.678 27.905 ;
     RECT  4.176 27.571 4.194 27.913 ;
     RECT  2.304 27.095 2.697 27.979 ;
     RECT  3.996 27.913 4.194 28.111 ;
     RECT  56.415 26.429 56.697 28.111 ;
     RECT  61.815 17.951 62.097 28.111 ;
     RECT  67.215 26.429 67.497 28.111 ;
     RECT  78.015 26.429 78.297 28.111 ;
     RECT  3.996 28.111 4.878 28.139 ;
     RECT  56.304 28.111 56.697 28.157 ;
     RECT  67.104 28.111 67.497 28.157 ;
     RECT  77.904 28.111 78.297 28.157 ;
     RECT  40.215 27.337 41.058 28.183 ;
     RECT  4.32 28.139 4.878 28.211 ;
     RECT  46.764 28.111 46.782 28.211 ;
     RECT  54.72 28.111 54.738 28.211 ;
     RECT  61.815 28.111 62.73 28.211 ;
     RECT  74.664 28.111 74.682 28.211 ;
     RECT  5.58 28.255 5.598 28.301 ;
     RECT  6.768 28.183 6.786 28.453 ;
     RECT  7.815 26.555 8.097 28.561 ;
     RECT  6.768 28.453 6.858 28.651 ;
     RECT  80.964 28.381 80.982 28.651 ;
     RECT  7.815 28.561 8.298 28.679 ;
     RECT  10.8 28.651 10.818 28.687 ;
     RECT  39.924 28.183 41.058 28.723 ;
     RECT  42.192 27.779 42.246 28.723 ;
     RECT  6.696 28.651 6.858 28.733 ;
     RECT  2.304 27.979 2.79 28.831 ;
     RECT  3.564 28.561 3.582 28.831 ;
     RECT  39.924 28.723 42.246 28.831 ;
     RECT  42.984 27.779 44.55 28.831 ;
     RECT  10.8 28.687 10.854 28.859 ;
     RECT  2.304 28.831 3.582 28.921 ;
     RECT  4.32 28.211 4.698 28.921 ;
     RECT  7.815 28.679 8.154 29.069 ;
     RECT  6.948 29.035 6.966 29.101 ;
     RECT  7.815 29.069 8.097 29.101 ;
     RECT  2.304 28.921 4.698 29.219 ;
     RECT  39.924 28.831 44.55 29.219 ;
     RECT  4.14 29.219 4.698 29.227 ;
     RECT  42.3 29.219 44.55 29.255 ;
     RECT  80.964 28.651 81.522 29.299 ;
     RECT  83.415 27.869 83.826 29.309 ;
     RECT  2.304 29.219 3.078 29.363 ;
     RECT  10.8 28.859 10.818 29.363 ;
     RECT  38.772 28.687 38.79 29.363 ;
     RECT  46.728 29.299 46.746 29.399 ;
     RECT  39.924 29.219 41.058 29.489 ;
     RECT  80.388 29.299 81.522 29.549 ;
     RECT  6.948 29.101 8.097 29.645 ;
     RECT  4.14 29.227 5.166 29.659 ;
     RECT  6.12 29.611 6.138 29.659 ;
     RECT  4.14 29.659 6.138 29.693 ;
     RECT  34.815 18.329 35.097 29.767 ;
     RECT  2.415 29.363 3.078 29.795 ;
     RECT  80.388 29.549 80.982 29.837 ;
     RECT  7.128 29.645 8.097 29.939 ;
     RECT  42.3 29.255 44.19 30.001 ;
     RECT  2.415 29.795 2.79 30.077 ;
     RECT  80.388 29.837 80.406 30.125 ;
     RECT  2.415 30.077 2.697 30.283 ;
     RECT  34.2 29.767 35.097 30.299 ;
     RECT  42.192 30.001 44.19 30.413 ;
     RECT  5.796 29.693 6.138 30.451 ;
     RECT  40.215 29.489 41.058 30.541 ;
     RECT  42.192 30.413 43.974 30.541 ;
     RECT  83.415 29.309 83.697 30.541 ;
     RECT  4.14 29.693 4.554 30.568 ;
     RECT  7.815 29.939 8.097 30.568 ;
     RECT  10.764 30.541 10.782 30.577 ;
     RECT  83.415 30.541 83.79 30.577 ;
     RECT  3.996 30.568 4.554 30.605 ;
     RECT  7.815 30.568 8.262 30.605 ;
     RECT  40.215 30.541 43.974 30.701 ;
     RECT  10.764 30.577 10.854 30.713 ;
     RECT  10.836 30.713 10.854 30.749 ;
     RECT  83.415 30.577 84.402 30.811 ;
     RECT  40.215 30.701 42.714 30.839 ;
     RECT  4.536 30.605 4.554 30.991 ;
     RECT  4.536 30.991 4.698 31.081 ;
     RECT  5.796 30.451 6.534 31.081 ;
     RECT  4.536 31.081 6.534 31.109 ;
     RECT  81.504 30.271 81.522 31.181 ;
     RECT  5.4 31.109 6.534 31.189 ;
     RECT  5.4 31.189 6.858 31.229 ;
     RECT  5.4 31.229 6.102 31.253 ;
     RECT  86.292 31.147 86.31 31.277 ;
     RECT  43.488 30.701 43.974 31.351 ;
     RECT  44.784 30.451 44.802 31.351 ;
     RECT  43.488 31.351 44.802 31.415 ;
     RECT  83.232 30.811 84.402 31.565 ;
     RECT  2.304 30.283 2.697 31.621 ;
     RECT  6.84 31.229 6.858 31.649 ;
     RECT  41.4 30.839 42.714 31.649 ;
     RECT  38.808 31.657 38.826 31.757 ;
     RECT  4.176 31.627 4.194 31.765 ;
     RECT  42.048 31.649 42.714 31.765 ;
     RECT  42.048 31.765 42.75 31.801 ;
     RECT  43.488 31.415 43.506 31.801 ;
     RECT  7.02 31.801 7.038 31.919 ;
     RECT  2.304 31.621 2.79 32.035 ;
     RECT  6.084 31.253 6.102 32.155 ;
     RECT  40.215 30.839 40.554 32.161 ;
     RECT  2.304 32.035 3.186 32.189 ;
     RECT  5.076 32.155 6.102 32.189 ;
     RECT  5.076 32.189 5.778 32.195 ;
     RECT  80.964 31.351 80.982 32.333 ;
     RECT  44.388 31.415 44.802 32.341 ;
     RECT  45.615 23.021 45.897 32.341 ;
     RECT  86.292 32.299 86.31 32.429 ;
     RECT  4.104 31.765 4.194 32.431 ;
     RECT  42.048 31.801 43.506 32.459 ;
     RECT  83.232 31.565 83.826 32.467 ;
     RECT  4.104 32.431 4.59 32.611 ;
     RECT  40.215 32.161 41.058 32.701 ;
     RECT  83.232 32.467 83.862 32.701 ;
     RECT  6.84 32.611 6.93 32.729 ;
     RECT  9.144 32.611 9.162 32.729 ;
     RECT  7.815 30.605 8.097 32.737 ;
     RECT  40.215 32.701 41.094 32.737 ;
     RECT  44.388 32.341 45.897 32.765 ;
     RECT  5.76 32.195 5.778 32.813 ;
     RECT  7.815 32.737 8.154 32.813 ;
     RECT  6.84 32.729 6.858 32.873 ;
     RECT  10.836 32.737 10.854 32.909 ;
     RECT  56.415 28.157 56.697 32.971 ;
     RECT  67.215 28.157 67.497 32.971 ;
     RECT  78.015 28.157 78.297 32.971 ;
     RECT  4.068 32.611 4.59 33.007 ;
     RECT  45.504 32.765 45.897 33.008 ;
     RECT  56.304 32.971 56.697 33.008 ;
     RECT  67.104 32.971 67.497 33.008 ;
     RECT  77.904 32.971 78.297 33.008 ;
     RECT  38.772 32.881 38.79 33.035 ;
     RECT  42.624 32.459 43.506 33.043 ;
     RECT  44.388 32.765 44.694 33.043 ;
     RECT  4.032 33.007 4.59 33.067 ;
     RECT  4.032 33.067 5.058 33.101 ;
     RECT  39.924 32.737 41.094 33.269 ;
     RECT  83.232 32.701 84.402 33.293 ;
     RECT  42.624 33.043 44.694 33.305 ;
     RECT  46.8 33.277 46.818 33.449 ;
     RECT  42.624 33.305 44.478 33.575 ;
     RECT  4.572 33.101 5.058 33.583 ;
     RECT  2.304 32.189 2.697 33.643 ;
     RECT  2.304 33.643 2.754 33.691 ;
     RECT  7.815 32.813 8.097 33.691 ;
     RECT  34.815 30.299 35.097 33.781 ;
     RECT  83.415 33.293 84.402 33.781 ;
     RECT  2.304 33.691 2.934 33.809 ;
     RECT  6.192 33.925 6.21 33.961 ;
     RECT  7.632 33.691 8.097 33.961 ;
     RECT  39.924 33.269 40.497 34.079 ;
     RECT  7.632 33.961 8.478 34.087 ;
     RECT  4.572 33.583 5.166 34.115 ;
     RECT  43.776 33.575 44.478 34.115 ;
     RECT  43.848 34.115 44.478 34.159 ;
     RECT  6.192 33.961 6.282 34.171 ;
     RECT  2.304 33.809 2.862 34.187 ;
     RECT  41.616 34.123 41.634 34.195 ;
     RECT  6.192 34.171 6.642 34.259 ;
     RECT  34.2 33.781 35.097 34.259 ;
     RECT  4.5 34.159 4.518 34.315 ;
     RECT  4.356 34.315 4.518 34.349 ;
     RECT  41.508 34.195 41.634 34.349 ;
     RECT  38.808 33.961 38.826 34.357 ;
     RECT  4.356 34.349 4.374 34.385 ;
     RECT  38.808 34.357 38.862 34.421 ;
     RECT  6.624 34.259 6.642 34.429 ;
     RECT  7.488 34.087 8.478 34.429 ;
     RECT  41.616 34.349 41.634 34.429 ;
     RECT  42.624 33.575 42.93 34.429 ;
     RECT  38.844 34.421 38.862 34.493 ;
     RECT  6.624 34.429 8.586 34.529 ;
     RECT  5.328 34.429 5.346 34.619 ;
     RECT  6.624 34.529 6.714 34.619 ;
     RECT  7.56 34.529 8.586 34.619 ;
     RECT  34.815 34.259 35.097 34.627 ;
     RECT  6.624 34.619 6.642 34.655 ;
     RECT  3.996 34.627 4.014 34.685 ;
     RECT  10.764 34.501 10.782 34.691 ;
     RECT  83.415 33.781 84.438 35.021 ;
     RECT  2.304 34.187 2.79 35.041 ;
     RECT  41.616 34.429 42.93 35.041 ;
     RECT  41.616 35.041 43.11 35.159 ;
     RECT  42.192 35.159 43.11 35.203 ;
     RECT  43.848 34.159 44.586 35.203 ;
     RECT  80.964 33.277 80.982 35.261 ;
     RECT  2.304 35.041 3.006 35.275 ;
     RECT  2.304 35.275 3.726 35.465 ;
     RECT  38.772 35.437 38.79 35.537 ;
     RECT  5.76 35.401 5.778 35.545 ;
     RECT  42.192 35.203 44.586 35.549 ;
     RECT  6.84 35.437 6.858 35.671 ;
     RECT  40.215 34.079 40.497 35.671 ;
     RECT  6.768 35.671 6.858 35.744 ;
     RECT  0.108 35.659 0.126 35.789 ;
     RECT  79.812 34.861 79.83 35.837 ;
     RECT  6.768 35.744 6.786 35.879 ;
     RECT  42.192 35.549 43.902 35.879 ;
     RECT  5.472 35.545 5.778 35.885 ;
     RECT  40.215 35.671 40.554 35.941 ;
     RECT  34.815 34.627 35.622 36.005 ;
     RECT  2.304 35.465 3.33 36.113 ;
     RECT  4.68 36.013 4.698 36.187 ;
     RECT  40.215 35.941 41.058 36.211 ;
     RECT  4.32 36.187 4.698 36.509 ;
     RECT  31.428 36.481 31.446 36.557 ;
     RECT  5.76 35.885 5.778 36.625 ;
     RECT  39.924 36.211 41.058 36.625 ;
     RECT  6.84 36.523 6.858 36.653 ;
     RECT  4.32 36.509 4.338 36.763 ;
     RECT  6.876 36.661 7.074 36.779 ;
     RECT  42.228 35.879 43.902 36.779 ;
     RECT  3.996 36.763 4.338 36.815 ;
     RECT  5.22 36.625 5.814 36.815 ;
     RECT  6.876 36.779 6.894 36.815 ;
     RECT  39.924 36.625 41.094 36.823 ;
     RECT  42.228 36.779 42.282 36.823 ;
     RECT  39.924 36.823 42.282 36.887 ;
     RECT  43.164 36.779 43.902 36.923 ;
     RECT  83.415 35.021 83.826 36.989 ;
     RECT  43.2 36.923 43.902 37.021 ;
     RECT  31.14 36.661 31.158 37.037 ;
     RECT  4.32 36.815 4.338 37.049 ;
     RECT  40.215 36.887 42.282 37.049 ;
     RECT  43.2 37.021 44.406 37.085 ;
     RECT  43.308 37.085 44.406 37.193 ;
     RECT  86.292 37.435 86.31 37.565 ;
     RECT  5.22 36.815 5.382 37.627 ;
     RECT  4.68 37.627 5.382 37.661 ;
     RECT  2.304 36.113 2.697 37.723 ;
     RECT  2.268 37.723 2.697 37.741 ;
     RECT  2.268 37.741 2.718 37.769 ;
     RECT  40.215 37.049 41.67 37.831 ;
     RECT  83.415 36.989 83.79 37.853 ;
     RECT  3.672 37.741 3.69 37.859 ;
     RECT  4.68 37.661 4.698 37.895 ;
     RECT  45.615 33.008 45.897 37.963 ;
     RECT  43.344 37.193 44.406 38.101 ;
     RECT  5.508 37.741 5.922 38.129 ;
     RECT  45.615 37.963 45.99 38.141 ;
     RECT  4.572 38.137 4.59 38.189 ;
     RECT  5.724 38.129 5.778 38.189 ;
     RECT  2.304 37.769 2.718 38.251 ;
     RECT  3.564 38.347 3.582 38.399 ;
     RECT  42.912 38.101 44.442 38.443 ;
     RECT  38.772 38.371 38.79 38.471 ;
     RECT  83.415 37.853 83.697 38.641 ;
     RECT  39.924 37.831 41.67 38.669 ;
     RECT  2.304 38.251 2.79 38.705 ;
     RECT  2.415 38.705 2.79 38.821 ;
     RECT  7.815 34.619 8.097 38.821 ;
     RECT  83.415 38.641 83.826 38.911 ;
     RECT  2.415 38.821 2.826 38.939 ;
     RECT  7.236 38.821 8.097 38.939 ;
     RECT  7.02 39.091 7.038 39.149 ;
     RECT  42.408 38.443 44.442 39.209 ;
     RECT  2.415 38.939 2.754 39.245 ;
     RECT  5.724 38.189 5.742 39.253 ;
     RECT  42.696 39.209 44.442 39.289 ;
     RECT  4.716 39.289 4.734 39.451 ;
     RECT  5.724 39.253 5.814 39.451 ;
     RECT  5.652 39.451 5.814 39.479 ;
     RECT  2.415 39.245 2.697 39.547 ;
     RECT  40.215 38.669 41.202 39.595 ;
     RECT  6.912 39.523 6.93 39.659 ;
     RECT  7.815 38.939 8.097 39.721 ;
     RECT  83.415 38.911 83.862 39.721 ;
     RECT  4.572 39.451 4.734 39.757 ;
     RECT  4.032 39.757 4.734 39.821 ;
     RECT  4.32 39.821 4.734 39.865 ;
     RECT  5.652 39.479 5.778 39.865 ;
     RECT  4.32 39.865 5.778 39.917 ;
     RECT  4.32 39.917 4.338 40.019 ;
     RECT  42.696 39.289 44.802 40.019 ;
     RECT  2.304 39.547 2.697 40.021 ;
     RECT  2.304 40.021 2.826 40.061 ;
     RECT  10.8 38.983 10.818 40.063 ;
     RECT  34.815 36.005 35.097 40.063 ;
     RECT  7.74 39.721 8.097 40.135 ;
     RECT  5.148 39.917 5.778 40.199 ;
     RECT  10.764 40.063 10.818 40.199 ;
     RECT  40.215 39.595 41.634 40.261 ;
     RECT  10.764 40.199 10.782 40.325 ;
     RECT  7.236 40.135 8.097 40.411 ;
     RECT  7.056 40.411 8.097 40.445 ;
     RECT  38.196 40.027 38.214 40.531 ;
     RECT  39.348 39.523 39.366 40.531 ;
     RECT  42.84 40.019 44.802 40.637 ;
     RECT  46.728 40.603 46.746 40.733 ;
     RECT  5.688 40.199 5.778 40.801 ;
     RECT  5.688 40.801 6.246 40.829 ;
     RECT  38.196 40.531 39.366 40.829 ;
     RECT  42.84 40.637 44.766 40.865 ;
     RECT  42.84 40.865 44.478 40.981 ;
     RECT  7.056 40.445 7.074 41.021 ;
     RECT  6.228 40.829 6.246 41.071 ;
     RECT  6.228 41.071 6.354 41.099 ;
     RECT  3.996 40.801 4.014 41.135 ;
     RECT  40.215 40.261 41.67 41.251 ;
     RECT  42.804 40.981 44.478 41.251 ;
     RECT  38.196 40.829 38.79 41.279 ;
     RECT  3.852 41.251 3.87 41.369 ;
     RECT  3.708 41.371 3.726 41.411 ;
     RECT  2.304 40.061 2.697 41.419 ;
     RECT  38.772 41.279 38.79 41.477 ;
     RECT  56.415 33.008 56.697 41.512 ;
     RECT  67.215 33.008 67.497 41.512 ;
     RECT  78.015 33.008 78.297 41.512 ;
     RECT  56.304 41.512 56.697 41.549 ;
     RECT  67.104 41.512 67.497 41.549 ;
     RECT  77.904 41.512 78.297 41.549 ;
     RECT  7.815 40.445 8.097 41.791 ;
     RECT  34.2 40.063 35.097 41.819 ;
     RECT  6.264 41.099 6.354 41.909 ;
     RECT  7.815 41.791 8.19 41.909 ;
     RECT  6.336 41.909 6.354 41.917 ;
     RECT  10.764 41.881 10.782 41.917 ;
     RECT  40.215 41.251 44.478 41.917 ;
     RECT  6.336 41.917 6.39 41.945 ;
     RECT  38.808 41.881 38.826 41.981 ;
     RECT  2.304 41.419 2.862 41.995 ;
     RECT  39.996 41.917 44.478 42.025 ;
     RECT  45.615 38.141 45.897 42.025 ;
     RECT  10.764 41.917 10.854 42.053 ;
     RECT  10.836 42.053 10.854 42.089 ;
     RECT  39.996 42.025 45.897 42.449 ;
     RECT  4.824 41.611 4.842 42.565 ;
     RECT  4.68 42.565 4.842 42.593 ;
     RECT  2.304 41.995 3.33 42.601 ;
     RECT  41.616 42.449 45.897 42.629 ;
     RECT  86.292 42.283 86.31 42.701 ;
     RECT  2.304 42.601 3.546 42.715 ;
     RECT  4.68 42.593 4.698 42.715 ;
     RECT  2.304 42.715 4.698 42.719 ;
     RECT  0.108 40.792 0.126 42.749 ;
     RECT  42.732 42.629 45.897 42.763 ;
     RECT  42.732 42.763 45.99 42.893 ;
     RECT  4.068 42.719 4.698 43.025 ;
     RECT  6.372 41.945 6.39 43.025 ;
     RECT  38.772 42.421 38.79 43.051 ;
     RECT  7.815 41.909 8.097 43.069 ;
     RECT  7.38 43.069 8.097 43.169 ;
     RECT  38.772 43.051 38.862 43.169 ;
     RECT  38.844 43.169 38.862 43.181 ;
     RECT  6.552 43.105 6.57 43.259 ;
     RECT  83.415 39.721 84.402 43.277 ;
     RECT  39.996 42.449 40.497 43.501 ;
     RECT  83.415 43.277 83.898 43.501 ;
     RECT  2.304 42.719 3.042 43.579 ;
     RECT  41.616 42.629 41.958 43.645 ;
     RECT  42.732 42.893 45.897 43.645 ;
     RECT  4.5 43.025 4.698 43.771 ;
     RECT  5.544 43.681 5.562 43.771 ;
     RECT  46.764 43.681 46.782 43.771 ;
     RECT  4.5 43.771 5.562 43.799 ;
     RECT  2.304 43.579 3.582 43.835 ;
     RECT  46.764 43.771 46.854 43.835 ;
     RECT  46.764 43.835 46.782 43.871 ;
     RECT  39.924 43.501 40.497 44.041 ;
     RECT  2.415 43.835 3.582 44.221 ;
     RECT  6.948 44.185 6.966 44.237 ;
     RECT  2.415 44.221 3.726 44.383 ;
     RECT  39.924 44.041 40.554 44.383 ;
     RECT  41.616 43.645 45.897 44.383 ;
     RECT  38.772 44.311 38.79 44.411 ;
     RECT  2.415 44.383 4.014 44.581 ;
     RECT  39.924 44.383 45.897 44.581 ;
     RECT  39.888 44.581 45.897 44.609 ;
     RECT  83.232 43.501 83.898 44.717 ;
     RECT  5.22 43.799 5.238 44.761 ;
     RECT  7.815 43.169 8.097 44.761 ;
     RECT  2.415 44.581 4.23 44.789 ;
     RECT  6.84 44.761 6.93 44.879 ;
     RECT  4.14 44.789 4.23 44.915 ;
     RECT  6.84 44.879 6.858 44.915 ;
     RECT  34.815 41.819 35.097 44.923 ;
     RECT  7.815 44.761 8.586 44.951 ;
     RECT  7.815 44.951 8.097 44.971 ;
     RECT  7.596 44.971 8.097 45.023 ;
     RECT  83.415 44.717 83.898 45.121 ;
     RECT  46.764 45.121 46.782 45.157 ;
     RECT  42.804 44.609 45.897 45.185 ;
     RECT  5.076 44.761 5.238 45.229 ;
     RECT  46.764 45.157 46.818 45.257 ;
     RECT  4.212 44.915 4.23 45.301 ;
     RECT  5.076 45.229 5.778 45.301 ;
     RECT  46.8 45.257 46.818 45.329 ;
     RECT  2.415 44.789 3.33 45.403 ;
     RECT  2.304 45.403 3.33 45.419 ;
     RECT  4.212 45.301 5.778 45.595 ;
     RECT  6.768 45.463 6.786 45.595 ;
     RECT  4.212 45.595 6.786 45.599 ;
     RECT  34.776 44.923 35.097 45.761 ;
     RECT  42.804 45.185 44.838 45.769 ;
     RECT  56.415 41.549 56.697 45.832 ;
     RECT  67.215 41.549 67.497 45.832 ;
     RECT  78.015 41.549 78.297 45.832 ;
     RECT  38.196 44.851 38.214 45.841 ;
     RECT  38.196 45.841 38.79 45.869 ;
     RECT  39.888 44.609 41.634 45.869 ;
     RECT  4.212 45.599 6.462 45.931 ;
     RECT  40.215 45.869 41.634 45.959 ;
     RECT  3.996 45.931 6.462 45.995 ;
     RECT  38.772 45.869 38.79 46.031 ;
     RECT  42.768 45.769 44.838 46.111 ;
     RECT  45.615 45.185 45.897 46.111 ;
     RECT  4.68 45.995 6.462 46.157 ;
     RECT  41.328 45.959 41.634 46.201 ;
     RECT  4.68 46.157 5.958 46.229 ;
     RECT  46.728 46.267 46.746 46.397 ;
     RECT  4.68 46.229 5.166 46.409 ;
     RECT  56.304 45.832 56.697 46.409 ;
     RECT  67.104 45.832 67.497 46.409 ;
     RECT  77.904 45.832 78.297 46.409 ;
     RECT  2.304 45.419 2.697 46.459 ;
     RECT  41.328 46.201 41.67 46.471 ;
     RECT  42.768 46.111 45.897 46.471 ;
     RECT  3.492 46.615 3.51 46.685 ;
     RECT  83.415 45.121 84.402 46.685 ;
     RECT  41.328 46.471 45.897 46.769 ;
     RECT  2.268 46.459 2.697 46.805 ;
     RECT  2.304 46.805 2.697 46.849 ;
     RECT  5.94 46.229 5.958 46.921 ;
     RECT  5.94 46.921 5.994 46.949 ;
     RECT  46.764 46.813 46.782 46.949 ;
     RECT  41.616 46.769 45.897 47.039 ;
     RECT  0.108 46.939 0.126 47.069 ;
     RECT  7.815 45.023 8.097 47.191 ;
     RECT  83.415 46.685 83.898 47.261 ;
     RECT  2.304 46.849 3.474 47.309 ;
     RECT  7.815 47.191 8.874 47.309 ;
     RECT  40.215 45.959 40.554 47.309 ;
     RECT  4.572 46.747 4.59 47.317 ;
     RECT  4.428 47.317 4.59 47.345 ;
     RECT  41.652 47.039 45.897 47.821 ;
     RECT  86.292 47.419 86.31 47.837 ;
     RECT  4.428 47.345 4.518 47.995 ;
     RECT  5.976 46.949 5.994 48.001 ;
     RECT  56.415 46.409 56.697 48.091 ;
     RECT  67.215 46.409 67.497 48.091 ;
     RECT  78.015 46.409 78.297 48.091 ;
     RECT  5.976 48.001 6.138 48.127 ;
     RECT  56.304 48.091 56.697 48.128 ;
     RECT  67.104 48.091 67.497 48.128 ;
     RECT  77.904 48.091 78.297 48.128 ;
     RECT  4.14 47.995 4.518 48.155 ;
     RECT  2.304 47.309 3.366 48.191 ;
     RECT  7.815 47.309 8.19 48.389 ;
     RECT  83.415 47.261 83.826 48.413 ;
     RECT  5.832 48.127 6.138 48.475 ;
     RECT  5.832 48.475 6.642 48.541 ;
     RECT  2.304 48.191 3.15 48.659 ;
     RECT  4.572 48.271 4.734 48.659 ;
     RECT  38.772 46.777 38.79 48.731 ;
     RECT  5.688 48.541 6.642 48.739 ;
     RECT  5.688 48.739 6.786 48.811 ;
     RECT  7.815 48.389 8.097 48.811 ;
     RECT  5.4 48.811 6.786 48.929 ;
     RECT  40.215 47.309 40.497 48.937 ;
     RECT  2.304 48.659 2.826 48.965 ;
     RECT  6.624 48.929 6.786 48.965 ;
     RECT  41.616 47.821 45.897 48.965 ;
     RECT  5.4 48.929 5.778 49.001 ;
     RECT  4.572 48.659 4.59 49.003 ;
     RECT  3.996 49.003 4.59 49.051 ;
     RECT  5.544 49.001 5.778 49.073 ;
     RECT  3.564 49.051 4.59 49.085 ;
     RECT  3.564 49.085 4.554 49.199 ;
     RECT  3.996 49.199 4.554 49.235 ;
     RECT  7.632 48.811 8.097 49.243 ;
     RECT  40.215 48.937 40.554 49.243 ;
     RECT  41.616 48.965 42.246 49.243 ;
     RECT  6.912 49.243 8.097 49.475 ;
     RECT  2.415 48.965 2.826 49.531 ;
     RECT  40.215 49.243 42.246 49.711 ;
     RECT  43.056 48.965 45.897 49.711 ;
     RECT  2.415 49.531 3.114 49.775 ;
     RECT  38.808 49.747 38.826 49.783 ;
     RECT  38.808 49.783 38.898 49.847 ;
     RECT  4.536 49.235 4.554 49.855 ;
     RECT  4.536 49.855 4.698 50.008 ;
     RECT  38.88 49.847 38.898 50.081 ;
     RECT  6.84 49.783 6.858 50.125 ;
     RECT  4.392 50.008 4.698 50.155 ;
     RECT  7.815 49.475 8.097 50.161 ;
     RECT  6.768 50.125 6.858 50.251 ;
     RECT  7.815 50.161 8.766 50.251 ;
     RECT  4.32 50.155 4.698 50.279 ;
     RECT  40.215 49.711 45.897 50.287 ;
     RECT  2.415 49.775 2.826 50.333 ;
     RECT  6.768 50.251 8.766 50.351 ;
     RECT  5.76 49.073 5.778 50.395 ;
     RECT  6.768 50.351 8.097 50.459 ;
     RECT  83.415 48.413 83.697 50.521 ;
     RECT  2.415 50.333 2.697 50.539 ;
     RECT  5.652 50.395 5.778 50.549 ;
     RECT  5.76 50.549 5.778 50.683 ;
     RECT  56.415 48.128 56.697 50.683 ;
     RECT  67.215 48.128 67.497 50.683 ;
     RECT  78.015 48.128 78.297 50.683 ;
     RECT  7.2 50.459 8.097 50.717 ;
     RECT  56.304 50.683 56.697 50.729 ;
     RECT  67.104 50.683 67.497 50.729 ;
     RECT  77.904 50.683 78.297 50.729 ;
     RECT  39.924 50.287 45.897 50.819 ;
     RECT  32.544 50.731 32.562 51.089 ;
     RECT  5.76 50.683 5.994 51.125 ;
     RECT  10.8 51.061 10.818 51.161 ;
     RECT  33.66 51.241 33.678 51.293 ;
     RECT  7.56 50.717 8.097 51.359 ;
     RECT  4.932 50.701 4.95 51.367 ;
     RECT  5.76 51.125 5.778 51.367 ;
     RECT  3.996 51.067 4.014 51.395 ;
     RECT  46.764 50.587 46.782 51.533 ;
     RECT  2.304 50.539 2.697 51.637 ;
     RECT  4.932 51.367 5.778 51.665 ;
     RECT  2.304 51.637 3.186 51.739 ;
     RECT  0.108 51.547 0.126 51.869 ;
     RECT  38.196 51.367 38.214 51.907 ;
     RECT  2.304 51.739 3.294 51.935 ;
     RECT  41.436 50.819 45.897 51.935 ;
     RECT  7.704 51.359 8.097 52.079 ;
     RECT  83.415 50.521 84.114 52.109 ;
     RECT  4.032 51.835 4.698 52.169 ;
     RECT  6.84 51.871 6.858 52.169 ;
     RECT  41.436 51.935 41.454 52.169 ;
     RECT  5.508 51.665 5.778 52.249 ;
     RECT  56.415 50.729 56.697 52.312 ;
     RECT  67.215 50.729 67.497 52.312 ;
     RECT  78.015 50.729 78.297 52.312 ;
     RECT  83.415 52.109 83.826 52.315 ;
     RECT  39.924 50.819 40.497 52.321 ;
     RECT  56.304 52.312 56.697 52.349 ;
     RECT  67.104 52.312 67.497 52.349 ;
     RECT  77.904 52.312 78.297 52.349 ;
     RECT  83.304 52.315 83.826 52.355 ;
     RECT  5.508 52.249 6.318 52.439 ;
     RECT  86.292 51.739 86.31 52.685 ;
     RECT  38.196 51.907 38.79 52.709 ;
     RECT  42.408 51.935 45.897 52.709 ;
     RECT  2.304 51.935 2.697 52.861 ;
     RECT  83.415 52.355 83.826 52.973 ;
     RECT  5.544 52.439 6.102 52.979 ;
     RECT  39.924 52.321 41.058 52.987 ;
     RECT  2.304 52.861 2.862 53.015 ;
     RECT  4.68 52.169 4.698 53.083 ;
     RECT  7.815 52.079 8.097 53.131 ;
     RECT  34.815 45.761 35.097 53.221 ;
     RECT  46.728 53.083 46.746 53.261 ;
     RECT  2.415 53.015 2.862 53.401 ;
     RECT  39.924 52.987 41.418 53.491 ;
     RECT  2.415 53.401 3.15 53.519 ;
     RECT  7.815 53.131 8.298 53.519 ;
     RECT  9.108 53.401 9.126 53.519 ;
     RECT  7.815 53.519 8.154 53.555 ;
     RECT  4.464 53.083 4.698 53.563 ;
     RECT  2.415 53.519 3.078 53.591 ;
     RECT  42.768 52.709 45.897 53.591 ;
     RECT  0.54 53.527 0.558 53.645 ;
     RECT  38.772 52.709 38.79 53.789 ;
     RECT  2.415 53.591 2.697 53.851 ;
     RECT  39.924 53.491 41.958 53.861 ;
     RECT  4.464 53.563 5.058 53.869 ;
     RECT  5.868 52.979 6.102 53.869 ;
     RECT  6.84 53.401 6.858 53.869 ;
     RECT  41.4 53.861 41.958 53.869 ;
     RECT  5.868 53.869 6.858 53.941 ;
     RECT  34.2 53.221 35.097 53.969 ;
     RECT  4.176 53.869 5.058 54.059 ;
     RECT  5.832 53.941 6.966 54.067 ;
     RECT  2.304 53.851 2.697 54.095 ;
     RECT  4.176 54.059 4.914 54.095 ;
     RECT  4.176 54.095 4.554 54.139 ;
     RECT  41.4 53.869 42.03 54.329 ;
     RECT  2.415 54.095 2.697 54.337 ;
     RECT  3.996 54.139 4.554 54.365 ;
     RECT  2.415 54.337 2.826 54.481 ;
     RECT  2.415 54.481 3.402 54.599 ;
     RECT  39.924 53.861 40.497 54.599 ;
     RECT  4.536 54.365 4.554 54.671 ;
     RECT  5.832 54.067 7.002 54.751 ;
     RECT  5.76 54.751 7.002 54.841 ;
     RECT  7.815 53.555 8.097 54.841 ;
     RECT  2.415 54.599 3.078 54.905 ;
     RECT  2.415 54.905 2.697 54.907 ;
     RECT  41.616 54.329 42.03 54.949 ;
     RECT  42.84 53.591 45.897 54.949 ;
     RECT  5.76 54.841 8.097 54.985 ;
     RECT  5.688 54.985 8.097 55.013 ;
     RECT  6.804 55.013 8.097 55.049 ;
     RECT  39.96 54.599 40.497 55.381 ;
     RECT  6.804 55.049 6.822 55.517 ;
     RECT  4.032 55.147 4.05 55.561 ;
     RECT  3.636 55.561 4.05 55.679 ;
     RECT  39.96 55.381 40.554 55.679 ;
     RECT  3.996 55.679 4.05 55.831 ;
     RECT  5.688 55.013 5.706 55.831 ;
     RECT  46.764 55.723 46.782 55.853 ;
     RECT  83.415 52.973 83.697 55.921 ;
     RECT  40.176 55.679 40.554 55.949 ;
     RECT  83.415 55.921 83.754 55.993 ;
     RECT  3.996 55.831 4.338 56.065 ;
     RECT  5.112 55.831 5.706 56.065 ;
     RECT  39.024 54.571 39.042 56.129 ;
     RECT  7.815 55.049 8.097 56.191 ;
     RECT  3.996 56.065 5.706 56.255 ;
     RECT  0.108 56.203 0.126 56.333 ;
     RECT  4.104 56.255 5.706 56.399 ;
     RECT  7.815 56.191 8.154 56.399 ;
     RECT  4.896 56.399 5.706 56.429 ;
     RECT  83.415 55.993 83.79 56.429 ;
     RECT  2.304 54.907 2.697 56.569 ;
     RECT  56.415 52.349 56.697 56.632 ;
     RECT  67.215 52.349 67.497 56.632 ;
     RECT  78.015 52.349 78.297 56.632 ;
     RECT  83.415 56.429 83.697 56.635 ;
     RECT  2.304 56.569 3.042 56.683 ;
     RECT  2.268 56.683 3.042 56.759 ;
     RECT  4.104 56.399 4.122 56.759 ;
     RECT  5.04 56.429 5.706 56.759 ;
     RECT  40.215 55.949 40.554 56.759 ;
     RECT  2.268 56.759 2.697 56.795 ;
     RECT  5.148 56.759 5.706 56.803 ;
     RECT  5.148 56.803 5.742 56.831 ;
     RECT  41.616 54.949 45.897 57.001 ;
     RECT  5.724 56.831 5.742 57.181 ;
     RECT  5.724 57.181 5.778 57.209 ;
     RECT  56.304 56.632 56.697 57.209 ;
     RECT  67.104 56.632 67.497 57.209 ;
     RECT  77.904 56.632 78.297 57.209 ;
     RECT  83.304 56.635 83.697 57.209 ;
     RECT  41.4 57.001 45.897 57.299 ;
     RECT  38.808 56.767 38.826 57.307 ;
     RECT  38.772 57.307 38.826 57.407 ;
     RECT  6.912 55.915 7.074 57.485 ;
     RECT  40.215 56.759 40.497 57.541 ;
     RECT  4.572 57.685 4.59 57.725 ;
     RECT  42.192 57.299 45.897 57.725 ;
     RECT  86.292 56.875 86.31 57.821 ;
     RECT  45.615 57.725 45.897 57.883 ;
     RECT  2.304 56.795 2.697 57.991 ;
     RECT  5.76 57.209 5.778 57.991 ;
     RECT  83.415 57.209 83.697 57.991 ;
     RECT  45.615 57.883 45.99 58.013 ;
     RECT  5.76 57.991 5.922 58.081 ;
     RECT  41.4 57.299 41.418 58.081 ;
     RECT  42.192 57.725 44.694 58.081 ;
     RECT  5.688 58.081 5.922 58.109 ;
     RECT  83.415 57.991 83.79 58.109 ;
     RECT  7.815 56.399 8.097 58.123 ;
     RECT  4.032 57.979 4.05 58.219 ;
     RECT  56.415 57.209 56.697 58.351 ;
     RECT  67.215 57.209 67.497 58.351 ;
     RECT  78.015 57.209 78.297 58.351 ;
     RECT  38.808 57.407 38.826 58.379 ;
     RECT  46.728 58.219 46.746 58.397 ;
     RECT  56.304 58.351 56.697 58.397 ;
     RECT  67.104 58.351 67.497 58.397 ;
     RECT  77.904 58.351 78.297 58.397 ;
     RECT  3.996 58.219 4.05 58.415 ;
     RECT  5.688 58.109 5.778 58.531 ;
     RECT  7.596 58.123 8.097 58.621 ;
     RECT  5.148 58.531 5.778 58.649 ;
     RECT  41.4 58.081 44.694 58.693 ;
     RECT  45.615 58.013 45.897 58.693 ;
     RECT  5.688 58.649 5.778 58.733 ;
     RECT  2.304 57.991 2.862 58.801 ;
     RECT  7.524 58.621 8.097 58.801 ;
     RECT  2.304 58.801 3.258 58.919 ;
     RECT  2.304 58.919 2.862 59.063 ;
     RECT  40.215 57.541 40.554 59.071 ;
     RECT  7.164 58.801 8.097 59.179 ;
     RECT  4.464 58.693 4.914 59.189 ;
     RECT  6.984 59.179 8.097 59.189 ;
     RECT  41.4 58.693 45.897 59.189 ;
     RECT  6.984 59.189 7.002 59.225 ;
     RECT  4.464 59.189 4.698 59.275 ;
     RECT  38.808 59.197 38.826 59.467 ;
     RECT  38.772 59.467 38.826 59.567 ;
     RECT  5.688 58.733 5.706 59.605 ;
     RECT  4.14 59.275 4.698 59.729 ;
     RECT  2.415 59.063 2.862 59.755 ;
     RECT  4.14 59.729 4.59 59.845 ;
     RECT  5.688 59.605 5.85 59.845 ;
     RECT  5.688 59.845 5.922 59.881 ;
     RECT  6.912 59.881 6.93 59.999 ;
     RECT  5.616 59.881 5.922 60.035 ;
     RECT  2.415 59.755 2.97 60.043 ;
     RECT  41.436 59.189 45.897 60.125 ;
     RECT  3.888 59.845 4.59 60.317 ;
     RECT  40.215 59.071 40.59 60.421 ;
     RECT  41.436 60.125 42.39 60.421 ;
     RECT  2.304 60.043 2.97 60.427 ;
     RECT  32.76 58.621 32.778 60.449 ;
     RECT  4.572 60.317 4.59 60.461 ;
     RECT  7.815 59.189 8.097 60.523 ;
     RECT  2.304 60.427 3.366 60.539 ;
     RECT  6.264 60.241 6.282 60.539 ;
     RECT  40.215 60.421 42.39 60.539 ;
     RECT  38.808 59.567 38.826 60.547 ;
     RECT  7.704 60.523 8.097 60.575 ;
     RECT  7.815 60.575 8.097 60.583 ;
     RECT  38.808 60.547 38.862 60.583 ;
     RECT  7.815 60.583 8.694 60.719 ;
     RECT  38.772 60.583 38.862 60.719 ;
     RECT  38.808 60.719 38.862 60.809 ;
     RECT  41.436 60.539 42.39 60.809 ;
     RECT  38.844 60.809 38.862 60.917 ;
     RECT  56.415 58.397 56.697 60.952 ;
     RECT  67.215 58.397 67.497 60.952 ;
     RECT  78.015 58.397 78.297 60.952 ;
     RECT  5.508 60.523 5.526 61.003 ;
     RECT  5.364 61.003 5.526 61.051 ;
     RECT  83.415 58.109 83.697 61.051 ;
     RECT  5.364 61.051 5.994 61.079 ;
     RECT  83.415 61.051 83.79 61.277 ;
     RECT  40.215 60.539 40.59 61.321 ;
     RECT  5.508 61.079 5.994 61.349 ;
     RECT  39.924 61.321 40.59 61.349 ;
     RECT  83.415 61.277 83.697 61.483 ;
     RECT  56.304 60.952 56.697 61.529 ;
     RECT  67.104 60.952 67.497 61.529 ;
     RECT  77.904 60.952 78.297 61.529 ;
     RECT  83.304 61.483 83.697 61.529 ;
     RECT  3.996 61.387 4.014 61.591 ;
     RECT  5.724 61.349 5.994 61.619 ;
     RECT  3.996 61.591 4.302 61.655 ;
     RECT  0.108 61.291 0.126 61.949 ;
     RECT  4.14 61.655 4.302 62.131 ;
     RECT  5.724 61.619 5.742 62.131 ;
     RECT  4.14 62.131 5.742 62.159 ;
     RECT  43.128 60.125 45.897 62.203 ;
     RECT  38.772 62.167 38.79 62.267 ;
     RECT  83.415 61.529 83.697 62.311 ;
     RECT  43.128 62.203 45.99 62.333 ;
     RECT  83.415 62.311 83.79 62.429 ;
     RECT  41.616 60.809 42.39 62.509 ;
     RECT  43.128 62.333 45.897 62.509 ;
     RECT  4.14 62.159 5.31 62.671 ;
     RECT  67.215 61.529 67.497 62.671 ;
     RECT  78.015 61.529 78.297 62.671 ;
     RECT  51.015 2.413 51.297 62.683 ;
     RECT  77.904 62.671 78.297 62.683 ;
     RECT  6.516 62.545 6.534 62.707 ;
     RECT  46.656 62.671 46.746 62.717 ;
     RECT  66.708 62.671 67.497 62.717 ;
     RECT  3.816 62.671 5.31 62.731 ;
     RECT  3.672 62.731 5.31 62.735 ;
     RECT  46.728 62.717 46.746 62.813 ;
     RECT  50.724 62.683 51.297 62.813 ;
     RECT  58.68 62.683 58.698 62.813 ;
     RECT  70.704 62.683 70.722 62.813 ;
     RECT  74.664 62.683 74.682 62.813 ;
     RECT  77.904 62.683 78.678 62.813 ;
     RECT  82.62 62.683 82.638 62.813 ;
     RECT  86.292 61.723 86.31 62.813 ;
     RECT  6.336 62.707 6.534 62.851 ;
     RECT  3.672 62.735 5.13 62.969 ;
     RECT  7.815 60.719 8.097 63.013 ;
     RECT  38.808 62.977 38.826 63.013 ;
     RECT  38.808 63.013 38.898 63.077 ;
     RECT  6.336 62.851 6.786 63.085 ;
     RECT  41.616 62.509 45.897 63.085 ;
     RECT  2.304 60.539 2.862 63.149 ;
     RECT  56.415 61.529 56.697 63.211 ;
     RECT  2.304 63.149 2.718 63.239 ;
     RECT  4.464 62.969 5.13 63.239 ;
     RECT  5.904 63.085 6.786 63.239 ;
     RECT  7.815 63.013 8.478 63.239 ;
     RECT  10.764 63.121 10.854 63.239 ;
     RECT  39.924 61.349 40.497 63.239 ;
     RECT  46.764 63.067 46.782 63.245 ;
     RECT  7.815 63.239 8.334 63.248 ;
     RECT  56.304 63.211 56.697 63.248 ;
     RECT  67.104 62.717 67.497 63.248 ;
     RECT  77.904 62.813 78.297 63.248 ;
     RECT  4.464 63.239 4.734 63.275 ;
     RECT  6.336 63.239 6.354 63.275 ;
     RECT  7.815 63.248 8.262 63.275 ;
     RECT  10.764 63.239 10.782 63.275 ;
     RECT  38.88 63.077 38.898 63.275 ;
     RECT  39.96 63.239 40.497 63.275 ;
     RECT  4.464 63.275 4.482 63.389 ;
     RECT  4.14 63.751 4.158 64.201 ;
     RECT  7.815 63.275 8.097 64.201 ;
     RECT  3.996 64.201 4.518 64.315 ;
     RECT  5.436 64.165 5.454 64.315 ;
     RECT  40.215 63.275 40.497 64.327 ;
     RECT  41.508 63.085 45.897 64.327 ;
     RECT  7.815 64.201 8.514 64.589 ;
     RECT  40.215 64.327 45.897 64.597 ;
     RECT  9.324 64.669 9.342 64.769 ;
     RECT  3.996 64.315 5.454 64.831 ;
     RECT  2.304 63.239 2.697 64.895 ;
     RECT  2.34 64.895 2.697 64.967 ;
     RECT  39.924 64.597 45.897 64.973 ;
     RECT  3.996 64.831 5.49 64.987 ;
     RECT  3.996 64.987 5.814 65.021 ;
     RECT  39.924 64.973 42.21 65.129 ;
     RECT  2.415 64.967 2.697 65.131 ;
     RECT  5.472 65.021 5.814 65.273 ;
     RECT  3.996 65.021 4.554 65.309 ;
     RECT  2.415 65.131 2.754 65.371 ;
     RECT  5.544 65.273 5.814 65.407 ;
     RECT  6.84 64.669 6.858 65.407 ;
     RECT  4.176 65.309 4.554 65.453 ;
     RECT  10.764 65.281 10.782 65.471 ;
     RECT  7.815 64.589 8.37 65.501 ;
     RECT  7.815 65.501 8.19 65.543 ;
     RECT  83.415 62.429 83.697 65.551 ;
     RECT  2.415 65.371 2.934 65.749 ;
     RECT  56.415 63.248 56.697 65.803 ;
     RECT  67.215 63.248 67.497 65.803 ;
     RECT  78.015 63.248 78.297 65.803 ;
     RECT  56.304 65.803 56.697 65.849 ;
     RECT  67.104 65.803 67.497 65.849 ;
     RECT  77.904 65.803 78.297 65.849 ;
     RECT  2.415 65.749 3.222 65.899 ;
     RECT  2.304 65.899 3.222 65.939 ;
     RECT  5.544 65.407 6.858 65.975 ;
     RECT  36.504 64.021 36.522 66.209 ;
     RECT  6.012 65.975 6.858 66.323 ;
     RECT  4.248 65.453 4.554 66.361 ;
     RECT  39.924 65.129 42.174 66.361 ;
     RECT  42.984 64.973 45.897 66.361 ;
     RECT  2.304 65.939 2.697 66.427 ;
     RECT  7.815 65.543 8.097 66.451 ;
     RECT  6.66 66.323 6.858 66.479 ;
     RECT  7.776 66.451 8.097 66.509 ;
     RECT  6.66 66.479 6.678 66.515 ;
     RECT  39.924 66.361 45.897 66.523 ;
     RECT  2.016 66.427 2.697 66.623 ;
     RECT  39.924 66.523 45.99 66.653 ;
     RECT  83.415 65.551 83.79 66.701 ;
     RECT  3.96 66.361 4.554 66.721 ;
     RECT  3.96 66.721 4.878 66.991 ;
     RECT  39.924 66.653 45.897 67.019 ;
     RECT  38.772 65.137 38.79 67.027 ;
     RECT  3.708 66.991 4.878 67.091 ;
     RECT  2.268 66.623 2.697 67.127 ;
     RECT  3.708 67.091 3.798 67.199 ;
     RECT  3.78 67.199 3.798 67.277 ;
     RECT  4.86 67.091 4.878 67.277 ;
     RECT  40.215 67.019 45.897 67.289 ;
     RECT  86.292 66.859 86.31 67.397 ;
     RECT  5.796 67.243 5.814 67.441 ;
     RECT  7.815 66.509 8.097 67.441 ;
     RECT  56.415 65.849 56.697 67.531 ;
     RECT  67.215 65.849 67.497 67.531 ;
     RECT  78.015 65.849 78.297 67.531 ;
     RECT  40.215 67.289 41.346 67.559 ;
     RECT  56.304 67.531 56.697 67.568 ;
     RECT  67.104 67.531 67.497 67.568 ;
     RECT  77.904 67.531 78.297 67.568 ;
     RECT  2.304 67.127 2.697 67.595 ;
     RECT  5.796 67.441 6.246 67.595 ;
     RECT  6.228 67.595 6.246 67.739 ;
     RECT  7.815 67.441 8.298 67.829 ;
     RECT  7.815 67.829 8.154 67.865 ;
     RECT  38.772 67.027 39.366 67.873 ;
     RECT  38.772 67.873 39.402 67.901 ;
     RECT  85.5 65.371 85.518 68.429 ;
     RECT  41.292 67.559 41.346 68.639 ;
     RECT  41.292 68.639 41.31 69.179 ;
     RECT  2.415 67.595 2.697 69.211 ;
     RECT  42.192 67.289 45.897 69.251 ;
     RECT  2.415 69.211 2.79 69.601 ;
     RECT  37.908 69.421 37.926 69.691 ;
     RECT  39.348 67.901 39.402 69.719 ;
     RECT  2.415 69.601 3.402 69.787 ;
     RECT  39.348 69.719 39.366 69.989 ;
     RECT  43.38 69.251 45.897 70.025 ;
     RECT  42.192 69.251 42.318 70.069 ;
     RECT  2.304 69.787 3.402 70.141 ;
     RECT  7.815 67.865 8.097 70.141 ;
     RECT  10.8 70.141 10.818 70.258 ;
     RECT  10.8 70.258 10.854 70.259 ;
     RECT  6.264 69.961 6.282 70.261 ;
     RECT  7.452 70.141 8.097 70.261 ;
     RECT  2.304 70.141 3.582 70.295 ;
     RECT  6.264 70.261 8.154 70.301 ;
     RECT  6.264 70.301 6.282 70.439 ;
     RECT  7.452 70.301 8.154 70.439 ;
     RECT  10.836 70.259 10.854 70.439 ;
     RECT  40.215 67.559 40.497 70.501 ;
     RECT  3.672 70.501 3.69 70.673 ;
     RECT  83.415 66.701 83.697 70.681 ;
     RECT  83.415 70.681 83.754 70.771 ;
     RECT  4.464 69.979 4.482 70.973 ;
     RECT  46.764 70.843 46.782 70.973 ;
     RECT  42.192 70.069 42.786 71.105 ;
     RECT  2.304 70.295 2.697 71.179 ;
     RECT  43.596 70.025 45.897 71.221 ;
     RECT  4.572 71.221 4.59 71.339 ;
     RECT  42.192 71.105 42.498 71.375 ;
     RECT  7.815 70.439 8.154 71.383 ;
     RECT  2.304 71.179 3.186 71.491 ;
     RECT  83.415 70.771 83.79 71.549 ;
     RECT  6.804 71.383 6.822 71.609 ;
     RECT  7.815 71.383 8.406 71.609 ;
     RECT  7.815 71.609 8.154 71.753 ;
     RECT  10.332 71.311 10.35 71.761 ;
     RECT  83.415 71.549 83.697 71.845 ;
     RECT  10.332 71.761 10.458 71.851 ;
     RECT  56.415 67.568 56.697 71.851 ;
     RECT  67.215 67.568 67.497 71.851 ;
     RECT  78.015 67.568 78.297 71.851 ;
     RECT  37.872 69.691 37.926 71.879 ;
     RECT  83.304 71.845 83.697 71.885 ;
     RECT  56.304 71.851 56.697 71.888 ;
     RECT  67.104 71.851 67.497 71.888 ;
     RECT  77.904 71.851 78.297 71.888 ;
     RECT  2.304 71.491 3.366 72.031 ;
     RECT  4.248 71.803 4.266 72.121 ;
     RECT  5.004 71.455 5.022 72.121 ;
     RECT  86.292 71.995 86.31 72.125 ;
     RECT  2.304 72.031 3.51 72.149 ;
     RECT  0.108 72.043 0.126 72.173 ;
     RECT  4.248 72.121 5.058 72.265 ;
     RECT  4.248 72.265 5.778 72.419 ;
     RECT  37.872 71.879 37.89 72.455 ;
     RECT  43.524 71.221 45.897 72.523 ;
     RECT  6.696 72.301 6.714 72.571 ;
     RECT  43.524 72.523 45.99 72.571 ;
     RECT  43.344 72.571 45.99 72.701 ;
     RECT  2.304 72.149 3.366 72.907 ;
     RECT  42.444 71.375 42.498 72.931 ;
     RECT  43.344 72.701 45.897 72.931 ;
     RECT  2.304 72.907 3.474 72.959 ;
     RECT  6.696 72.571 6.93 72.995 ;
     RECT  4.464 72.419 5.778 73.067 ;
     RECT  5.616 73.067 5.778 73.309 ;
     RECT  4.464 73.067 4.842 73.381 ;
     RECT  40.176 70.501 40.497 73.409 ;
     RECT  0.108 73.339 0.126 73.469 ;
     RECT  3.852 73.381 4.842 73.499 ;
     RECT  5.616 73.309 5.922 73.499 ;
     RECT  41.292 70.267 41.31 73.499 ;
     RECT  4.356 73.499 4.842 73.535 ;
     RECT  5.76 73.499 5.778 73.535 ;
     RECT  6.876 72.995 6.93 73.535 ;
     RECT  6.912 73.535 6.93 73.643 ;
     RECT  42.444 72.931 45.897 73.805 ;
     RECT  2.304 72.959 2.697 74.075 ;
     RECT  43.344 73.805 45.897 74.075 ;
     RECT  43.524 74.075 45.897 74.381 ;
     RECT  42.444 73.805 42.462 74.461 ;
     RECT  0.108 74.539 0.126 74.615 ;
     RECT  4.536 73.535 4.842 74.635 ;
     RECT  2.415 74.075 2.697 74.821 ;
     RECT  42.12 74.461 42.462 74.821 ;
     RECT  4.212 74.635 4.842 74.827 ;
     RECT  2.415 74.821 2.79 74.861 ;
     RECT  7.02 73.651 7.038 75.001 ;
     RECT  7.815 71.753 8.097 75.001 ;
     RECT  2.415 74.861 2.697 75.019 ;
     RECT  4.212 74.827 5.238 75.127 ;
     RECT  6.192 74.683 6.21 75.127 ;
     RECT  4.212 75.127 6.21 75.155 ;
     RECT  7.02 75.001 8.097 75.191 ;
     RECT  83.415 71.885 83.697 75.361 ;
     RECT  41.616 74.821 42.462 75.425 ;
     RECT  41.616 75.425 41.634 75.497 ;
     RECT  82.656 75.433 82.674 75.533 ;
     RECT  43.56 74.381 45.897 75.541 ;
     RECT  40.215 73.409 40.497 75.631 ;
     RECT  2.304 75.019 2.697 75.691 ;
     RECT  0.108 75.547 0.126 75.725 ;
     RECT  4.824 75.155 5.022 75.821 ;
     RECT  40.215 75.631 41.058 75.929 ;
     RECT  2.304 75.691 2.862 75.965 ;
     RECT  5.76 75.155 5.778 75.965 ;
     RECT  83.415 75.361 84.402 76.061 ;
     RECT  42.444 75.425 42.462 76.081 ;
     RECT  43.344 75.541 45.897 76.081 ;
     RECT  38.772 75.937 38.79 76.199 ;
     RECT  80.388 75.631 80.406 76.301 ;
     RECT  83.415 76.061 83.697 76.441 ;
     RECT  42.444 76.081 45.897 76.505 ;
     RECT  83.232 76.441 83.697 76.513 ;
     RECT  82.656 76.513 83.697 76.589 ;
     RECT  46.728 76.513 46.746 76.613 ;
     RECT  82.656 76.589 82.674 76.829 ;
     RECT  10.332 71.851 10.53 77.161 ;
     RECT  7.815 75.191 8.097 77.251 ;
     RECT  10.332 77.161 10.818 77.251 ;
     RECT  44.028 76.505 45.897 77.251 ;
     RECT  4.824 75.821 4.842 77.279 ;
     RECT  2.304 75.965 2.697 77.315 ;
     RECT  10.044 77.251 10.818 77.323 ;
     RECT  7.02 75.191 7.038 77.351 ;
     RECT  9.684 77.323 10.818 77.359 ;
     RECT  7.815 77.251 8.766 77.387 ;
     RECT  9.684 77.359 10.854 77.395 ;
     RECT  8.856 77.395 10.854 77.423 ;
     RECT  2.34 77.315 2.697 77.431 ;
     RECT  10.044 77.423 10.854 77.459 ;
     RECT  2.34 77.431 2.934 78.061 ;
     RECT  42.444 76.505 42.462 78.241 ;
     RECT  67.215 71.888 67.497 78.331 ;
     RECT  78.015 71.888 78.297 78.331 ;
     RECT  67.104 78.331 67.497 78.368 ;
     RECT  77.904 78.331 78.297 78.368 ;
     RECT  54.72 78.331 54.738 78.461 ;
     RECT  42.444 78.241 42.786 78.467 ;
     RECT  43.524 77.251 45.897 78.509 ;
     RECT  5.796 78.091 5.814 78.511 ;
     RECT  42.768 78.467 42.786 78.539 ;
     RECT  43.524 78.509 44.19 78.539 ;
     RECT  5.472 78.511 5.814 78.571 ;
     RECT  14.796 78.331 14.814 78.601 ;
     RECT  43.524 78.539 44.154 78.601 ;
     RECT  86.292 78.475 86.31 78.605 ;
     RECT  5.472 78.571 5.85 78.619 ;
     RECT  14.796 78.601 15.822 78.619 ;
     RECT  14.436 78.619 15.822 78.629 ;
     RECT  56.415 71.888 56.697 78.637 ;
     RECT  8.856 77.423 9.162 78.665 ;
     RECT  14.436 78.629 14.454 78.665 ;
     RECT  43.38 78.601 44.154 78.665 ;
     RECT  8.856 78.665 8.982 78.701 ;
     RECT  15.408 78.629 15.822 78.701 ;
     RECT  10.44 77.459 10.53 78.709 ;
     RECT  58.284 78.331 58.302 78.709 ;
     RECT  55.512 78.709 55.53 78.745 ;
     RECT  4.536 78.571 4.554 78.781 ;
     RECT  5.472 78.619 6.138 78.781 ;
     RECT  55.512 78.745 55.602 78.781 ;
     RECT  56.415 78.637 57.402 78.781 ;
     RECT  10.44 78.709 10.926 78.809 ;
     RECT  2.34 78.061 3.042 78.811 ;
     RECT  4.536 78.781 6.138 78.899 ;
     RECT  10.908 78.809 10.926 78.899 ;
     RECT  15.408 78.701 15.426 78.899 ;
     RECT  55.512 78.781 57.402 78.899 ;
     RECT  4.536 78.899 4.662 78.907 ;
     RECT  2.304 78.811 3.042 78.935 ;
     RECT  2.415 78.935 3.042 78.943 ;
     RECT  4.14 78.907 4.662 78.943 ;
     RECT  8.964 78.701 8.982 78.971 ;
     RECT  46.656 78.871 46.746 79.007 ;
     RECT  0.108 78.475 0.126 79.015 ;
     RECT  43.38 78.665 44.118 79.043 ;
     RECT  55.584 78.899 57.402 79.051 ;
     RECT  58.176 78.709 58.302 79.051 ;
     RECT  43.38 79.043 43.974 79.079 ;
     RECT  43.38 79.079 43.398 79.169 ;
     RECT  46.728 79.007 46.746 79.169 ;
     RECT  55.584 79.051 58.302 79.169 ;
     RECT  82.656 78.511 82.674 79.169 ;
     RECT  82.476 79.177 82.494 79.229 ;
     RECT  5.472 78.899 5.49 79.241 ;
     RECT  55.584 79.169 55.602 79.241 ;
     RECT  83.415 76.589 83.697 79.321 ;
     RECT  83.376 79.321 83.697 79.439 ;
     RECT  85.464 79.435 85.482 79.475 ;
     RECT  56.34 79.169 58.302 79.555 ;
     RECT  59.436 79.447 59.454 79.555 ;
     RECT  6.804 79.483 6.822 79.583 ;
     RECT  56.34 79.555 58.338 79.591 ;
     RECT  59.22 79.555 59.454 79.591 ;
     RECT  0.108 79.015 0.162 79.613 ;
     RECT  2.415 78.943 4.662 79.681 ;
     RECT  56.34 79.591 59.454 79.681 ;
     RECT  2.415 79.681 4.734 79.753 ;
     RECT  2.415 79.753 5.382 79.781 ;
     RECT  61.815 28.211 62.097 79.951 ;
     RECT  2.415 79.781 4.59 79.979 ;
     RECT  5.364 79.781 5.382 79.979 ;
     RECT  61.815 79.951 62.622 79.987 ;
     RECT  85.5 79.951 85.518 79.987 ;
     RECT  4.068 79.979 4.41 80.015 ;
     RECT  4.068 80.015 4.086 80.051 ;
     RECT  56.34 79.681 59.886 80.285 ;
     RECT  2.415 79.979 3.114 80.357 ;
     RECT  56.34 80.285 56.697 80.357 ;
     RECT  85.5 79.987 85.59 80.491 ;
     RECT  83.415 79.439 83.697 80.527 ;
     RECT  84.924 80.491 85.59 80.527 ;
     RECT  57.636 80.285 59.634 80.555 ;
     RECT  57.636 80.555 58.698 80.591 ;
     RECT  59.616 80.555 59.634 80.627 ;
     RECT  61.815 79.987 62.694 80.627 ;
     RECT  61.815 80.627 62.622 80.699 ;
     RECT  83.415 80.527 85.59 80.909 ;
     RECT  0.108 79.613 0.126 81.005 ;
     RECT  83.415 80.909 85.518 81.149 ;
     RECT  2.415 80.357 3.042 81.175 ;
     RECT  57.672 80.591 58.698 81.365 ;
     RECT  57.672 81.365 57.726 81.473 ;
     RECT  2.376 81.175 3.114 81.499 ;
     RECT  2.304 81.499 3.114 81.571 ;
     RECT  78.015 78.368 78.297 81.607 ;
     RECT  79.236 81.337 79.254 81.607 ;
     RECT  57.708 81.473 57.726 81.635 ;
     RECT  58.68 81.365 58.698 81.635 ;
     RECT  2.304 81.571 3.15 81.679 ;
     RECT  82.044 81.547 82.062 81.679 ;
     RECT  78.015 81.607 79.254 81.707 ;
     RECT  85.5 81.149 85.518 81.725 ;
     RECT  58.86 81.643 58.878 81.779 ;
     RECT  2.304 81.679 3.222 81.841 ;
     RECT  82.044 81.679 82.674 81.869 ;
     RECT  81.144 79.483 81.162 81.877 ;
     RECT  81.144 81.877 81.738 81.917 ;
     RECT  79.236 81.707 79.254 81.965 ;
     RECT  83.415 81.149 84.402 82.493 ;
     RECT  2.304 81.841 3.258 82.525 ;
     RECT  82.656 81.869 82.674 82.781 ;
     RECT  81.144 81.917 81.162 83.227 ;
     RECT  2.268 82.525 3.258 83.399 ;
     RECT  0.108 82.957 0.126 83.453 ;
     RECT  2.268 83.399 3.114 83.489 ;
     RECT  2.268 83.489 3.006 83.561 ;
     RECT  2.268 83.561 2.826 83.597 ;
     RECT  2.268 83.597 2.754 83.633 ;
     RECT  2.268 83.633 2.697 83.693 ;
     RECT  81 83.227 81.162 83.759 ;
     RECT  85.464 83.611 85.482 83.759 ;
     RECT  2.304 83.693 2.697 83.795 ;
     RECT  2.376 83.795 2.697 83.981 ;
     RECT  2.415 83.981 2.697 83.987 ;
     RECT  7.815 77.387 8.097 83.987 ;
     RECT  13.215 2.413 13.497 83.987 ;
     RECT  18.615 2.413 18.897 83.987 ;
     RECT  24.015 2.413 24.297 83.987 ;
     RECT  29.415 2.413 29.697 83.987 ;
     RECT  34.815 53.969 35.097 83.987 ;
     RECT  40.215 75.929 40.497 83.987 ;
     RECT  45.615 78.509 45.897 83.987 ;
     RECT  51.015 62.813 51.297 83.987 ;
     RECT  56.415 80.357 56.697 83.987 ;
     RECT  61.815 80.699 62.097 83.987 ;
     RECT  67.215 78.368 67.497 83.987 ;
     RECT  72.615 2.413 72.897 83.987 ;
     RECT  78.015 81.707 78.297 83.987 ;
     RECT  83.415 82.493 83.697 83.987 ;
     RECT  2.415 83.987 2.505 84.257 ;
     RECT  7.815 83.987 7.905 84.257 ;
     RECT  13.215 83.987 13.305 84.257 ;
     RECT  18.615 83.987 18.705 84.257 ;
     RECT  24.015 83.987 24.105 84.257 ;
     RECT  29.415 83.987 29.505 84.257 ;
     RECT  34.815 83.987 34.905 84.257 ;
     RECT  40.215 83.987 40.305 84.257 ;
     RECT  45.615 83.987 45.705 84.257 ;
     RECT  51.015 83.987 51.105 84.257 ;
     RECT  56.415 83.987 56.505 84.257 ;
     RECT  61.815 83.987 61.905 84.257 ;
     RECT  67.215 83.987 67.305 84.257 ;
     RECT  72.615 83.987 72.705 84.257 ;
     RECT  78.015 83.987 78.105 84.257 ;
     RECT  83.415 83.987 83.505 84.257 ;
    LAYER M4 ;
     RECT  0.084 77.616 0.173 77.64 ;
     RECT  0.06 77.64 0.173 78.528 ;
     RECT  0.084 78.528 0.173 78.552 ;
     RECT  0.06 78.552 0.173 78.816 ;
     RECT  0.084 78.816 0.173 78.84 ;
     RECT  0.06 78.84 0.173 79.056 ;
     RECT  0.084 79.056 0.173 79.08 ;
     RECT  0.06 79.08 0.173 79.344 ;
     RECT  0.084 79.344 0.173 79.368 ;
     RECT  0.06 79.368 0.173 79.584 ;
     RECT  0.084 79.584 0.173 79.608 ;
     RECT  0.06 79.608 0.173 79.872 ;
     RECT  0.084 79.872 0.173 79.896 ;
     RECT  0.06 79.896 0.173 80.16 ;
     RECT  0.084 80.16 0.173 80.184 ;
     RECT  0.06 80.184 0.173 80.4 ;
     RECT  0.084 80.4 0.173 80.424 ;
     RECT  0.06 80.424 0.173 80.688 ;
     RECT  0.084 80.688 0.173 80.712 ;
     RECT  0.06 80.712 0.173 80.976 ;
     RECT  0.084 80.976 0.173 81 ;
     RECT  0.06 81 0.173 81.504 ;
     RECT  0.084 81.504 0.173 81.528 ;
     RECT  0.06 81.528 0.173 81.792 ;
     RECT  0.084 81.792 0.173 81.816 ;
     RECT  0.06 81.816 0.173 82.08 ;
     RECT  0.084 82.08 0.173 82.104 ;
     RECT  0.06 82.104 0.173 82.32 ;
     RECT  0.084 82.32 0.173 82.344 ;
     RECT  0.06 82.344 0.173 82.608 ;
     RECT  0.084 82.608 0.173 82.632 ;
     RECT  0.06 82.632 0.173 82.896 ;
     RECT  0.084 82.896 0.173 82.92 ;
     RECT  0.06 82.92 0.173 83.136 ;
     RECT  0.084 83.136 0.173 83.16 ;
     RECT  0.06 83.16 0.173 83.424 ;
     RECT  0.084 83.424 0.173 83.448 ;
     RECT  0.06 83.448 0.173 83.664 ;
     RECT  0.084 83.664 0.173 83.688 ;
     RECT  0.06 83.688 0.173 83.952 ;
     RECT  0.084 83.952 0.173 83.976 ;
     RECT  0.084 2.112 0.227 2.136 ;
     RECT  0.06 2.136 0.227 2.352 ;
     RECT  0.084 2.352 0.227 2.376 ;
     RECT  0.06 2.376 0.227 2.64 ;
     RECT  0.084 2.64 0.227 2.664 ;
     RECT  0.06 2.664 0.227 2.88 ;
     RECT  0.084 2.88 0.227 2.904 ;
     RECT  0.06 2.904 0.227 3.12 ;
     RECT  0.084 3.12 0.227 3.144 ;
     RECT  0.06 3.144 0.227 3.408 ;
     RECT  0.084 3.408 0.227 3.432 ;
     RECT  0.06 3.432 0.227 3.648 ;
     RECT  0.084 3.648 0.227 3.672 ;
     RECT  0.06 3.672 0.227 3.888 ;
     RECT  0.084 3.888 0.227 3.912 ;
     RECT  0.06 3.912 0.227 4.176 ;
     RECT  0.084 4.176 0.227 4.2 ;
     RECT  0.06 4.2 0.227 4.416 ;
     RECT  0.084 4.416 0.227 4.44 ;
     RECT  0.06 4.44 0.227 4.656 ;
     RECT  0.084 4.656 0.227 4.68 ;
     RECT  0.06 4.68 0.227 4.944 ;
     RECT  0.084 4.944 0.227 4.968 ;
     RECT  0.06 4.968 0.227 5.184 ;
     RECT  0.084 5.184 0.227 5.208 ;
     RECT  0.06 5.208 0.227 5.424 ;
     RECT  0.084 5.424 0.227 5.448 ;
     RECT  0.06 5.448 0.227 5.712 ;
     RECT  0.084 5.712 0.227 5.736 ;
     RECT  0.06 5.736 0.227 5.952 ;
     RECT  0.084 5.952 0.227 5.976 ;
     RECT  0.06 5.976 0.227 6.24 ;
     RECT  0.084 6.24 0.227 6.264 ;
     RECT  0.06 6.264 0.227 6.48 ;
     RECT  0.084 6.48 0.227 6.504 ;
     RECT  0.06 6.504 0.227 6.72 ;
     RECT  0.084 6.72 0.227 6.744 ;
     RECT  0.06 6.744 0.227 7.008 ;
     RECT  0.084 7.008 0.227 7.032 ;
     RECT  0.06 7.032 0.227 7.248 ;
     RECT  0.084 7.248 0.227 7.272 ;
     RECT  0.06 7.272 0.227 7.488 ;
     RECT  0.084 7.488 0.227 7.512 ;
     RECT  0.06 7.512 0.227 7.776 ;
     RECT  0.084 7.776 0.227 7.8 ;
     RECT  0.06 7.8 0.227 8.016 ;
     RECT  0.084 8.016 0.227 8.04 ;
     RECT  0.06 8.04 0.227 8.256 ;
     RECT  0.084 8.256 0.227 8.28 ;
     RECT  0.06 8.28 0.227 8.544 ;
     RECT  0.084 8.544 0.227 8.568 ;
     RECT  0.06 8.568 0.227 8.784 ;
     RECT  0.084 8.784 0.227 8.808 ;
     RECT  0.06 8.808 0.227 9.024 ;
     RECT  0.084 9.024 0.227 9.048 ;
     RECT  0.06 9.048 0.227 9.312 ;
     RECT  0.084 9.312 0.227 9.336 ;
     RECT  0.06 9.336 0.227 9.552 ;
     RECT  0.084 9.552 0.227 9.576 ;
     RECT  0.06 9.576 0.227 9.792 ;
     RECT  0.084 9.792 0.227 9.816 ;
     RECT  0.06 9.816 0.227 10.08 ;
     RECT  0.084 10.08 0.227 10.104 ;
     RECT  0.06 10.104 0.227 10.32 ;
     RECT  0.084 10.32 0.227 10.344 ;
     RECT  0.06 10.344 0.227 10.56 ;
     RECT  0.084 10.56 0.227 10.584 ;
     RECT  0.06 10.584 0.227 10.848 ;
     RECT  0.084 10.848 0.227 10.872 ;
     RECT  0.06 10.872 0.227 11.088 ;
     RECT  0.084 11.088 0.227 11.112 ;
     RECT  0.06 11.112 0.227 11.328 ;
     RECT  0.084 11.328 0.227 11.352 ;
     RECT  0.06 11.352 0.227 11.616 ;
     RECT  0.084 11.616 0.227 11.64 ;
     RECT  0.06 11.64 0.227 11.856 ;
     RECT  0.084 11.856 0.227 11.88 ;
     RECT  0.06 11.88 0.227 12.096 ;
     RECT  0.084 12.096 0.227 12.12 ;
     RECT  0.06 12.12 0.227 12.384 ;
     RECT  0.084 12.384 0.227 12.408 ;
     RECT  0.06 12.408 0.227 12.624 ;
     RECT  0.084 12.624 0.227 12.648 ;
     RECT  0.06 12.648 0.227 12.864 ;
     RECT  0.084 12.864 0.227 12.888 ;
     RECT  0.06 12.888 0.227 13.152 ;
     RECT  0.084 13.152 0.227 13.176 ;
     RECT  0.06 13.176 0.227 13.392 ;
     RECT  0.084 13.392 0.227 13.416 ;
     RECT  0.06 13.416 0.227 13.632 ;
     RECT  0.084 13.632 0.227 13.656 ;
     RECT  0.06 13.656 0.227 13.92 ;
     RECT  0.084 13.92 0.227 13.944 ;
     RECT  0.06 13.944 0.227 14.16 ;
     RECT  0.084 14.16 0.227 14.184 ;
     RECT  0.06 14.184 0.227 14.4 ;
     RECT  0.084 14.4 0.227 14.424 ;
     RECT  0.06 14.424 0.227 14.688 ;
     RECT  0.084 14.688 0.227 14.712 ;
     RECT  0.06 14.712 0.227 14.928 ;
     RECT  0.084 14.928 0.227 14.952 ;
     RECT  0.06 14.952 0.227 15.168 ;
     RECT  0.084 15.168 0.227 15.192 ;
     RECT  0.06 15.192 0.227 15.456 ;
     RECT  0.084 15.456 0.227 15.48 ;
     RECT  0.06 15.48 0.227 15.696 ;
     RECT  0.084 15.696 0.227 15.72 ;
     RECT  0.06 15.72 0.227 15.936 ;
     RECT  0.084 15.936 0.227 15.96 ;
     RECT  0.06 15.96 0.227 16.224 ;
     RECT  0.084 16.224 0.227 16.248 ;
     RECT  0.06 16.248 0.227 16.464 ;
     RECT  0.084 16.464 0.227 16.488 ;
     RECT  0.06 16.488 0.227 16.704 ;
     RECT  0.084 16.704 0.227 16.728 ;
     RECT  0.06 16.728 0.227 16.992 ;
     RECT  0.084 16.992 0.227 17.016 ;
     RECT  0.06 17.016 0.227 17.232 ;
     RECT  0.084 17.232 0.227 17.256 ;
     RECT  0.06 17.256 0.227 17.472 ;
     RECT  0.084 17.472 0.227 17.496 ;
     RECT  0.06 17.496 0.227 17.76 ;
     RECT  0.084 17.76 0.227 17.784 ;
     RECT  0.06 17.784 0.227 18 ;
     RECT  0.084 18 0.227 18.024 ;
     RECT  0.06 18.024 0.227 18.24 ;
     RECT  0.084 18.24 0.227 18.264 ;
     RECT  0.06 18.264 0.227 18.528 ;
     RECT  0.084 18.528 0.227 18.552 ;
     RECT  0.06 18.552 0.227 18.768 ;
     RECT  0.084 18.768 0.227 18.792 ;
     RECT  0.06 18.792 0.227 19.008 ;
     RECT  0.084 19.008 0.227 19.032 ;
     RECT  0.06 19.032 0.227 19.296 ;
     RECT  0.084 19.296 0.227 19.32 ;
     RECT  0.06 19.32 0.227 19.536 ;
     RECT  0.084 19.536 0.227 19.56 ;
     RECT  0.06 19.56 0.227 19.776 ;
     RECT  0.084 19.776 0.227 19.8 ;
     RECT  0.06 19.8 0.227 20.064 ;
     RECT  0.084 20.064 0.227 20.088 ;
     RECT  0.06 20.088 0.227 20.304 ;
     RECT  0.084 20.304 0.227 20.328 ;
     RECT  0.06 20.328 0.227 20.544 ;
     RECT  0.084 20.544 0.227 20.568 ;
     RECT  0.06 20.568 0.227 20.832 ;
     RECT  0.084 20.832 0.227 20.856 ;
     RECT  0.06 20.856 0.227 21.072 ;
     RECT  0.084 21.072 0.227 21.096 ;
     RECT  0.06 21.096 0.227 21.312 ;
     RECT  0.084 21.312 0.227 21.336 ;
     RECT  0.06 21.336 0.227 21.6 ;
     RECT  0.084 21.6 0.227 21.624 ;
     RECT  0.06 21.624 0.227 21.84 ;
     RECT  0.084 21.84 0.227 21.864 ;
     RECT  0.06 21.864 0.227 22.128 ;
     RECT  0.084 22.128 0.227 22.152 ;
     RECT  0.06 22.152 0.227 22.368 ;
     RECT  0.084 22.368 0.227 22.392 ;
     RECT  0.06 22.392 0.227 22.608 ;
     RECT  0.084 22.608 0.227 22.632 ;
     RECT  0.06 22.632 0.227 22.896 ;
     RECT  0.084 22.896 0.227 22.92 ;
     RECT  0.06 22.92 0.227 23.136 ;
     RECT  0.084 23.136 0.227 23.16 ;
     RECT  0.06 23.16 0.227 23.376 ;
     RECT  0.084 23.376 0.227 23.4 ;
     RECT  0.06 23.4 0.227 23.664 ;
     RECT  0.084 23.664 0.227 23.688 ;
     RECT  0.06 23.688 0.227 23.904 ;
     RECT  0.084 23.904 0.227 23.928 ;
     RECT  0.06 23.928 0.227 24.144 ;
     RECT  0.084 24.144 0.227 24.168 ;
     RECT  0.06 24.168 0.227 24.432 ;
     RECT  0.084 24.432 0.227 24.456 ;
     RECT  0.06 24.456 0.227 24.672 ;
     RECT  0.084 24.672 0.227 24.696 ;
     RECT  0.06 24.696 0.227 24.912 ;
     RECT  0.084 24.912 0.227 24.936 ;
     RECT  0.06 24.936 0.227 25.2 ;
     RECT  0.084 25.2 0.227 25.224 ;
     RECT  0.06 25.224 0.227 25.44 ;
     RECT  0.084 25.44 0.227 25.464 ;
     RECT  0.06 25.464 0.227 25.68 ;
     RECT  0.084 25.68 0.227 25.704 ;
     RECT  0.06 25.704 0.227 25.968 ;
     RECT  0.084 25.968 0.227 25.992 ;
     RECT  0.06 25.992 0.227 26.208 ;
     RECT  0.084 26.208 0.227 26.232 ;
     RECT  0.06 26.232 0.227 26.448 ;
     RECT  0.084 26.448 0.227 26.472 ;
     RECT  0.06 26.472 0.227 26.736 ;
     RECT  0.084 26.736 0.227 26.76 ;
     RECT  0.06 26.76 0.227 26.976 ;
     RECT  0.084 26.976 0.227 27 ;
     RECT  0.06 27 0.227 27.216 ;
     RECT  0.084 27.216 0.227 27.24 ;
     RECT  0.06 27.24 0.227 27.504 ;
     RECT  0.084 27.504 0.227 27.528 ;
     RECT  0.06 27.528 0.227 27.744 ;
     RECT  0.084 27.744 0.227 27.768 ;
     RECT  0.06 27.768 0.227 27.984 ;
     RECT  0.084 27.984 0.227 28.008 ;
     RECT  0.06 28.008 0.227 28.272 ;
     RECT  0.084 28.272 0.227 28.296 ;
     RECT  0.06 28.296 0.227 28.512 ;
     RECT  0.084 28.512 0.227 28.536 ;
     RECT  0.06 28.536 0.227 28.752 ;
     RECT  0.084 28.752 0.227 28.776 ;
     RECT  0.06 28.776 0.227 29.04 ;
     RECT  0.084 29.04 0.227 29.064 ;
     RECT  0.06 29.064 0.227 29.28 ;
     RECT  0.084 29.28 0.227 29.304 ;
     RECT  0.06 29.304 0.227 29.52 ;
     RECT  0.084 29.52 0.227 29.544 ;
     RECT  0.06 29.544 0.227 29.808 ;
     RECT  0.084 29.808 0.227 29.832 ;
     RECT  0.06 29.832 0.227 30.048 ;
     RECT  0.084 30.048 0.227 30.072 ;
     RECT  0.06 30.072 0.227 30.288 ;
     RECT  0.084 30.288 0.227 30.312 ;
     RECT  0.06 30.312 0.227 30.576 ;
     RECT  0.084 30.576 0.227 30.6 ;
     RECT  0.06 30.6 0.227 30.816 ;
     RECT  0.084 30.816 0.227 30.84 ;
     RECT  0.06 30.84 0.227 31.056 ;
     RECT  0.084 31.056 0.227 31.08 ;
     RECT  0.06 31.08 0.227 31.344 ;
     RECT  0.084 31.344 0.227 31.368 ;
     RECT  0.06 31.368 0.227 31.584 ;
     RECT  0.084 31.584 0.227 31.608 ;
     RECT  0.06 31.608 0.227 31.824 ;
     RECT  0.084 31.824 0.227 31.848 ;
     RECT  0.06 31.848 0.227 32.112 ;
     RECT  0.084 32.112 0.227 32.136 ;
     RECT  0.06 32.136 0.227 32.352 ;
     RECT  0.084 32.352 0.227 32.376 ;
     RECT  0.06 32.376 0.227 32.592 ;
     RECT  0.084 32.592 0.227 32.616 ;
     RECT  0.06 32.616 0.227 32.88 ;
     RECT  0.084 32.88 0.227 32.904 ;
     RECT  0.06 32.904 0.227 33.12 ;
     RECT  0.084 33.12 0.227 33.144 ;
     RECT  0.06 33.144 0.227 33.36 ;
     RECT  0.084 33.36 0.227 33.384 ;
     RECT  0.06 33.384 0.227 33.648 ;
     RECT  0.084 33.648 0.227 33.672 ;
     RECT  0.06 33.672 0.227 33.888 ;
     RECT  0.084 33.888 0.227 33.912 ;
     RECT  0.06 33.912 0.227 34.128 ;
     RECT  0.084 34.128 0.227 34.152 ;
     RECT  0.06 34.152 0.227 34.416 ;
     RECT  0.084 34.416 0.227 34.44 ;
     RECT  0.06 34.44 0.227 34.656 ;
     RECT  0.084 34.656 0.227 34.68 ;
     RECT  0.06 34.68 0.227 34.896 ;
     RECT  0.084 34.896 0.227 34.92 ;
     RECT  0.06 34.92 0.227 35.184 ;
     RECT  0.084 35.184 0.227 35.208 ;
     RECT  0.06 35.208 0.227 35.424 ;
     RECT  0.084 35.424 0.227 35.448 ;
     RECT  0.06 35.448 0.227 35.664 ;
     RECT  0.084 35.664 0.227 35.688 ;
     RECT  0.06 35.688 0.227 35.952 ;
     RECT  0.084 35.952 0.227 35.976 ;
     RECT  0.06 35.976 0.227 36.192 ;
     RECT  0.084 36.192 0.227 36.216 ;
     RECT  0.06 36.216 0.227 36.432 ;
     RECT  0.084 36.432 0.227 36.456 ;
     RECT  0.06 36.456 0.227 36.72 ;
     RECT  0.084 36.72 0.227 36.744 ;
     RECT  0.06 36.744 0.227 36.96 ;
     RECT  0.084 36.96 0.227 36.984 ;
     RECT  0.06 36.984 0.227 37.2 ;
     RECT  0.084 37.2 0.227 37.224 ;
     RECT  0.06 37.224 0.227 37.488 ;
     RECT  0.084 37.488 0.227 37.512 ;
     RECT  0.06 37.512 0.227 37.728 ;
     RECT  0.084 37.728 0.227 37.752 ;
     RECT  0.06 37.752 0.227 37.968 ;
     RECT  0.084 37.968 0.227 37.992 ;
     RECT  0.06 37.992 0.227 38.256 ;
     RECT  0.084 38.256 0.227 38.28 ;
     RECT  0.06 38.28 0.227 38.496 ;
     RECT  0.084 38.496 0.227 38.52 ;
     RECT  0.06 38.52 0.227 38.784 ;
     RECT  0.084 38.784 0.227 38.808 ;
     RECT  0.06 38.808 0.227 39.024 ;
     RECT  0.084 39.024 0.227 39.048 ;
     RECT  0.06 39.048 0.227 39.264 ;
     RECT  0.084 39.264 0.227 39.288 ;
     RECT  0.06 39.288 0.227 39.552 ;
     RECT  0.084 39.552 0.227 39.576 ;
     RECT  0.06 39.576 0.227 39.792 ;
     RECT  0.084 39.792 0.227 39.816 ;
     RECT  0.06 39.816 0.227 40.032 ;
     RECT  0.084 40.032 0.227 40.056 ;
     RECT  0.06 40.056 0.227 40.32 ;
     RECT  0.084 40.32 0.227 40.344 ;
     RECT  0.06 40.344 0.227 40.56 ;
     RECT  0.084 40.56 0.227 40.584 ;
     RECT  0.06 40.584 0.227 40.8 ;
     RECT  0.084 40.8 0.227 40.824 ;
     RECT  0.06 40.824 0.227 41.088 ;
     RECT  0.084 41.088 0.227 41.112 ;
     RECT  0.06 41.112 0.227 41.328 ;
     RECT  0.084 41.328 0.227 41.352 ;
     RECT  0.06 41.352 0.227 41.568 ;
     RECT  0.084 41.568 0.227 41.592 ;
     RECT  0.06 41.592 0.227 41.856 ;
     RECT  0.084 41.856 0.227 41.88 ;
     RECT  0.06 41.88 0.227 42.096 ;
     RECT  0.084 42.096 0.227 42.12 ;
     RECT  0.06 42.12 0.227 42.336 ;
     RECT  0.084 42.336 0.227 42.36 ;
     RECT  0.06 42.36 0.227 42.624 ;
     RECT  0.084 42.624 0.227 42.648 ;
     RECT  0.06 42.648 0.227 42.864 ;
     RECT  0.084 42.864 0.227 42.888 ;
     RECT  0.06 42.888 0.227 43.104 ;
     RECT  0.084 43.104 0.227 43.128 ;
     RECT  0.06 43.128 0.227 43.392 ;
     RECT  0.084 43.392 0.227 43.416 ;
     RECT  0.06 43.416 0.227 43.632 ;
     RECT  0.084 43.632 0.227 43.656 ;
     RECT  0.06 43.656 0.227 43.872 ;
     RECT  0.084 43.872 0.227 43.896 ;
     RECT  0.06 43.896 0.227 44.16 ;
     RECT  0.084 44.16 0.227 44.184 ;
     RECT  0.06 44.184 0.227 44.4 ;
     RECT  0.084 44.4 0.227 44.424 ;
     RECT  0.06 44.424 0.227 44.64 ;
     RECT  0.084 44.64 0.227 44.664 ;
     RECT  0.06 44.664 0.227 44.928 ;
     RECT  0.084 44.928 0.227 44.952 ;
     RECT  0.06 44.952 0.227 45.168 ;
     RECT  0.084 45.168 0.227 45.192 ;
     RECT  0.06 45.192 0.227 45.408 ;
     RECT  0.084 45.408 0.227 45.432 ;
     RECT  0.06 45.432 0.227 45.696 ;
     RECT  0.084 45.696 0.227 45.72 ;
     RECT  0.06 45.72 0.227 45.936 ;
     RECT  0.084 45.936 0.227 45.96 ;
     RECT  0.06 45.96 0.227 46.176 ;
     RECT  0.084 46.176 0.227 46.2 ;
     RECT  0.06 46.2 0.227 46.464 ;
     RECT  0.084 46.464 0.227 46.488 ;
     RECT  0.06 46.488 0.227 46.704 ;
     RECT  0.084 46.704 0.227 46.728 ;
     RECT  0.06 46.728 0.227 46.944 ;
     RECT  0.084 46.944 0.227 46.968 ;
     RECT  0.06 46.968 0.227 47.232 ;
     RECT  0.084 47.232 0.227 47.256 ;
     RECT  0.06 47.256 0.227 47.472 ;
     RECT  0.084 47.472 0.227 47.496 ;
     RECT  0.06 47.496 0.227 47.712 ;
     RECT  0.084 47.712 0.227 47.736 ;
     RECT  0.06 47.736 0.227 48 ;
     RECT  0.084 48 0.227 48.024 ;
     RECT  0.06 48.024 0.227 48.24 ;
     RECT  0.084 48.24 0.227 48.264 ;
     RECT  0.06 48.264 0.227 48.48 ;
     RECT  0.084 48.48 0.227 48.504 ;
     RECT  0.06 48.504 0.227 48.768 ;
     RECT  0.084 48.768 0.227 48.792 ;
     RECT  0.06 48.792 0.227 49.008 ;
     RECT  0.084 49.008 0.227 49.032 ;
     RECT  0.06 49.032 0.227 49.248 ;
     RECT  0.084 49.248 0.227 49.272 ;
     RECT  0.06 49.272 0.227 49.536 ;
     RECT  0.084 49.536 0.227 49.56 ;
     RECT  0.06 49.56 0.227 49.776 ;
     RECT  0.084 49.776 0.227 49.8 ;
     RECT  0.06 49.8 0.227 50.016 ;
     RECT  0.084 50.016 0.227 50.04 ;
     RECT  0.06 50.04 0.227 50.304 ;
     RECT  0.084 50.304 0.227 50.328 ;
     RECT  0.06 50.328 0.227 50.544 ;
     RECT  0.084 50.544 0.227 50.568 ;
     RECT  0.06 50.568 0.227 50.784 ;
     RECT  0.084 50.784 0.227 50.808 ;
     RECT  0.06 50.808 0.227 51.072 ;
     RECT  0.084 51.072 0.227 51.096 ;
     RECT  0.06 51.096 0.227 51.312 ;
     RECT  0.084 51.312 0.227 51.336 ;
     RECT  0.06 51.336 0.227 51.552 ;
     RECT  0.084 51.552 0.227 51.576 ;
     RECT  0.06 51.576 0.227 51.84 ;
     RECT  0.084 51.84 0.227 51.864 ;
     RECT  0.06 51.864 0.227 52.08 ;
     RECT  0.084 52.08 0.227 52.104 ;
     RECT  0.06 52.104 0.227 52.32 ;
     RECT  0.084 52.32 0.227 52.344 ;
     RECT  0.06 52.344 0.227 52.608 ;
     RECT  0.084 52.608 0.227 52.632 ;
     RECT  0.06 52.632 0.227 52.848 ;
     RECT  0.084 52.848 0.227 52.872 ;
     RECT  0.06 52.872 0.227 53.088 ;
     RECT  0.084 53.088 0.227 53.112 ;
     RECT  0.06 53.112 0.227 53.376 ;
     RECT  0.084 53.376 0.227 53.4 ;
     RECT  0.06 53.4 0.227 53.616 ;
     RECT  0.084 53.616 0.227 53.64 ;
     RECT  0.06 53.64 0.227 53.856 ;
     RECT  0.084 53.856 0.227 53.88 ;
     RECT  0.06 53.88 0.227 54.144 ;
     RECT  0.084 54.144 0.227 54.168 ;
     RECT  0.06 54.168 0.227 54.384 ;
     RECT  0.084 54.384 0.227 54.408 ;
     RECT  0.06 54.408 0.227 54.624 ;
     RECT  0.084 54.624 0.227 54.648 ;
     RECT  0.06 54.648 0.227 54.912 ;
     RECT  0.084 54.912 0.227 54.936 ;
     RECT  0.06 54.936 0.227 55.152 ;
     RECT  0.084 55.152 0.227 55.176 ;
     RECT  0.06 55.176 0.227 55.44 ;
     RECT  0.084 55.44 0.227 55.464 ;
     RECT  0.06 55.464 0.227 55.68 ;
     RECT  0.084 55.68 0.227 55.704 ;
     RECT  0.06 55.704 0.227 55.92 ;
     RECT  0.084 55.92 0.227 55.944 ;
     RECT  0.06 55.944 0.227 56.208 ;
     RECT  0.084 56.208 0.227 56.232 ;
     RECT  0.06 56.232 0.227 56.448 ;
     RECT  0.084 56.448 0.227 56.472 ;
     RECT  0.06 56.472 0.227 56.688 ;
     RECT  0.084 56.688 0.227 56.712 ;
     RECT  0.06 56.712 0.227 56.976 ;
     RECT  0.084 56.976 0.227 57 ;
     RECT  0.06 57 0.227 57.216 ;
     RECT  0.084 57.216 0.227 57.24 ;
     RECT  0.06 57.24 0.227 57.456 ;
     RECT  0.084 57.456 0.227 57.48 ;
     RECT  0.06 57.48 0.227 57.744 ;
     RECT  0.084 57.744 0.227 57.768 ;
     RECT  0.06 57.768 0.227 57.984 ;
     RECT  0.084 57.984 0.227 58.008 ;
     RECT  0.06 58.008 0.227 58.224 ;
     RECT  0.084 58.224 0.227 58.248 ;
     RECT  0.06 58.248 0.227 58.512 ;
     RECT  0.084 58.512 0.227 58.536 ;
     RECT  0.06 58.536 0.227 58.752 ;
     RECT  0.084 58.752 0.227 58.776 ;
     RECT  0.06 58.776 0.227 58.992 ;
     RECT  0.084 58.992 0.227 59.016 ;
     RECT  0.06 59.016 0.227 59.28 ;
     RECT  0.084 59.28 0.227 59.304 ;
     RECT  0.06 59.304 0.227 59.52 ;
     RECT  0.084 59.52 0.227 59.544 ;
     RECT  0.06 59.544 0.227 59.76 ;
     RECT  0.084 59.76 0.227 59.784 ;
     RECT  0.06 59.784 0.227 60.048 ;
     RECT  0.084 60.048 0.227 60.072 ;
     RECT  0.06 60.072 0.227 60.288 ;
     RECT  0.084 60.288 0.227 60.312 ;
     RECT  0.06 60.312 0.227 60.528 ;
     RECT  0.084 60.528 0.227 60.552 ;
     RECT  0.06 60.552 0.227 60.816 ;
     RECT  0.084 60.816 0.227 60.84 ;
     RECT  0.06 60.84 0.227 61.056 ;
     RECT  0.084 61.056 0.227 61.08 ;
     RECT  0.06 61.08 0.227 61.296 ;
     RECT  0.084 61.296 0.227 61.32 ;
     RECT  0.06 61.32 0.227 61.584 ;
     RECT  0.084 61.584 0.227 61.608 ;
     RECT  0.06 61.608 0.227 61.824 ;
     RECT  0.084 61.824 0.227 61.848 ;
     RECT  0.06 61.848 0.227 62.064 ;
     RECT  0.084 62.064 0.227 62.088 ;
     RECT  0.06 62.088 0.227 62.352 ;
     RECT  0.084 62.352 0.227 62.376 ;
     RECT  0.06 62.376 0.227 62.592 ;
     RECT  0.084 62.592 0.227 62.616 ;
     RECT  0.06 62.616 0.227 62.832 ;
     RECT  0.084 62.832 0.227 62.856 ;
     RECT  0.06 62.856 0.227 63.12 ;
     RECT  0.084 63.12 0.227 63.144 ;
     RECT  0.06 63.144 0.227 63.36 ;
     RECT  0.084 63.36 0.227 63.384 ;
     RECT  0.06 63.384 0.227 63.6 ;
     RECT  0.084 63.6 0.227 63.624 ;
     RECT  0.06 63.624 0.227 63.888 ;
     RECT  0.084 63.888 0.227 63.912 ;
     RECT  0.06 63.912 0.227 64.128 ;
     RECT  0.084 64.128 0.227 64.152 ;
     RECT  0.06 64.152 0.227 64.368 ;
     RECT  0.084 64.368 0.227 64.392 ;
     RECT  0.06 64.392 0.227 64.656 ;
     RECT  0.084 64.656 0.227 64.68 ;
     RECT  0.06 64.68 0.227 64.896 ;
     RECT  0.084 64.896 0.227 64.92 ;
     RECT  0.06 64.92 0.227 65.136 ;
     RECT  0.084 65.136 0.227 65.16 ;
     RECT  0.06 65.16 0.227 65.424 ;
     RECT  0.084 65.424 0.227 65.448 ;
     RECT  0.06 65.448 0.227 65.664 ;
     RECT  0.084 65.664 0.227 65.688 ;
     RECT  0.06 65.688 0.227 65.904 ;
     RECT  0.084 65.904 0.227 65.928 ;
     RECT  0.06 65.928 0.227 66.192 ;
     RECT  0.084 66.192 0.227 66.216 ;
     RECT  0.06 66.216 0.227 66.432 ;
     RECT  0.084 66.432 0.227 66.456 ;
     RECT  0.06 66.456 0.227 66.672 ;
     RECT  0.084 66.672 0.227 66.696 ;
     RECT  0.06 66.696 0.227 66.96 ;
     RECT  0.084 66.96 0.227 66.984 ;
     RECT  0.06 66.984 0.227 67.2 ;
     RECT  0.084 67.2 0.227 67.224 ;
     RECT  0.06 67.224 0.227 67.44 ;
     RECT  0.084 67.44 0.227 67.464 ;
     RECT  0.06 67.464 0.227 68.352 ;
     RECT  0.084 68.352 0.227 68.376 ;
     RECT  0.06 68.376 0.227 69.216 ;
     RECT  0.084 69.216 0.227 69.24 ;
     RECT  0.06 69.24 0.227 69.504 ;
     RECT  0.084 69.504 0.227 69.528 ;
     RECT  0.06 69.528 0.227 69.792 ;
     RECT  0.084 69.792 0.227 69.816 ;
     RECT  0.06 69.816 0.227 70.08 ;
     RECT  0.084 70.08 0.227 70.104 ;
     RECT  0.06 70.104 0.227 70.368 ;
     RECT  0.084 70.368 0.227 70.392 ;
     RECT  0.06 70.392 0.227 70.656 ;
     RECT  0.084 70.656 0.227 70.68 ;
     RECT  0.06 70.68 0.227 70.896 ;
     RECT  0.084 70.896 0.227 70.92 ;
     RECT  0.06 70.92 0.227 71.184 ;
     RECT  0.084 71.184 0.227 71.208 ;
     RECT  0.06 71.208 0.227 71.472 ;
     RECT  0.084 71.472 0.227 71.496 ;
     RECT  0.06 71.496 0.227 71.76 ;
     RECT  0.084 71.76 0.227 71.784 ;
     RECT  0.06 71.784 0.227 72.048 ;
     RECT  0.084 72.048 0.227 72.072 ;
     RECT  0.06 72.072 0.227 72.336 ;
     RECT  0.084 72.336 0.227 72.36 ;
     RECT  0.06 72.36 0.227 72.624 ;
     RECT  0.084 72.624 0.227 72.648 ;
     RECT  0.06 72.648 0.227 72.864 ;
     RECT  0.084 72.864 0.227 72.888 ;
     RECT  0.06 72.888 0.227 73.152 ;
     RECT  0.084 73.152 0.227 73.176 ;
     RECT  0.06 73.176 0.227 73.44 ;
     RECT  0.084 73.44 0.227 73.464 ;
     RECT  0.06 73.464 0.227 74.016 ;
     RECT  0.084 74.016 0.227 74.04 ;
     RECT  0.06 74.04 0.227 74.256 ;
     RECT  0.084 74.256 0.227 74.28 ;
     RECT  0.06 74.28 0.227 74.544 ;
     RECT  0.084 74.544 0.227 74.568 ;
     RECT  0.06 74.568 0.227 74.784 ;
     RECT  0.084 74.784 0.227 74.808 ;
     RECT  0.06 74.808 0.227 75.024 ;
     RECT  0.084 75.024 0.227 75.048 ;
     RECT  0.06 75.048 0.227 75.312 ;
     RECT  0.084 75.312 0.227 75.336 ;
     RECT  0.06 75.336 0.227 75.552 ;
     RECT  0.084 75.552 0.227 75.576 ;
     RECT  0.06 75.576 0.227 76.416 ;
     RECT  0.084 76.416 0.227 76.44 ;
     RECT  0.227 2.112 2.333 67.464 ;
     RECT  2.333 2.148 2.408 67.464 ;
     RECT  0.227 69.216 2.408 76.44 ;
     RECT  0.173 77.616 2.408 78.84 ;
     RECT  0.173 80.16 2.408 83.976 ;
     RECT  2.408 2.148 2.512 84.252 ;
     RECT  2.512 2.352 2.704 83.982 ;
     RECT  2.704 2.352 2.765 2.904 ;
     RECT  2.704 9.024 2.765 10.344 ;
     RECT  2.704 27.984 2.765 30.6 ;
     RECT  2.704 33.648 2.765 35.784 ;
     RECT  2.704 38.256 2.765 40.056 ;
     RECT  2.704 64.368 2.765 65.448 ;
     RECT  2.765 27.984 2.801 28.296 ;
     RECT  2.765 29.52 2.801 30.6 ;
     RECT  2.765 34.128 2.801 35.784 ;
     RECT  2.765 38.256 2.801 38.376 ;
     RECT  2.704 69.216 2.801 70.104 ;
     RECT  2.765 9.024 2.837 10.104 ;
     RECT  2.704 13.632 2.837 15.864 ;
     RECT  2.704 20.064 2.837 20.856 ;
     RECT  2.765 39.792 2.837 40.056 ;
     RECT  2.704 41.424 2.837 51.864 ;
     RECT  2.704 53.088 2.837 55.176 ;
     RECT  2.704 57.984 2.837 63.384 ;
     RECT  2.837 14.688 2.873 15.864 ;
     RECT  2.837 41.424 2.873 44.664 ;
     RECT  2.837 59.28 2.873 63.384 ;
     RECT  2.704 74.832 2.873 75.72 ;
     RECT  2.704 82.128 2.873 82.152 ;
     RECT  2.704 23.904 2.981 23.928 ;
     RECT  2.873 59.28 2.981 61.416 ;
     RECT  2.801 29.52 3.089 29.544 ;
     RECT  2.837 54.144 3.089 55.176 ;
     RECT  2.704 11.952 3.125 11.976 ;
     RECT  2.704 24.912 3.125 25.464 ;
     RECT  2.704 71.184 3.197 73.512 ;
     RECT  2.837 45.936 3.305 48.024 ;
     RECT  2.873 41.424 3.341 43.608 ;
     RECT  3.305 47.712 3.377 48.024 ;
     RECT  2.837 13.632 3.413 13.656 ;
     RECT  2.801 69.984 3.413 70.104 ;
     RECT  2.704 79.2 3.877 79.224 ;
     RECT  3.877 79.2 3.973 79.512 ;
     RECT  2.873 62.736 3.985 63.384 ;
     RECT  2.765 64.368 3.985 64.392 ;
     RECT  2.704 31.632 4.021 32.184 ;
     RECT  2.765 2.64 4.025 2.904 ;
     RECT  2.801 30.576 4.025 30.6 ;
     RECT  2.801 34.656 4.025 35.784 ;
     RECT  2.704 36.768 4.025 36.792 ;
     RECT  3.305 45.936 4.025 46.68 ;
     RECT  2.837 49.008 4.025 50.04 ;
     RECT  2.837 51.072 4.025 51.864 ;
     RECT  3.089 54.144 4.025 54.168 ;
     RECT  2.981 60.288 4.025 61.416 ;
     RECT  4.025 2.64 4.061 2.664 ;
     RECT  3.089 55.152 4.061 55.176 ;
     RECT  2.837 57.984 4.061 58.248 ;
     RECT  3.973 78.576 4.061 79.512 ;
     RECT  2.704 56.208 4.093 56.232 ;
     RECT  3.341 42.72 4.097 43.608 ;
     RECT  2.837 9.024 4.169 9.048 ;
     RECT  2.873 44.64 4.169 44.664 ;
     RECT  3.377 48 4.169 48.024 ;
     RECT  2.981 59.28 4.169 59.304 ;
     RECT  4.152 10.752 4.172 10.776 ;
     RECT  3.697 12 4.172 12.024 ;
     RECT  2.873 74.832 4.201 74.856 ;
     RECT  4.021 31.632 4.205 33.096 ;
     RECT  2.765 65.424 4.205 65.448 ;
     RECT  3.197 72.144 4.237 73.512 ;
     RECT  4.172 10.752 4.241 12.024 ;
     RECT  4.241 10.752 4.259 11.64 ;
     RECT  2.873 15.168 4.277 15.192 ;
     RECT  4.025 35.328 4.296 35.784 ;
     RECT  2.837 20.304 4.309 20.856 ;
     RECT  2.837 39.792 4.309 39.816 ;
     RECT  4.025 49.056 4.309 50.04 ;
     RECT  4.093 56.208 4.309 56.424 ;
     RECT  2.704 3.888 4.316 4.968 ;
     RECT  3.125 25.44 4.345 25.464 ;
     RECT  4.237 71.808 4.385 73.512 ;
     RECT  4.316 3.696 4.403 4.968 ;
     RECT  4.316 34.32 4.403 34.344 ;
     RECT  4.296 35.328 4.403 36.216 ;
     RECT  3.413 69.984 4.412 70.008 ;
     RECT  4.385 71.808 4.412 71.832 ;
     RECT  4.309 49.056 4.421 50.184 ;
     RECT  2.837 53.088 4.493 53.112 ;
     RECT  3.985 62.736 4.493 64.392 ;
     RECT  4.412 69.984 4.493 71.832 ;
     RECT  2.801 38.352 4.497 38.376 ;
     RECT  4.493 70.272 4.499 71.832 ;
     RECT  4.025 46.656 4.501 46.68 ;
     RECT  4.453 13.104 4.525 13.128 ;
     RECT  4.345 25.056 4.525 25.464 ;
     RECT  4.309 39.792 4.549 39.912 ;
     RECT  4.201 74.64 4.549 74.856 ;
     RECT  4.403 4.512 4.561 4.968 ;
     RECT  4.309 28.272 4.561 28.296 ;
     RECT  4.403 35.856 4.565 36.216 ;
     RECT  4.501 21.888 4.588 21.912 ;
     RECT  4.497 38.16 4.595 38.376 ;
     RECT  4.561 4.512 4.601 5.208 ;
     RECT  4.097 43.296 4.601 43.608 ;
     RECT  4.501 46.656 4.601 46.776 ;
     RECT  4.421 49.056 4.601 49.08 ;
     RECT  4.025 60.432 4.601 60.456 ;
     RECT  4.595 38.16 4.669 38.184 ;
     RECT  2.704 18.768 4.709 18.792 ;
     RECT  4.309 19.92 4.709 20.856 ;
     RECT  4.525 25.056 4.709 25.704 ;
     RECT  4.421 50.16 4.709 50.184 ;
     RECT  4.549 74.64 4.709 75.816 ;
     RECT  4.493 62.736 4.745 62.76 ;
     RECT  3.697 41.376 4.789 41.4 ;
     RECT  4.789 41.376 4.835 41.64 ;
     RECT  4.835 41.616 4.876 41.64 ;
     RECT  4.525 13.104 4.925 13.704 ;
     RECT  4.499 71.808 5.033 71.832 ;
     RECT  4.709 74.832 5.033 75.816 ;
     RECT  4.205 32.16 5.069 33.096 ;
     RECT  4.309 55.872 5.141 56.424 ;
     RECT  2.704 6.96 5.177 6.984 ;
     RECT  5.141 55.92 5.177 56.424 ;
     RECT  4.493 64.32 5.245 64.392 ;
     RECT  4.669 37.632 5.249 38.184 ;
     RECT  5.033 74.832 5.249 74.856 ;
     RECT  5.245 64.32 5.285 65.016 ;
     RECT  2.704 17.088 5.317 17.112 ;
     RECT  4.601 5.088 5.357 5.208 ;
     RECT  3.769 67.248 5.365 67.272 ;
     RECT  4.061 78.576 5.365 78.6 ;
     RECT  5.357 5.088 5.401 5.112 ;
     RECT  4.385 72.864 5.411 73.512 ;
     RECT  4.565 35.856 5.423 35.88 ;
     RECT  5.317 9.696 5.461 9.72 ;
     RECT  4.259 10.752 5.461 10.776 ;
     RECT  5.069 32.16 5.461 32.808 ;
     RECT  5.461 9.696 5.507 10.776 ;
     RECT  5.461 31.296 5.569 32.808 ;
     RECT  5.507 10.128 5.609 10.776 ;
     RECT  4.561 27.312 5.609 28.296 ;
     RECT  4.549 39.456 5.633 39.912 ;
     RECT  5.285 64.992 5.641 65.016 ;
     RECT  5.365 66.288 5.641 67.272 ;
     RECT  5.569 31.2 5.653 32.808 ;
     RECT  5.423 35.568 5.653 35.88 ;
     RECT  4.709 20.784 5.673 20.856 ;
     RECT  5.609 27.312 5.681 27.336 ;
     RECT  5.633 39.456 5.681 40.488 ;
     RECT  5.653 35.568 5.699 36.648 ;
     RECT  5.461 50.4 5.699 50.424 ;
     RECT  5.327 60.528 5.699 61.032 ;
     RECT  5.681 39.888 5.717 40.488 ;
     RECT  5.177 55.92 5.74 56.136 ;
     RECT  4.561 57.696 5.749 57.72 ;
     RECT  4.741 58.704 5.749 58.728 ;
     RECT  5.497 19.344 5.753 19.368 ;
     RECT  5.699 35.712 5.785 36.648 ;
     RECT  5.249 38.16 5.789 38.184 ;
     RECT  5.717 39.888 5.789 39.912 ;
     RECT  4.025 51.84 5.789 51.864 ;
     RECT  5.749 57.696 5.789 58.728 ;
     RECT  5.789 58.128 5.821 58.728 ;
     RECT  5.699 60.528 5.821 60.552 ;
     RECT  5.317 16.128 5.825 17.112 ;
     RECT  4.709 25.104 5.825 25.464 ;
     RECT  5.641 64.992 5.825 67.272 ;
     RECT  5.365 78.096 5.825 78.6 ;
     RECT  5.825 78.576 5.861 78.6 ;
     RECT  4.925 13.344 5.948 13.368 ;
     RECT  4.885 54.048 5.965 54.072 ;
     RECT  5.825 17.088 6.005 17.112 ;
     RECT  5.948 13.344 6.035 14.088 ;
     RECT  5.609 10.128 6.041 10.296 ;
     RECT  5.825 65.424 6.041 66.504 ;
     RECT  5.137 29.664 6.109 29.688 ;
     RECT  5.653 30.96 6.113 32.808 ;
     RECT  6.109 29.616 6.145 29.688 ;
     RECT  6.113 30.96 6.145 31.224 ;
     RECT  6.145 29.616 6.149 31.224 ;
     RECT  6.041 65.424 6.185 65.448 ;
     RECT  4.741 18.144 6.221 18.168 ;
     RECT  5.411 73.488 6.227 73.512 ;
     RECT  5.965 54.048 6.229 54.168 ;
     RECT  6.181 74.688 6.265 74.712 ;
     RECT  5.821 58.128 6.275 60.552 ;
     RECT  6.229 53.52 6.293 54.168 ;
     RECT  6.217 40.992 6.325 41.016 ;
     RECT  6.041 10.272 6.365 10.296 ;
     RECT  4.453 23.328 6.365 23.352 ;
     RECT  5.425 46.128 6.433 46.152 ;
     RECT  6.433 45.6 6.473 46.152 ;
     RECT  5.965 48.48 6.653 48.504 ;
     RECT  6.62 27.84 6.685 27.864 ;
     RECT  6.149 29.616 6.685 30.6 ;
     RECT  6.685 27.84 6.707 30.6 ;
     RECT  5.605 4.896 6.829 4.92 ;
     RECT  6.275 58.128 6.86 58.152 ;
     RECT  4.601 43.296 6.937 43.32 ;
     RECT  6.325 40.992 7.007 41.928 ;
     RECT  6.793 23.28 7.045 23.304 ;
     RECT  7.004 39.12 7.045 39.144 ;
     RECT  7.109 18.768 7.117 18.792 ;
     RECT  5.673 20.832 7.117 20.856 ;
     RECT  7.1 49.44 7.141 49.464 ;
     RECT  5.749 50.688 7.141 50.712 ;
     RECT  6.937 43.296 7.381 44.232 ;
     RECT  6.473 45.6 7.381 45.624 ;
     RECT  7.141 49.44 7.505 50.712 ;
     RECT  6.829 4.896 7.808 5.016 ;
     RECT  6.829 7.92 7.808 7.944 ;
     RECT  6.853 8.976 7.808 9 ;
     RECT  6.613 11.136 7.808 11.16 ;
     RECT  6.035 13.344 7.808 13.368 ;
     RECT  7.669 17.616 7.808 17.64 ;
     RECT  7.117 18.768 7.808 19.416 ;
     RECT  7.117 20.832 7.808 21.144 ;
     RECT  7.045 22.464 7.808 23.304 ;
     RECT  5.825 25.152 7.808 25.176 ;
     RECT  6.469 26.496 7.808 26.52 ;
     RECT  6.707 28.704 7.808 30.6 ;
     RECT  6.113 32.784 7.808 32.808 ;
     RECT  6.613 34.176 7.808 34.2 ;
     RECT  5.785 35.712 7.808 36.792 ;
     RECT  7.045 39.024 7.808 39.144 ;
     RECT  7.007 40.416 7.808 41.928 ;
     RECT  7.381 43.296 7.808 45.624 ;
     RECT  5.965 47.328 7.808 47.352 ;
     RECT  7.141 48.432 7.808 48.456 ;
     RECT  7.505 49.44 7.808 51.336 ;
     RECT  6.293 53.52 7.808 53.544 ;
     RECT  5.74 55.92 7.808 55.992 ;
     RECT  6.86 57.456 7.808 58.152 ;
     RECT  6.275 59.184 7.808 59.208 ;
     RECT  6.275 60.528 7.808 60.552 ;
     RECT  6.041 66.48 7.808 66.504 ;
     RECT  4.499 70.272 7.808 70.296 ;
     RECT  6.109 78.624 7.808 78.648 ;
     RECT  7.808 2.148 7.912 84.252 ;
     RECT  7.912 2.418 8.104 83.982 ;
     RECT  8.104 8.976 8.165 9 ;
     RECT  8.104 21.12 8.165 21.144 ;
     RECT  8.104 22.464 8.165 22.488 ;
     RECT  8.104 29.04 8.165 29.064 ;
     RECT  8.104 32.784 8.165 32.808 ;
     RECT  8.104 34.176 8.165 34.2 ;
     RECT  8.104 53.52 8.165 53.544 ;
     RECT  8.104 70.272 8.165 70.296 ;
     RECT  8.104 3.408 8.243 3.432 ;
     RECT  8.104 4.896 8.243 4.92 ;
     RECT  8.104 66.48 8.243 66.504 ;
     RECT  8.104 67.824 8.243 67.848 ;
     RECT  8.104 17.616 8.273 17.64 ;
     RECT  8.104 30.576 8.273 30.6 ;
     RECT  8.104 6.288 8.381 6.312 ;
     RECT  8.104 64.56 8.381 65.496 ;
     RECT  8.104 13.344 8.387 13.368 ;
     RECT  8.381 64.56 8.387 64.584 ;
     RECT  8.104 63.216 8.389 63.24 ;
     RECT  8.104 14.352 8.428 14.376 ;
     RECT  8.104 36.528 13.208 36.552 ;
     RECT  8.104 43.296 13.208 43.32 ;
     RECT  8.104 55.968 13.208 55.992 ;
     RECT  8.104 78.624 13.208 78.648 ;
     RECT  13.208 2.148 13.312 84.252 ;
     RECT  13.312 2.418 13.504 83.982 ;
     RECT  13.504 78.624 14.465 78.648 ;
     RECT  13.504 36.528 18.608 36.552 ;
     RECT  13.504 43.296 18.608 43.32 ;
     RECT  13.504 55.968 18.608 55.992 ;
     RECT  18.608 2.148 18.712 84.252 ;
     RECT  18.712 2.418 18.904 83.982 ;
     RECT  18.904 36.528 24.008 36.552 ;
     RECT  18.904 43.296 24.008 43.32 ;
     RECT  18.904 55.968 24.008 55.992 ;
     RECT  24.008 2.148 24.112 84.252 ;
     RECT  24.112 2.418 24.304 83.982 ;
     RECT  24.304 36.528 29.408 36.552 ;
     RECT  24.304 43.296 29.408 43.32 ;
     RECT  24.304 55.968 29.408 55.992 ;
     RECT  29.408 2.148 29.512 84.252 ;
     RECT  29.512 2.418 29.704 83.982 ;
     RECT  29.704 36.528 31.129 36.552 ;
     RECT  31.129 36.528 31.457 37.032 ;
     RECT  29.704 43.296 32.533 43.32 ;
     RECT  32.533 50.736 32.617 50.76 ;
     RECT  32.533 43.2 32.725 43.32 ;
     RECT  31.457 37.008 32.771 37.032 ;
     RECT  29.704 55.968 33.685 55.992 ;
     RECT  33.685 55.968 33.731 56.424 ;
     RECT  33.649 51.264 33.733 51.288 ;
     RECT  32.725 43.056 34.808 43.32 ;
     RECT  33.731 56.4 34.808 56.424 ;
     RECT  33.877 81.888 34.808 81.912 ;
     RECT  34.808 2.148 34.912 84.252 ;
     RECT  34.912 2.418 35.104 83.982 ;
     RECT  35.104 43.152 38.833 43.32 ;
     RECT  38.833 43.056 40.208 43.32 ;
     RECT  35.104 81.888 40.208 81.912 ;
     RECT  40.208 2.148 40.312 84.252 ;
     RECT  40.312 2.418 40.504 83.982 ;
     RECT  43.009 27.984 43.153 28.008 ;
     RECT  43.153 27.456 43.225 28.008 ;
     RECT  42.685 60.096 43.225 60.12 ;
     RECT  42.865 17.712 43.261 17.736 ;
     RECT  43.153 18.96 43.261 18.984 ;
     RECT  42.973 22.512 43.261 22.536 ;
     RECT  42.937 26.304 43.261 26.328 ;
     RECT  43.225 27.456 43.261 28.44 ;
     RECT  43.225 59.808 43.261 60.12 ;
     RECT  43.081 8.544 43.297 8.568 ;
     RECT  42.793 64.944 43.405 64.968 ;
     RECT  43.369 78.624 43.441 78.648 ;
     RECT  40.504 43.056 43.477 43.32 ;
     RECT  42.829 30.672 43.513 30.696 ;
     RECT  43.513 74.352 43.549 74.376 ;
     RECT  43.405 64.368 43.585 64.968 ;
     RECT  43.297 54.096 43.621 54.12 ;
     RECT  43.621 24.672 43.693 24.696 ;
     RECT  43.261 26.304 43.693 28.44 ;
     RECT  43.621 37.968 43.693 37.992 ;
     RECT  43.621 38.976 43.693 39 ;
     RECT  43.369 46.272 43.693 46.296 ;
     RECT  43.261 59.52 43.693 60.12 ;
     RECT  43.369 62.976 43.693 63 ;
     RECT  43.693 37.44 43.729 37.992 ;
     RECT  43.693 38.976 43.729 39.288 ;
     RECT  43.225 41.424 43.729 41.448 ;
     RECT  43.729 41.232 43.765 41.448 ;
     RECT  43.477 42.768 43.765 43.32 ;
     RECT  43.693 58.944 43.765 60.12 ;
     RECT  43.693 62.016 43.765 63 ;
     RECT  43.585 64.368 43.765 65.256 ;
     RECT  43.657 72.96 43.765 72.984 ;
     RECT  43.225 49.248 43.801 49.272 ;
     RECT  43.585 50.4 43.801 50.424 ;
     RECT  43.369 69.792 43.801 69.816 ;
     RECT  43.693 24.672 43.837 28.44 ;
     RECT  43.441 78.624 43.873 78.792 ;
     RECT  43.873 78.48 43.913 78.792 ;
     RECT  43.765 58.944 43.945 60.408 ;
     RECT  43.945 58.656 43.981 60.408 ;
     RECT  43.729 37.44 44.017 39.288 ;
     RECT  43.765 41.232 44.017 43.32 ;
     RECT  43.913 78.48 44.053 78.648 ;
     RECT  43.513 30.672 44.161 30.984 ;
     RECT  43.297 57.408 44.161 57.432 ;
     RECT  43.765 62.016 44.161 65.256 ;
     RECT  43.945 66.528 44.161 66.552 ;
     RECT  44.053 78.096 44.165 78.648 ;
     RECT  44.161 57.072 44.197 57.432 ;
     RECT  43.981 58.656 44.197 60.696 ;
     RECT  43.801 49.248 44.233 50.424 ;
     RECT  44.197 57.072 44.233 60.696 ;
     RECT  43.189 47.712 44.341 47.736 ;
     RECT  44.233 52.56 44.341 52.584 ;
     RECT  43.621 54.096 44.341 54.696 ;
     RECT  43.801 69.792 44.341 70.104 ;
     RECT  44.017 77.04 44.341 77.064 ;
     RECT  44.165 78.096 44.341 78.504 ;
     RECT  44.341 52.56 44.377 53.112 ;
     RECT  44.377 51.744 44.413 53.112 ;
     RECT  44.341 54.096 44.413 55.272 ;
     RECT  44.341 69.792 44.413 70.872 ;
     RECT  43.765 72 44.449 72.984 ;
     RECT  44.233 57.072 44.521 60.888 ;
     RECT  43.081 36.096 44.557 36.12 ;
     RECT  44.233 48.96 44.557 50.424 ;
     RECT  43.549 67.824 44.665 67.848 ;
     RECT  44.413 69.504 44.665 70.872 ;
     RECT  44.521 56.88 44.701 60.888 ;
     RECT  44.161 62.016 44.701 66.552 ;
     RECT  44.017 37.44 44.773 40.152 ;
     RECT  44.017 41.232 44.773 44.136 ;
     RECT  44.449 72 44.809 73.272 ;
     RECT  43.549 74.352 44.809 74.952 ;
     RECT  44.341 47.712 44.917 47.976 ;
     RECT  44.557 48.96 44.917 50.616 ;
     RECT  44.917 47.712 44.989 50.616 ;
     RECT  44.413 51.744 44.989 55.272 ;
     RECT  44.809 72 45.061 74.952 ;
     RECT  44.989 47.424 45.133 55.752 ;
     RECT  44.701 56.88 45.133 66.552 ;
     RECT  45.133 47.424 45.457 66.552 ;
     RECT  44.665 67.824 45.457 70.872 ;
     RECT  43.297 7.632 45.608 8.568 ;
     RECT  43.189 12.336 45.608 12.36 ;
     RECT  43.261 17.184 45.608 18.984 ;
     RECT  44.017 20.688 45.608 20.712 ;
     RECT  43.261 22.512 45.608 23.304 ;
     RECT  43.837 24.672 45.608 28.728 ;
     RECT  44.161 30.384 45.608 30.984 ;
     RECT  42.721 32.976 45.608 33 ;
     RECT  44.557 35.52 45.608 36.12 ;
     RECT  44.773 37.44 45.608 44.136 ;
     RECT  43.693 45.552 45.608 46.296 ;
     RECT  45.457 47.424 45.608 70.872 ;
     RECT  45.061 71.952 45.608 74.952 ;
     RECT  44.341 77.04 45.608 78.504 ;
     RECT  40.504 81.888 45.608 81.912 ;
     RECT  45.608 2.148 45.712 84.252 ;
     RECT  45.712 2.418 45.904 83.982 ;
     RECT  45.904 7.488 46.757 7.656 ;
     RECT  46.757 7.488 51.008 7.512 ;
     RECT  45.904 8.688 51.008 8.712 ;
     RECT  45.904 12.336 51.008 12.36 ;
     RECT  45.904 17.184 51.008 18.984 ;
     RECT  45.904 20.688 51.008 20.712 ;
     RECT  45.904 22.608 51.008 23.304 ;
     RECT  45.904 24.672 51.008 28.728 ;
     RECT  45.904 30.384 51.008 30.984 ;
     RECT  45.904 32.976 51.008 33 ;
     RECT  45.904 35.52 51.008 36.12 ;
     RECT  45.904 37.44 51.008 44.136 ;
     RECT  45.904 45.552 51.008 46.392 ;
     RECT  45.904 47.424 51.008 74.952 ;
     RECT  45.904 77.04 51.008 78.504 ;
     RECT  45.904 81.888 51.008 81.912 ;
     RECT  51.008 2.148 51.112 84.252 ;
     RECT  51.112 2.418 51.304 83.982 ;
     RECT  51.304 7.488 56.408 7.512 ;
     RECT  51.304 8.688 56.408 8.712 ;
     RECT  51.304 12.336 56.408 12.36 ;
     RECT  51.304 17.184 56.408 18.984 ;
     RECT  51.304 20.688 56.408 20.712 ;
     RECT  51.304 22.608 56.408 23.304 ;
     RECT  51.304 24.672 56.408 28.728 ;
     RECT  51.304 30.384 56.408 30.984 ;
     RECT  51.304 32.976 56.408 33 ;
     RECT  51.304 35.52 56.408 36.12 ;
     RECT  51.304 37.44 56.408 44.136 ;
     RECT  51.304 45.552 56.408 46.392 ;
     RECT  51.304 47.424 56.408 74.952 ;
     RECT  51.304 77.04 56.408 78.504 ;
     RECT  51.304 81.888 56.408 81.912 ;
     RECT  56.408 2.148 56.512 84.252 ;
     RECT  56.512 2.418 56.704 83.982 ;
     RECT  56.704 7.488 61.808 7.512 ;
     RECT  56.704 8.688 61.808 8.712 ;
     RECT  56.704 12.336 61.808 12.36 ;
     RECT  56.704 17.184 61.808 18.984 ;
     RECT  56.704 20.688 61.808 20.712 ;
     RECT  56.704 22.608 61.808 23.304 ;
     RECT  56.704 24.672 61.808 28.728 ;
     RECT  56.704 30.384 61.808 30.984 ;
     RECT  56.704 32.976 61.808 33 ;
     RECT  56.704 35.52 61.808 36.12 ;
     RECT  56.704 37.44 61.808 44.136 ;
     RECT  56.704 45.552 61.808 46.392 ;
     RECT  56.704 47.424 61.808 74.952 ;
     RECT  56.704 77.04 61.808 78.504 ;
     RECT  56.704 81.888 61.808 81.912 ;
     RECT  61.808 2.148 61.912 84.252 ;
     RECT  61.912 2.418 62.104 83.982 ;
     RECT  62.104 7.488 67.208 7.512 ;
     RECT  62.104 8.688 67.208 8.712 ;
     RECT  62.104 12.336 67.208 12.36 ;
     RECT  62.104 17.184 67.208 18.984 ;
     RECT  62.104 20.688 67.208 20.712 ;
     RECT  62.104 22.608 67.208 23.304 ;
     RECT  62.104 24.672 67.208 28.728 ;
     RECT  62.104 30.384 67.208 30.984 ;
     RECT  62.104 32.976 67.208 33 ;
     RECT  62.104 35.52 67.208 36.12 ;
     RECT  62.104 37.44 67.208 44.136 ;
     RECT  62.104 45.552 67.208 46.392 ;
     RECT  62.104 47.424 67.208 74.952 ;
     RECT  62.104 77.04 67.208 78.504 ;
     RECT  62.104 81.888 67.208 81.912 ;
     RECT  67.208 2.148 67.312 84.252 ;
     RECT  67.312 2.418 67.504 83.982 ;
     RECT  67.504 7.488 72.608 7.512 ;
     RECT  67.504 8.688 72.608 8.712 ;
     RECT  67.504 12.336 72.608 12.36 ;
     RECT  67.504 17.184 72.608 18.984 ;
     RECT  67.504 20.688 72.608 20.712 ;
     RECT  67.504 22.608 72.608 23.304 ;
     RECT  67.504 24.672 72.608 28.728 ;
     RECT  67.504 30.384 72.608 30.984 ;
     RECT  67.504 32.976 72.608 33 ;
     RECT  67.504 35.52 72.608 36.12 ;
     RECT  67.504 37.44 72.608 44.136 ;
     RECT  67.504 45.552 72.608 46.392 ;
     RECT  67.504 47.424 72.608 74.952 ;
     RECT  67.504 77.04 72.608 78.504 ;
     RECT  67.504 81.888 72.608 81.912 ;
     RECT  72.608 2.148 72.712 84.252 ;
     RECT  72.712 2.418 72.904 83.982 ;
     RECT  72.904 7.488 78.008 7.512 ;
     RECT  72.904 8.688 78.008 8.712 ;
     RECT  72.904 12.336 78.008 12.36 ;
     RECT  72.904 17.184 78.008 18.984 ;
     RECT  72.904 20.688 78.008 20.712 ;
     RECT  72.904 22.608 78.008 23.304 ;
     RECT  72.904 24.672 78.008 28.728 ;
     RECT  72.904 30.384 78.008 30.984 ;
     RECT  72.904 32.976 78.008 33 ;
     RECT  72.904 35.52 78.008 36.12 ;
     RECT  72.904 37.44 78.008 44.136 ;
     RECT  72.904 45.552 78.008 46.392 ;
     RECT  72.904 47.424 78.008 74.952 ;
     RECT  72.904 77.04 78.008 78.504 ;
     RECT  72.904 81.888 78.008 81.912 ;
     RECT  78.008 2.148 78.112 84.252 ;
     RECT  78.112 2.418 78.304 83.982 ;
     RECT  78.304 8.688 79.801 8.712 ;
     RECT  78.304 12.336 79.801 12.36 ;
     RECT  78.304 17.184 79.801 18.984 ;
     RECT  78.304 20.688 79.801 20.712 ;
     RECT  79.801 8.688 80.377 9.288 ;
     RECT  79.801 12.048 80.377 13.176 ;
     RECT  78.304 22.608 80.377 23.304 ;
     RECT  78.304 24.672 80.377 28.728 ;
     RECT  78.304 30.384 80.377 30.984 ;
     RECT  78.304 77.04 80.377 78.504 ;
     RECT  80.377 12.048 80.413 14.712 ;
     RECT  79.801 16.032 80.413 16.056 ;
     RECT  79.801 17.184 80.953 21.192 ;
     RECT  80.377 22.608 80.953 28.728 ;
     RECT  80.377 30.096 80.953 30.984 ;
     RECT  78.304 32.976 80.953 33 ;
     RECT  78.304 35.52 80.953 36.12 ;
     RECT  80.377 8.688 81.493 9.864 ;
     RECT  80.953 17.184 81.493 30.984 ;
     RECT  80.377 76.272 82.021 78.504 ;
     RECT  78.304 81.888 82.021 81.96 ;
     RECT  80.989 83.232 82.067 83.256 ;
     RECT  81.493 6.048 82.069 6.072 ;
     RECT  78.304 7.488 82.069 7.512 ;
     RECT  81.493 8.688 82.069 11.016 ;
     RECT  82.021 81.552 82.108 81.96 ;
     RECT  78.304 47.424 82.645 74.952 ;
     RECT  82.021 76.272 82.645 79.224 ;
     RECT  82.108 81.936 82.645 81.96 ;
     RECT  81.493 17.184 83.221 31.176 ;
     RECT  80.953 32.304 83.221 33.864 ;
     RECT  78.304 37.44 83.221 44.136 ;
     RECT  78.304 45.552 83.221 46.392 ;
     RECT  81.493 2.784 83.408 2.808 ;
     RECT  82.069 4.992 83.408 6.072 ;
     RECT  82.069 7.488 83.408 11.016 ;
     RECT  80.413 12.048 83.408 16.056 ;
     RECT  83.221 17.184 83.408 33.864 ;
     RECT  80.953 35.232 83.408 36.12 ;
     RECT  83.221 37.44 83.408 46.392 ;
     RECT  82.645 47.424 83.408 79.224 ;
     RECT  82.645 81.936 83.408 82.776 ;
     RECT  83.408 2.148 83.512 84.252 ;
     RECT  83.512 2.418 83.704 83.982 ;
     RECT  83.704 2.784 84.913 2.808 ;
     RECT  83.704 4.992 84.913 6.456 ;
     RECT  83.704 7.536 84.913 78.504 ;
     RECT  83.704 81.408 84.913 82.776 ;
     RECT  84.913 2.784 85.453 78.504 ;
     RECT  84.913 81.12 85.453 82.776 ;
     RECT  85.453 2.784 85.489 79.464 ;
     RECT  85.453 81.12 85.489 83.64 ;
     RECT  85.489 2.784 86.281 83.64 ;
     RECT  86.281 2.112 86.316 2.136 ;
     RECT  86.281 2.136 86.364 2.4 ;
     RECT  86.281 2.4 86.316 2.424 ;
     RECT  86.281 2.424 86.364 2.688 ;
     RECT  86.281 2.688 86.316 2.712 ;
     RECT  86.281 2.712 86.364 2.976 ;
     RECT  86.281 2.976 86.316 3 ;
     RECT  86.281 3 86.364 3.264 ;
     RECT  86.281 3.264 86.316 3.288 ;
     RECT  86.281 3.288 86.364 3.552 ;
     RECT  86.281 3.552 86.316 3.576 ;
     RECT  86.281 3.576 86.364 3.84 ;
     RECT  86.281 3.84 86.316 3.864 ;
     RECT  86.281 3.864 86.364 4.128 ;
     RECT  86.281 4.128 86.316 4.152 ;
     RECT  86.281 4.152 86.364 4.416 ;
     RECT  86.281 4.416 86.316 4.44 ;
     RECT  86.281 4.44 86.364 4.704 ;
     RECT  86.281 4.704 86.316 4.728 ;
     RECT  86.281 4.728 86.364 4.992 ;
     RECT  86.281 4.992 86.316 5.016 ;
     RECT  86.281 5.016 86.364 5.28 ;
     RECT  86.281 5.28 86.316 5.304 ;
     RECT  86.281 5.304 86.364 5.568 ;
     RECT  86.281 5.568 86.316 5.592 ;
     RECT  86.281 5.592 86.364 5.856 ;
     RECT  86.281 5.856 86.316 5.88 ;
     RECT  86.281 5.88 86.364 6.144 ;
     RECT  86.281 6.144 86.316 6.168 ;
     RECT  86.281 6.168 86.364 6.432 ;
     RECT  86.281 6.432 86.316 6.456 ;
     RECT  86.281 6.456 86.364 6.72 ;
     RECT  86.281 6.72 86.316 6.744 ;
     RECT  86.281 6.744 86.364 7.008 ;
     RECT  86.281 7.008 86.316 7.032 ;
     RECT  86.281 7.032 86.364 7.248 ;
     RECT  86.281 7.248 86.316 7.272 ;
     RECT  86.281 7.272 86.364 7.536 ;
     RECT  86.281 7.536 86.316 7.56 ;
     RECT  86.281 7.56 86.364 7.824 ;
     RECT  86.281 7.824 86.316 7.848 ;
     RECT  86.281 7.848 86.364 8.112 ;
     RECT  86.281 8.112 86.316 8.136 ;
     RECT  86.281 8.136 86.364 8.4 ;
     RECT  86.281 8.4 86.316 8.424 ;
     RECT  86.281 8.424 86.364 8.688 ;
     RECT  86.281 8.688 86.316 8.712 ;
     RECT  86.281 8.712 86.364 8.976 ;
     RECT  86.281 8.976 86.316 9 ;
     RECT  86.281 9 86.364 9.264 ;
     RECT  86.281 9.264 86.316 9.288 ;
     RECT  86.281 9.288 86.364 9.552 ;
     RECT  86.281 9.552 86.316 9.576 ;
     RECT  86.281 9.576 86.364 9.84 ;
     RECT  86.281 9.84 86.316 9.864 ;
     RECT  86.281 9.864 86.364 10.128 ;
     RECT  86.281 10.128 86.316 10.152 ;
     RECT  86.281 10.152 86.364 10.416 ;
     RECT  86.281 10.416 86.316 10.44 ;
     RECT  86.281 10.44 86.364 10.704 ;
     RECT  86.281 10.704 86.316 10.728 ;
     RECT  86.281 10.728 86.364 10.992 ;
     RECT  86.281 10.992 86.316 11.016 ;
     RECT  86.281 11.016 86.364 11.28 ;
     RECT  86.281 11.28 86.316 11.304 ;
     RECT  86.281 11.304 86.364 11.568 ;
     RECT  86.281 11.568 86.316 11.592 ;
     RECT  86.281 11.592 86.364 11.856 ;
     RECT  86.281 11.856 86.316 11.88 ;
     RECT  86.281 11.88 86.364 12.144 ;
     RECT  86.281 12.144 86.316 12.168 ;
     RECT  86.281 12.168 86.364 12.432 ;
     RECT  86.281 12.432 86.316 12.456 ;
     RECT  86.281 12.456 86.364 12.72 ;
     RECT  86.281 12.72 86.316 12.744 ;
     RECT  86.281 12.744 86.364 12.96 ;
     RECT  86.281 12.96 86.316 12.984 ;
     RECT  86.281 12.984 86.364 13.248 ;
     RECT  86.281 13.248 86.316 13.272 ;
     RECT  86.281 13.272 86.364 13.536 ;
     RECT  86.281 13.536 86.316 13.56 ;
     RECT  86.281 13.56 86.364 13.824 ;
     RECT  86.281 13.824 86.316 13.848 ;
     RECT  86.281 13.848 86.364 14.112 ;
     RECT  86.281 14.112 86.316 14.136 ;
     RECT  86.281 14.136 86.364 14.4 ;
     RECT  86.281 14.4 86.316 14.424 ;
     RECT  86.281 14.424 86.364 14.688 ;
     RECT  86.281 14.688 86.316 14.712 ;
     RECT  86.281 14.712 86.364 14.976 ;
     RECT  86.281 14.976 86.316 15 ;
     RECT  86.281 15 86.364 15.264 ;
     RECT  86.281 15.264 86.316 15.288 ;
     RECT  86.281 15.288 86.364 15.552 ;
     RECT  86.281 15.552 86.316 15.576 ;
     RECT  86.281 15.576 86.364 15.84 ;
     RECT  86.281 15.84 86.316 15.864 ;
     RECT  86.281 15.864 86.364 16.128 ;
     RECT  86.281 16.128 86.316 16.152 ;
     RECT  86.281 16.152 86.364 16.416 ;
     RECT  86.281 16.416 86.316 16.44 ;
     RECT  86.281 16.44 86.364 16.704 ;
     RECT  86.281 16.704 86.316 16.728 ;
     RECT  86.281 16.728 86.364 16.992 ;
     RECT  86.281 16.992 86.316 17.016 ;
     RECT  86.281 17.016 86.364 17.28 ;
     RECT  86.281 17.28 86.316 17.304 ;
     RECT  86.281 17.304 86.364 17.568 ;
     RECT  86.281 17.568 86.316 17.592 ;
     RECT  86.281 17.592 86.364 17.856 ;
     RECT  86.281 17.856 86.316 17.88 ;
     RECT  86.281 17.88 86.364 18.144 ;
     RECT  86.281 18.144 86.316 18.168 ;
     RECT  86.281 18.168 86.364 18.384 ;
     RECT  86.281 18.384 86.316 18.408 ;
     RECT  86.281 18.408 86.364 18.672 ;
     RECT  86.281 18.672 86.316 18.696 ;
     RECT  86.281 18.696 86.364 18.96 ;
     RECT  86.281 18.96 86.316 18.984 ;
     RECT  86.281 18.984 86.364 19.248 ;
     RECT  86.281 19.248 86.316 19.272 ;
     RECT  86.281 19.272 86.364 19.536 ;
     RECT  86.281 19.536 86.316 19.56 ;
     RECT  86.281 19.56 86.364 19.824 ;
     RECT  86.281 19.824 86.316 19.848 ;
     RECT  86.281 19.848 86.364 20.112 ;
     RECT  86.281 20.112 86.316 20.136 ;
     RECT  86.281 20.136 86.364 20.4 ;
     RECT  86.281 20.4 86.316 20.424 ;
     RECT  86.281 20.424 86.364 20.688 ;
     RECT  86.281 20.688 86.316 20.712 ;
     RECT  86.281 20.712 86.364 20.976 ;
     RECT  86.281 20.976 86.316 21 ;
     RECT  86.281 21 86.364 21.264 ;
     RECT  86.281 21.264 86.316 21.288 ;
     RECT  86.281 21.288 86.364 21.552 ;
     RECT  86.281 21.552 86.316 21.576 ;
     RECT  86.281 21.576 86.364 21.84 ;
     RECT  86.281 21.84 86.316 21.864 ;
     RECT  86.281 21.864 86.364 22.128 ;
     RECT  86.281 22.128 86.316 22.152 ;
     RECT  86.281 22.152 86.364 22.416 ;
     RECT  86.281 22.416 86.316 22.44 ;
     RECT  86.281 22.44 86.364 22.704 ;
     RECT  86.281 22.704 86.316 22.728 ;
     RECT  86.281 22.728 86.364 22.992 ;
     RECT  86.281 22.992 86.316 23.016 ;
     RECT  86.281 23.016 86.364 23.28 ;
     RECT  86.281 23.28 86.316 23.304 ;
     RECT  86.281 23.304 86.364 23.568 ;
     RECT  86.281 23.568 86.316 23.592 ;
     RECT  86.281 23.592 86.364 23.856 ;
     RECT  86.281 23.856 86.316 23.88 ;
     RECT  86.281 23.88 86.364 24.096 ;
     RECT  86.281 24.096 86.316 24.12 ;
     RECT  86.281 24.12 86.364 24.384 ;
     RECT  86.281 24.384 86.316 24.408 ;
     RECT  86.281 24.408 86.364 24.672 ;
     RECT  86.281 24.672 86.316 24.696 ;
     RECT  86.281 24.696 86.364 24.96 ;
     RECT  86.281 24.96 86.316 24.984 ;
     RECT  86.281 24.984 86.364 25.248 ;
     RECT  86.281 25.248 86.316 25.272 ;
     RECT  86.281 25.272 86.364 25.536 ;
     RECT  86.281 25.536 86.316 25.56 ;
     RECT  86.281 25.56 86.364 25.824 ;
     RECT  86.281 25.824 86.316 25.848 ;
     RECT  86.281 25.848 86.364 26.112 ;
     RECT  86.281 26.112 86.316 26.136 ;
     RECT  86.281 26.136 86.364 26.4 ;
     RECT  86.281 26.4 86.316 26.424 ;
     RECT  86.281 26.424 86.364 26.688 ;
     RECT  86.281 26.688 86.316 26.712 ;
     RECT  86.281 26.712 86.364 26.976 ;
     RECT  86.281 26.976 86.316 27 ;
     RECT  86.281 27 86.364 27.264 ;
     RECT  86.281 27.264 86.316 27.288 ;
     RECT  86.281 27.288 86.364 27.552 ;
     RECT  86.281 27.552 86.316 27.576 ;
     RECT  86.281 27.576 86.364 27.84 ;
     RECT  86.281 27.84 86.316 27.864 ;
     RECT  86.281 27.864 86.364 28.128 ;
     RECT  86.281 28.128 86.316 28.152 ;
     RECT  86.281 28.152 86.364 28.416 ;
     RECT  86.281 28.416 86.316 28.44 ;
     RECT  86.281 28.44 86.364 28.704 ;
     RECT  86.281 28.704 86.316 28.728 ;
     RECT  86.281 28.728 86.364 28.992 ;
     RECT  86.281 28.992 86.316 29.016 ;
     RECT  86.281 29.016 86.364 29.28 ;
     RECT  86.281 29.28 86.316 29.304 ;
     RECT  86.281 29.304 86.364 29.52 ;
     RECT  86.281 29.52 86.316 29.544 ;
     RECT  86.281 29.544 86.364 29.808 ;
     RECT  86.281 29.808 86.316 29.832 ;
     RECT  86.281 29.832 86.364 30.096 ;
     RECT  86.281 30.096 86.316 30.12 ;
     RECT  86.281 30.12 86.364 30.384 ;
     RECT  86.281 30.384 86.316 30.408 ;
     RECT  86.281 30.408 86.364 30.672 ;
     RECT  86.281 30.672 86.316 30.696 ;
     RECT  86.281 30.696 86.364 30.96 ;
     RECT  86.281 30.96 86.316 30.984 ;
     RECT  86.281 30.984 86.364 31.248 ;
     RECT  86.281 31.248 86.316 31.272 ;
     RECT  86.281 31.272 86.364 31.536 ;
     RECT  86.281 31.536 86.316 31.56 ;
     RECT  86.281 31.56 86.364 31.824 ;
     RECT  86.281 31.824 86.316 31.848 ;
     RECT  86.281 31.848 86.364 32.112 ;
     RECT  86.281 32.112 86.316 32.136 ;
     RECT  86.281 32.136 86.364 32.4 ;
     RECT  86.281 32.4 86.316 32.424 ;
     RECT  86.281 32.424 86.364 32.688 ;
     RECT  86.281 32.688 86.316 32.712 ;
     RECT  86.281 32.712 86.364 32.976 ;
     RECT  86.281 32.976 86.316 33 ;
     RECT  86.281 33 86.364 33.264 ;
     RECT  86.281 33.264 86.316 33.288 ;
     RECT  86.281 33.288 86.364 33.552 ;
     RECT  86.281 33.552 86.316 33.576 ;
     RECT  86.281 33.576 86.364 33.84 ;
     RECT  86.281 33.84 86.316 33.864 ;
     RECT  86.281 33.864 86.364 34.128 ;
     RECT  86.281 34.128 86.316 34.152 ;
     RECT  86.281 34.152 86.364 34.416 ;
     RECT  86.281 34.416 86.316 34.44 ;
     RECT  86.281 34.44 86.364 34.704 ;
     RECT  86.281 34.704 86.316 34.728 ;
     RECT  86.281 34.728 86.364 34.992 ;
     RECT  86.281 34.992 86.316 35.016 ;
     RECT  86.281 35.016 86.364 35.232 ;
     RECT  86.281 35.232 86.316 35.256 ;
     RECT  86.281 35.256 86.364 35.52 ;
     RECT  86.281 35.52 86.316 35.544 ;
     RECT  86.281 35.544 86.364 35.808 ;
     RECT  86.281 35.808 86.316 35.832 ;
     RECT  86.281 35.832 86.364 36.096 ;
     RECT  86.281 36.096 86.316 36.12 ;
     RECT  86.281 36.12 86.364 36.384 ;
     RECT  86.281 36.384 86.316 36.408 ;
     RECT  86.281 36.408 86.364 36.672 ;
     RECT  86.281 36.672 86.316 36.696 ;
     RECT  86.281 36.696 86.364 36.96 ;
     RECT  86.281 36.96 86.316 36.984 ;
     RECT  86.281 36.984 86.364 37.248 ;
     RECT  86.281 37.248 86.316 37.272 ;
     RECT  86.281 37.272 86.364 37.536 ;
     RECT  86.281 37.536 86.316 37.56 ;
     RECT  86.281 37.56 86.364 37.824 ;
     RECT  86.281 37.824 86.316 37.848 ;
     RECT  86.281 37.848 86.364 38.112 ;
     RECT  86.281 38.112 86.316 38.136 ;
     RECT  86.281 38.136 86.364 38.4 ;
     RECT  86.281 38.4 86.316 38.424 ;
     RECT  86.281 38.424 86.364 38.688 ;
     RECT  86.281 38.688 86.316 38.712 ;
     RECT  86.281 38.712 86.364 38.976 ;
     RECT  86.281 38.976 86.316 39 ;
     RECT  86.281 39 86.364 39.264 ;
     RECT  86.281 39.264 86.316 39.288 ;
     RECT  86.281 39.288 86.364 39.552 ;
     RECT  86.281 39.552 86.316 39.576 ;
     RECT  86.281 39.576 86.364 39.84 ;
     RECT  86.281 39.84 86.316 39.864 ;
     RECT  86.281 39.864 86.364 40.128 ;
     RECT  86.281 40.128 86.316 40.152 ;
     RECT  86.281 40.152 86.364 40.416 ;
     RECT  86.281 40.416 86.316 40.44 ;
     RECT  86.281 40.44 86.364 40.704 ;
     RECT  86.281 40.704 86.316 40.728 ;
     RECT  86.281 40.728 86.364 40.944 ;
     RECT  86.281 40.944 86.316 40.968 ;
     RECT  86.281 40.968 86.364 41.232 ;
     RECT  86.281 41.232 86.316 41.256 ;
     RECT  86.281 41.256 86.364 41.52 ;
     RECT  86.281 41.52 86.316 41.544 ;
     RECT  86.281 41.544 86.364 41.808 ;
     RECT  86.281 41.808 86.316 41.832 ;
     RECT  86.281 41.832 86.364 42.096 ;
     RECT  86.281 42.096 86.316 42.12 ;
     RECT  86.281 42.12 86.364 42.384 ;
     RECT  86.281 42.384 86.316 42.408 ;
     RECT  86.281 42.408 86.364 42.672 ;
     RECT  86.281 42.672 86.316 42.696 ;
     RECT  86.281 42.696 86.364 42.96 ;
     RECT  86.281 42.96 86.316 42.984 ;
     RECT  86.281 42.984 86.364 43.248 ;
     RECT  86.281 43.248 86.316 43.272 ;
     RECT  86.281 43.272 86.364 43.536 ;
     RECT  86.281 43.536 86.316 43.56 ;
     RECT  86.281 43.56 86.364 43.824 ;
     RECT  86.281 43.824 86.316 43.848 ;
     RECT  86.281 43.848 86.364 44.112 ;
     RECT  86.281 44.112 86.316 44.136 ;
     RECT  86.281 44.136 86.364 44.4 ;
     RECT  86.281 44.4 86.316 44.424 ;
     RECT  86.281 44.424 86.364 44.688 ;
     RECT  86.281 44.688 86.316 44.712 ;
     RECT  86.281 44.712 86.364 44.976 ;
     RECT  86.281 44.976 86.316 45 ;
     RECT  86.281 45 86.364 45.264 ;
     RECT  86.281 45.264 86.316 45.288 ;
     RECT  86.281 45.288 86.364 45.552 ;
     RECT  86.281 45.552 86.316 45.576 ;
     RECT  86.281 45.576 86.364 45.84 ;
     RECT  86.281 45.84 86.316 45.864 ;
     RECT  86.281 45.864 86.364 46.128 ;
     RECT  86.281 46.128 86.316 46.152 ;
     RECT  86.281 46.152 86.364 46.368 ;
     RECT  86.281 46.368 86.316 46.392 ;
     RECT  86.281 46.392 86.364 46.656 ;
     RECT  86.281 46.656 86.316 46.68 ;
     RECT  86.281 46.68 86.364 46.944 ;
     RECT  86.281 46.944 86.316 46.968 ;
     RECT  86.281 46.968 86.364 47.232 ;
     RECT  86.281 47.232 86.316 47.256 ;
     RECT  86.281 47.256 86.364 47.52 ;
     RECT  86.281 47.52 86.316 47.544 ;
     RECT  86.281 47.544 86.364 47.808 ;
     RECT  86.281 47.808 86.316 47.832 ;
     RECT  86.281 47.832 86.364 48.096 ;
     RECT  86.281 48.096 86.316 48.12 ;
     RECT  86.281 48.12 86.364 48.384 ;
     RECT  86.281 48.384 86.316 48.408 ;
     RECT  86.281 48.408 86.364 48.672 ;
     RECT  86.281 48.672 86.316 48.696 ;
     RECT  86.281 48.696 86.364 48.96 ;
     RECT  86.281 48.96 86.316 48.984 ;
     RECT  86.281 48.984 86.364 49.248 ;
     RECT  86.281 49.248 86.316 49.272 ;
     RECT  86.281 49.272 86.364 49.536 ;
     RECT  86.281 49.536 86.316 49.56 ;
     RECT  86.281 49.56 86.364 49.824 ;
     RECT  86.281 49.824 86.316 49.848 ;
     RECT  86.281 49.848 86.364 50.112 ;
     RECT  86.281 50.112 86.316 50.136 ;
     RECT  86.281 50.136 86.364 50.4 ;
     RECT  86.281 50.4 86.316 50.424 ;
     RECT  86.281 50.424 86.364 50.688 ;
     RECT  86.281 50.688 86.316 50.712 ;
     RECT  86.281 50.712 86.364 50.976 ;
     RECT  86.281 50.976 86.316 51 ;
     RECT  86.281 51 86.364 51.264 ;
     RECT  86.281 51.264 86.316 51.288 ;
     RECT  86.281 51.288 86.364 51.552 ;
     RECT  86.281 51.552 86.316 51.576 ;
     RECT  86.281 51.576 86.364 51.84 ;
     RECT  86.281 51.84 86.316 51.864 ;
     RECT  86.281 51.864 86.364 52.08 ;
     RECT  86.281 52.08 86.316 52.104 ;
     RECT  86.281 52.104 86.364 52.368 ;
     RECT  86.281 52.368 86.316 52.392 ;
     RECT  86.281 52.392 86.364 52.656 ;
     RECT  86.281 52.656 86.316 52.68 ;
     RECT  86.281 52.68 86.364 52.944 ;
     RECT  86.281 52.944 86.316 52.968 ;
     RECT  86.281 52.968 86.364 53.232 ;
     RECT  86.281 53.232 86.316 53.256 ;
     RECT  86.281 53.256 86.364 53.52 ;
     RECT  86.281 53.52 86.316 53.544 ;
     RECT  86.281 53.544 86.364 53.808 ;
     RECT  86.281 53.808 86.316 53.832 ;
     RECT  86.281 53.832 86.364 54.096 ;
     RECT  86.281 54.096 86.316 54.12 ;
     RECT  86.281 54.12 86.364 54.384 ;
     RECT  86.281 54.384 86.316 54.408 ;
     RECT  86.281 54.408 86.364 54.672 ;
     RECT  86.281 54.672 86.316 54.696 ;
     RECT  86.281 54.696 86.364 54.96 ;
     RECT  86.281 54.96 86.316 54.984 ;
     RECT  86.281 54.984 86.364 55.248 ;
     RECT  86.281 55.248 86.316 55.272 ;
     RECT  86.281 55.272 86.364 55.536 ;
     RECT  86.281 55.536 86.316 55.56 ;
     RECT  86.281 55.56 86.364 55.824 ;
     RECT  86.281 55.824 86.316 55.848 ;
     RECT  86.281 55.848 86.364 56.112 ;
     RECT  86.281 56.112 86.316 56.136 ;
     RECT  86.281 56.136 86.364 56.4 ;
     RECT  86.281 56.4 86.316 56.424 ;
     RECT  86.281 56.424 86.364 56.688 ;
     RECT  86.281 56.688 86.316 56.712 ;
     RECT  86.281 56.712 86.364 56.976 ;
     RECT  86.281 56.976 86.316 57 ;
     RECT  86.281 57 86.364 57.264 ;
     RECT  86.281 57.264 86.316 57.288 ;
     RECT  86.281 57.288 86.364 57.504 ;
     RECT  86.281 57.504 86.316 57.528 ;
     RECT  86.281 57.528 86.364 57.792 ;
     RECT  86.281 57.792 86.316 57.816 ;
     RECT  86.281 57.816 86.364 58.08 ;
     RECT  86.281 58.08 86.316 58.104 ;
     RECT  86.281 58.104 86.364 58.368 ;
     RECT  86.281 58.368 86.316 58.392 ;
     RECT  86.281 58.392 86.364 58.656 ;
     RECT  86.281 58.656 86.316 58.68 ;
     RECT  86.281 58.68 86.364 58.944 ;
     RECT  86.281 58.944 86.316 58.968 ;
     RECT  86.281 58.968 86.364 59.232 ;
     RECT  86.281 59.232 86.316 59.256 ;
     RECT  86.281 59.256 86.364 59.52 ;
     RECT  86.281 59.52 86.316 59.544 ;
     RECT  86.281 59.544 86.364 59.808 ;
     RECT  86.281 59.808 86.316 59.832 ;
     RECT  86.281 59.832 86.364 60.096 ;
     RECT  86.281 60.096 86.316 60.12 ;
     RECT  86.281 60.12 86.364 60.384 ;
     RECT  86.281 60.384 86.316 60.408 ;
     RECT  86.281 60.408 86.364 60.672 ;
     RECT  86.281 60.672 86.316 60.696 ;
     RECT  86.281 60.696 86.364 60.96 ;
     RECT  86.281 60.96 86.316 60.984 ;
     RECT  86.281 60.984 86.364 61.248 ;
     RECT  86.281 61.248 86.316 61.272 ;
     RECT  86.281 61.272 86.364 61.536 ;
     RECT  86.281 61.536 86.316 61.56 ;
     RECT  86.281 61.56 86.364 61.824 ;
     RECT  86.281 61.824 86.316 61.848 ;
     RECT  86.281 61.848 86.364 62.112 ;
     RECT  86.281 62.112 86.316 62.136 ;
     RECT  86.281 62.136 86.364 62.4 ;
     RECT  86.281 62.4 86.316 62.424 ;
     RECT  86.281 62.424 86.364 62.688 ;
     RECT  86.281 62.688 86.316 62.712 ;
     RECT  86.281 62.712 86.364 62.976 ;
     RECT  86.281 62.976 86.316 63 ;
     RECT  86.281 63 86.364 63.216 ;
     RECT  86.281 63.216 86.316 63.24 ;
     RECT  86.281 63.24 86.364 63.504 ;
     RECT  86.281 63.504 86.316 63.528 ;
     RECT  86.281 63.528 86.364 63.792 ;
     RECT  86.281 63.792 86.316 63.816 ;
     RECT  86.281 63.816 86.364 64.08 ;
     RECT  86.281 64.08 86.316 64.104 ;
     RECT  86.281 64.104 86.364 64.368 ;
     RECT  86.281 64.368 86.316 64.392 ;
     RECT  86.281 64.392 86.364 64.656 ;
     RECT  86.281 64.656 86.316 64.68 ;
     RECT  86.281 64.68 86.364 64.944 ;
     RECT  86.281 64.944 86.316 64.968 ;
     RECT  86.281 64.968 86.364 65.232 ;
     RECT  86.281 65.232 86.316 65.256 ;
     RECT  86.281 65.256 86.364 65.52 ;
     RECT  86.281 65.52 86.316 65.544 ;
     RECT  86.281 65.544 86.364 65.808 ;
     RECT  86.281 65.808 86.316 65.832 ;
     RECT  86.281 65.832 86.364 66.096 ;
     RECT  86.281 66.096 86.316 66.12 ;
     RECT  86.281 66.12 86.364 66.384 ;
     RECT  86.281 66.384 86.316 66.408 ;
     RECT  86.281 66.408 86.364 66.672 ;
     RECT  86.281 66.672 86.316 66.696 ;
     RECT  86.281 66.696 86.364 66.96 ;
     RECT  86.281 66.96 86.316 66.984 ;
     RECT  86.281 66.984 86.364 67.248 ;
     RECT  86.281 67.248 86.316 67.272 ;
     RECT  86.281 67.272 86.364 67.536 ;
     RECT  86.281 67.536 86.316 67.56 ;
     RECT  86.281 67.56 86.364 67.824 ;
     RECT  86.281 67.824 86.316 67.848 ;
     RECT  86.281 67.848 86.364 68.112 ;
     RECT  86.281 68.112 86.316 68.136 ;
     RECT  86.281 68.136 86.364 68.4 ;
     RECT  86.281 68.4 86.316 68.424 ;
     RECT  86.281 68.424 86.364 68.64 ;
     RECT  86.281 68.64 86.316 68.664 ;
     RECT  86.281 68.664 86.364 68.928 ;
     RECT  86.281 68.928 86.316 68.952 ;
     RECT  86.281 68.952 86.364 69.216 ;
     RECT  86.281 69.216 86.316 69.24 ;
     RECT  86.281 69.24 86.364 69.504 ;
     RECT  86.281 69.504 86.316 69.528 ;
     RECT  86.281 69.528 86.364 69.792 ;
     RECT  86.281 69.792 86.316 69.816 ;
     RECT  86.281 69.816 86.364 70.08 ;
     RECT  86.281 70.08 86.316 70.104 ;
     RECT  86.281 70.104 86.364 70.368 ;
     RECT  86.281 70.368 86.316 70.392 ;
     RECT  86.281 70.392 86.364 70.656 ;
     RECT  86.281 70.656 86.316 70.68 ;
     RECT  86.281 70.68 86.364 70.944 ;
     RECT  86.281 70.944 86.316 70.968 ;
     RECT  86.281 70.968 86.364 71.232 ;
     RECT  86.281 71.232 86.316 71.256 ;
     RECT  86.281 71.256 86.364 71.52 ;
     RECT  86.281 71.52 86.316 71.544 ;
     RECT  86.281 71.544 86.364 71.808 ;
     RECT  86.281 71.808 86.316 71.832 ;
     RECT  86.281 71.832 86.364 72.096 ;
     RECT  86.281 72.096 86.316 72.12 ;
     RECT  86.281 72.12 86.364 72.384 ;
     RECT  86.281 72.384 86.316 72.408 ;
     RECT  86.281 72.408 86.364 72.672 ;
     RECT  86.281 72.672 86.316 72.696 ;
     RECT  86.281 72.696 86.364 72.96 ;
     RECT  86.281 72.96 86.316 72.984 ;
     RECT  86.281 72.984 86.364 73.248 ;
     RECT  86.281 73.248 86.316 73.272 ;
     RECT  86.281 73.272 86.364 73.536 ;
     RECT  86.281 73.536 86.316 73.56 ;
     RECT  86.281 73.56 86.364 73.824 ;
     RECT  86.281 73.824 86.316 73.848 ;
     RECT  86.281 73.848 86.364 74.112 ;
     RECT  86.281 74.112 86.316 74.136 ;
     RECT  86.281 74.136 86.364 74.352 ;
     RECT  86.281 74.352 86.316 74.376 ;
     RECT  86.281 74.376 86.364 74.64 ;
     RECT  86.281 74.64 86.316 74.664 ;
     RECT  86.281 74.664 86.364 74.928 ;
     RECT  86.281 74.928 86.316 74.952 ;
     RECT  86.281 74.952 86.364 75.504 ;
     RECT  86.281 75.504 86.316 75.528 ;
     RECT  86.281 75.528 86.364 75.792 ;
     RECT  86.281 75.792 86.316 75.816 ;
     RECT  86.281 75.816 86.364 76.032 ;
     RECT  86.281 76.032 86.316 76.056 ;
     RECT  86.281 76.056 86.364 76.272 ;
     RECT  86.281 76.272 86.316 76.296 ;
     RECT  86.281 76.296 86.364 76.56 ;
     RECT  86.281 76.56 86.316 76.584 ;
     RECT  86.281 76.584 86.364 76.8 ;
     RECT  86.281 76.8 86.316 76.824 ;
     RECT  86.281 76.824 86.364 77.04 ;
     RECT  86.281 77.04 86.316 77.064 ;
     RECT  86.281 77.064 86.364 77.616 ;
     RECT  86.281 77.616 86.316 77.64 ;
     RECT  86.281 77.64 86.364 77.856 ;
     RECT  86.281 77.856 86.316 77.88 ;
     RECT  86.281 77.88 86.364 78.096 ;
     RECT  86.281 78.096 86.316 78.12 ;
     RECT  86.281 78.12 86.364 78.336 ;
     RECT  86.281 78.336 86.316 78.36 ;
     RECT  86.281 78.36 86.364 78.576 ;
     RECT  86.281 78.576 86.316 78.6 ;
     RECT  86.281 78.6 86.364 79.44 ;
     RECT  86.281 79.44 86.316 79.464 ;
     RECT  86.281 79.464 86.364 80.304 ;
     RECT  86.281 80.304 86.316 80.328 ;
     RECT  86.281 80.328 86.364 80.592 ;
     RECT  86.281 80.592 86.316 80.616 ;
     RECT  86.281 80.616 86.364 80.88 ;
     RECT  86.281 80.88 86.316 80.904 ;
     RECT  86.281 80.904 86.364 81.12 ;
     RECT  86.281 81.12 86.316 81.144 ;
     RECT  86.281 81.144 86.364 81.408 ;
     RECT  86.281 81.408 86.316 81.432 ;
     RECT  86.281 81.432 86.364 81.696 ;
     RECT  86.281 81.696 86.316 81.72 ;
     RECT  86.281 81.72 86.364 81.936 ;
     RECT  86.281 81.936 86.316 81.96 ;
     RECT  86.281 81.96 86.364 82.224 ;
     RECT  86.281 82.224 86.316 82.248 ;
     RECT  86.281 82.248 86.364 82.464 ;
     RECT  86.281 82.464 86.316 82.488 ;
     RECT  86.281 82.488 86.364 82.752 ;
     RECT  86.281 82.752 86.316 82.776 ;
     RECT  86.281 82.776 86.364 83.616 ;
     RECT  86.281 83.616 86.316 83.64 ;
    LAYER M5 ;
     RECT  2.4 2.137 2.52 2.151 ;
     RECT  7.8 2.137 7.92 2.151 ;
     RECT  13.2 2.137 13.32 2.151 ;
     RECT  18.6 2.137 18.72 2.151 ;
     RECT  24 2.137 24.12 2.151 ;
     RECT  29.4 2.137 29.52 2.151 ;
     RECT  34.8 2.137 34.92 2.151 ;
     RECT  40.2 2.137 40.32 2.151 ;
     RECT  45.6 2.137 45.72 2.151 ;
     RECT  51 2.137 51.12 2.151 ;
     RECT  56.4 2.137 56.52 2.151 ;
     RECT  61.8 2.137 61.92 2.151 ;
     RECT  67.2 2.137 67.32 2.151 ;
     RECT  72.6 2.137 72.72 2.151 ;
     RECT  78 2.137 78.12 2.151 ;
     RECT  83.4 2.137 83.52 2.151 ;
     RECT  7.8 2.151 8.112 3.397 ;
     RECT  4.368 3.685 4.392 4.547 ;
     RECT  7.8 3.397 8.232 6.323 ;
     RECT  7.8 6.323 8.112 7.909 ;
     RECT  6.864 7.909 8.112 9.011 ;
     RECT  5.328 5.077 5.352 9.685 ;
     RECT  5.328 9.685 5.496 9.731 ;
     RECT  4.224 10.741 4.248 11.651 ;
     RECT  5.472 9.731 5.496 13.333 ;
     RECT  7.8 9.011 8.112 13.333 ;
     RECT  5.472 13.333 6.024 14.099 ;
     RECT  7.8 13.333 8.376 14.387 ;
     RECT  7.8 14.387 8.112 17.605 ;
     RECT  7.68 17.605 8.112 18.757 ;
     RECT  7.152 18.757 8.112 19.427 ;
     RECT  5.472 14.099 5.496 20.773 ;
     RECT  5.472 20.773 5.64 20.819 ;
     RECT  4.512 20.821 4.536 21.923 ;
     RECT  7.68 19.427 8.112 23.315 ;
     RECT  5.616 20.819 5.64 25.139 ;
     RECT  6.672 25.141 6.696 27.875 ;
     RECT  7.8 23.315 8.112 28.693 ;
     RECT  6.864 28.693 8.112 29.075 ;
     RECT  5.664 25.429 5.688 31.189 ;
     RECT  5.664 31.189 5.736 31.285 ;
     RECT  5.472 31.285 5.736 32.195 ;
     RECT  5.472 32.195 5.496 35.557 ;
     RECT  5.472 35.557 5.688 35.603 ;
     RECT  4.368 33.061 4.392 36.227 ;
     RECT  7.8 29.075 8.112 39.013 ;
     RECT  4.56 38.149 4.584 39.491 ;
     RECT  5.664 35.603 5.688 39.877 ;
     RECT  7.056 39.013 8.112 40.451 ;
     RECT  4.8 39.877 5.688 40.499 ;
     RECT  4.8 40.499 4.824 41.651 ;
     RECT  32.736 36.997 32.76 43.189 ;
     RECT  32.544 43.189 32.76 43.235 ;
     RECT  7.8 40.451 8.112 44.197 ;
     RECT  7.392 44.197 8.112 45.635 ;
     RECT  5.472 46.117 5.496 46.645 ;
     RECT  4.512 46.645 5.496 46.787 ;
     RECT  7.8 45.635 8.112 48.421 ;
     RECT  7.152 48.421 8.112 50.291 ;
     RECT  5.472 46.787 5.496 50.389 ;
     RECT  5.472 50.389 5.688 50.435 ;
     RECT  32.544 43.235 32.568 50.771 ;
     RECT  7.536 50.291 8.112 51.347 ;
     RECT  5.664 50.435 5.688 53.509 ;
     RECT  5.664 53.509 6.264 54.179 ;
     RECT  33.696 51.253 33.72 56.389 ;
     RECT  34.8 2.151 35.112 56.389 ;
     RECT  33.696 56.389 35.112 56.435 ;
     RECT  7.8 51.347 8.112 57.445 ;
     RECT  6.912 57.445 8.112 58.163 ;
     RECT  5.664 54.179 5.688 58.693 ;
     RECT  5.664 58.693 6.264 60.563 ;
     RECT  5.664 60.563 5.688 60.997 ;
     RECT  5.376 60.997 5.688 61.043 ;
     RECT  45.6 2.151 45.912 62.677 ;
     RECT  51 2.151 51.312 62.677 ;
     RECT  67.2 2.151 67.512 62.677 ;
     RECT  83.4 2.151 83.712 62.677 ;
     RECT  45.6 62.677 46.776 62.819 ;
     RECT  50.688 62.677 51.312 62.819 ;
     RECT  58.704 62.677 58.728 62.819 ;
     RECT  66.672 62.677 67.512 62.819 ;
     RECT  70.608 62.677 70.632 62.819 ;
     RECT  74.64 62.677 74.664 62.819 ;
     RECT  82.656 62.677 83.712 62.819 ;
     RECT  7.8 58.163 8.112 63.205 ;
     RECT  7.8 63.205 8.376 64.595 ;
     RECT  7.8 64.595 8.232 67.859 ;
     RECT  0.192 43.285 0.216 68.387 ;
     RECT  5.376 61.043 5.4 70.933 ;
     RECT  4.464 70.933 5.4 71.843 ;
     RECT  5.376 71.843 5.4 73.477 ;
     RECT  5.376 73.477 6.216 74.723 ;
     RECT  5.376 74.723 5.4 75.781 ;
     RECT  4.56 75.781 5.4 78.131 ;
     RECT  4.56 78.131 4.584 78.565 ;
     RECT  3.984 78.565 4.584 78.611 ;
     RECT  3.984 78.611 4.008 79.235 ;
     RECT  33.888 56.435 35.112 81.923 ;
     RECT  82.032 79.189 82.056 83.267 ;
     RECT  2.4 2.151 2.712 84.249 ;
     RECT  7.8 67.859 8.112 84.249 ;
     RECT  13.2 2.151 13.512 84.249 ;
     RECT  18.6 2.151 18.912 84.249 ;
     RECT  24 2.151 24.312 84.249 ;
     RECT  29.4 2.151 29.712 84.249 ;
     RECT  34.8 81.923 35.112 84.249 ;
     RECT  40.2 2.151 40.512 84.249 ;
     RECT  45.6 62.819 45.912 84.249 ;
     RECT  51 62.819 51.312 84.249 ;
     RECT  56.4 2.151 56.712 84.249 ;
     RECT  61.8 2.151 62.112 84.249 ;
     RECT  67.2 62.819 67.512 84.249 ;
     RECT  72.6 2.151 72.912 84.249 ;
     RECT  78 2.151 78.312 84.249 ;
     RECT  83.4 62.819 83.712 84.249 ;
     RECT  2.4 84.249 2.52 84.263 ;
     RECT  7.8 84.249 7.92 84.263 ;
     RECT  13.2 84.249 13.32 84.263 ;
     RECT  18.6 84.249 18.72 84.263 ;
     RECT  24 84.249 24.12 84.263 ;
     RECT  29.4 84.249 29.52 84.263 ;
     RECT  34.8 84.249 34.92 84.263 ;
     RECT  40.2 84.249 40.32 84.263 ;
     RECT  45.6 84.249 45.72 84.263 ;
     RECT  51 84.249 51.12 84.263 ;
     RECT  56.4 84.249 56.52 84.263 ;
     RECT  61.8 84.249 61.92 84.263 ;
     RECT  67.2 84.249 67.32 84.263 ;
     RECT  72.6 84.249 72.72 84.263 ;
     RECT  78 84.249 78.12 84.263 ;
     RECT  83.4 84.249 83.52 84.263 ;
     RECT  5.352 7.909 6.864 9.011 ;
     RECT  5.352 9.011 5.496 9.685 ;
     RECT  5.328 9.731 5.472 10.741 ;
     RECT  2.712 10.741 4.224 11.651 ;
     RECT  4.248 10.741 5.472 11.651 ;
     RECT  5.472 20.819 5.616 20.821 ;
     RECT  4.536 20.821 5.616 21.923 ;
     RECT  6.696 25.141 7.8 27.875 ;
     RECT  5.688 25.429 6.672 27.875 ;
     RECT  5.688 27.875 7.8 28.693 ;
     RECT  5.688 28.693 6.864 29.075 ;
     RECT  4.392 33.061 5.472 35.603 ;
     RECT  4.392 35.603 5.664 36.227 ;
     RECT  4.584 38.149 5.664 39.491 ;
     RECT  5.688 39.013 7.056 40.451 ;
     RECT  4.8 39.491 5.664 39.877 ;
     RECT  33.72 51.253 34.8 56.389 ;
     RECT  5.688 57.445 6.912 58.163 ;
     RECT  5.688 58.163 6.264 58.693 ;
     RECT  2.712 78.565 3.984 79.235 ;
     RECT  82.056 79.189 83.4 83.267 ;
  END
END ot_hbm_su_programme_pghead
END LIBRARY
